VERSION 5.8 ;
BUSBITCHARS "[]" ;
DIVIDERCHAR "/" ;
UNITS
    DATABASE MICRONS 1000 ;
END UNITS

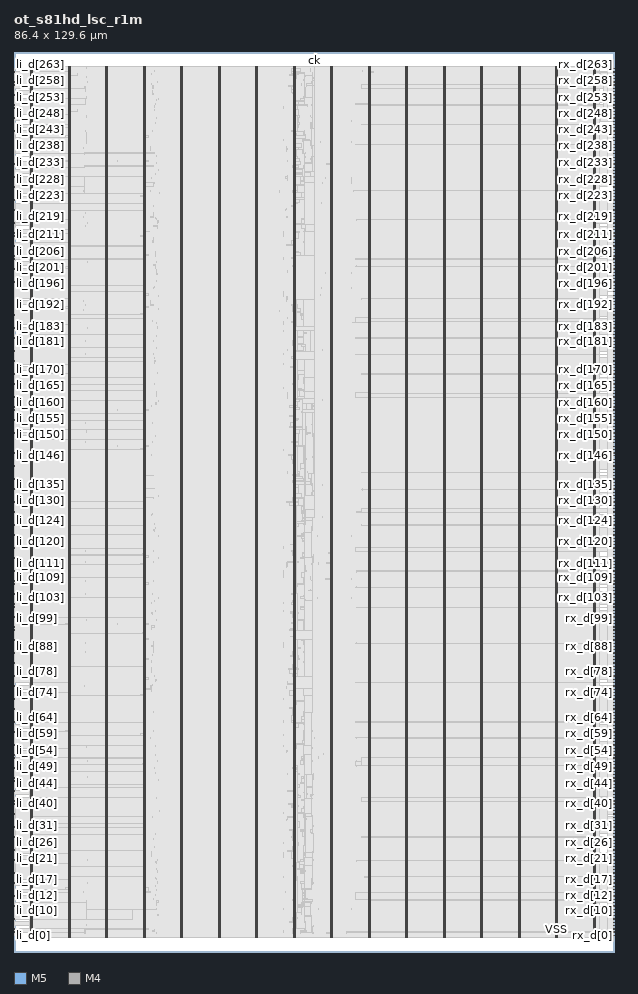
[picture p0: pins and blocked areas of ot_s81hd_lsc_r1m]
MACRO ot_s81hd_lsc_r1m
  FOREIGN ot_s81hd_lsc_r1m 0 0 ;
  CLASS BLOCK ;
  SIZE 86.4 BY 129.6 ;
  PIN ck
    DIRECTION INPUT ;
    USE SIGNAL ;
    PORT
      LAYER M5 ;
        RECT  43.2 129.516 43.224 129.6 ;
    END
  END ck
  PIN li_d[0]
    DIRECTION INPUT ;
    USE SIGNAL ;
    PORT
      LAYER M4 ;
        RECT  0 2.4 0.084 2.424 ;
    END
  END li_d[0]
  PIN li_d[100]
    DIRECTION INPUT ;
    USE SIGNAL ;
    PORT
      LAYER M4 ;
        RECT  0 49.68 0.084 49.704 ;
    END
  END li_d[100]
  PIN li_d[101]
    DIRECTION INPUT ;
    USE SIGNAL ;
    PORT
      LAYER M4 ;
        RECT  0 50.112 0.084 50.136 ;
    END
  END li_d[101]
  PIN li_d[102]
    DIRECTION INPUT ;
    USE SIGNAL ;
    PORT
      LAYER M4 ;
        RECT  0 50.592 0.084 50.616 ;
    END
  END li_d[102]
  PIN li_d[103]
    DIRECTION INPUT ;
    USE SIGNAL ;
    PORT
      LAYER M4 ;
        RECT  0 51.072 0.084 51.096 ;
    END
  END li_d[103]
  PIN li_d[104]
    DIRECTION INPUT ;
    USE SIGNAL ;
    PORT
      LAYER M4 ;
        RECT  0 51.552 0.084 51.576 ;
    END
  END li_d[104]
  PIN li_d[105]
    DIRECTION INPUT ;
    USE SIGNAL ;
    PORT
      LAYER M4 ;
        RECT  0 52.032 0.084 52.056 ;
    END
  END li_d[105]
  PIN li_d[106]
    DIRECTION INPUT ;
    USE SIGNAL ;
    PORT
      LAYER M4 ;
        RECT  0 52.512 0.084 52.536 ;
    END
  END li_d[106]
  PIN li_d[107]
    DIRECTION INPUT ;
    USE SIGNAL ;
    PORT
      LAYER M4 ;
        RECT  0 52.992 0.084 53.016 ;
    END
  END li_d[107]
  PIN li_d[108]
    DIRECTION INPUT ;
    USE SIGNAL ;
    PORT
      LAYER M4 ;
        RECT  0 53.424 0.084 53.448 ;
    END
  END li_d[108]
  PIN li_d[109]
    DIRECTION INPUT ;
    USE SIGNAL ;
    PORT
      LAYER M4 ;
        RECT  0 53.904 0.084 53.928 ;
    END
  END li_d[109]
  PIN li_d[10]
    DIRECTION INPUT ;
    USE SIGNAL ;
    PORT
      LAYER M4 ;
        RECT  0 7.104 0.084 7.128 ;
    END
  END li_d[10]
  PIN li_d[110]
    DIRECTION INPUT ;
    USE SIGNAL ;
    PORT
      LAYER M4 ;
        RECT  0 54.384 0.084 54.408 ;
    END
  END li_d[110]
  PIN li_d[111]
    DIRECTION INPUT ;
    USE SIGNAL ;
    PORT
      LAYER M4 ;
        RECT  0 54.864 0.084 54.888 ;
    END
  END li_d[111]
  PIN li_d[112]
    DIRECTION INPUT ;
    USE SIGNAL ;
    PORT
      LAYER M4 ;
        RECT  0 55.344 0.084 55.368 ;
    END
  END li_d[112]
  PIN li_d[113]
    DIRECTION INPUT ;
    USE SIGNAL ;
    PORT
      LAYER M4 ;
        RECT  0 55.824 0.084 55.848 ;
    END
  END li_d[113]
  PIN li_d[114]
    DIRECTION INPUT ;
    USE SIGNAL ;
    PORT
      LAYER M4 ;
        RECT  0 56.256 0.084 56.28 ;
    END
  END li_d[114]
  PIN li_d[115]
    DIRECTION INPUT ;
    USE SIGNAL ;
    PORT
      LAYER M4 ;
        RECT  0 56.736 0.084 56.76 ;
    END
  END li_d[115]
  PIN li_d[116]
    DIRECTION INPUT ;
    USE SIGNAL ;
    PORT
      LAYER M4 ;
        RECT  0 57.216 0.084 57.24 ;
    END
  END li_d[116]
  PIN li_d[117]
    DIRECTION INPUT ;
    USE SIGNAL ;
    PORT
      LAYER M4 ;
        RECT  0 57.696 0.084 57.72 ;
    END
  END li_d[117]
  PIN li_d[118]
    DIRECTION INPUT ;
    USE SIGNAL ;
    PORT
      LAYER M4 ;
        RECT  0 58.176 0.084 58.2 ;
    END
  END li_d[118]
  PIN li_d[119]
    DIRECTION INPUT ;
    USE SIGNAL ;
    PORT
      LAYER M4 ;
        RECT  0 58.656 0.084 58.68 ;
    END
  END li_d[119]
  PIN li_d[11]
    DIRECTION INPUT ;
    USE SIGNAL ;
    PORT
      LAYER M4 ;
        RECT  0 7.584 0.084 7.608 ;
    END
  END li_d[11]
  PIN li_d[120]
    DIRECTION INPUT ;
    USE SIGNAL ;
    PORT
      LAYER M4 ;
        RECT  0 59.136 0.084 59.16 ;
    END
  END li_d[120]
  PIN li_d[121]
    DIRECTION INPUT ;
    USE SIGNAL ;
    PORT
      LAYER M4 ;
        RECT  0 59.568 0.084 59.592 ;
    END
  END li_d[121]
  PIN li_d[122]
    DIRECTION INPUT ;
    USE SIGNAL ;
    PORT
      LAYER M4 ;
        RECT  0 60.048 0.084 60.072 ;
    END
  END li_d[122]
  PIN li_d[123]
    DIRECTION INPUT ;
    USE SIGNAL ;
    PORT
      LAYER M4 ;
        RECT  0 60.528 0.084 60.552 ;
    END
  END li_d[123]
  PIN li_d[124]
    DIRECTION INPUT ;
    USE SIGNAL ;
    PORT
      LAYER M4 ;
        RECT  0 61.008 0.084 61.032 ;
    END
  END li_d[124]
  PIN li_d[125]
    DIRECTION INPUT ;
    USE SIGNAL ;
    PORT
      LAYER M4 ;
        RECT  0 61.488 0.084 61.512 ;
    END
  END li_d[125]
  PIN li_d[126]
    DIRECTION INPUT ;
    USE SIGNAL ;
    PORT
      LAYER M4 ;
        RECT  0 61.968 0.084 61.992 ;
    END
  END li_d[126]
  PIN li_d[127]
    DIRECTION INPUT ;
    USE SIGNAL ;
    PORT
      LAYER M4 ;
        RECT  0 62.448 0.084 62.472 ;
    END
  END li_d[127]
  PIN li_d[128]
    DIRECTION INPUT ;
    USE SIGNAL ;
    PORT
      LAYER M4 ;
        RECT  0 62.88 0.084 62.904 ;
    END
  END li_d[128]
  PIN li_d[129]
    DIRECTION INPUT ;
    USE SIGNAL ;
    PORT
      LAYER M4 ;
        RECT  0 63.36 0.084 63.384 ;
    END
  END li_d[129]
  PIN li_d[12]
    DIRECTION INPUT ;
    USE SIGNAL ;
    PORT
      LAYER M4 ;
        RECT  0 8.064 0.084 8.088 ;
    END
  END li_d[12]
  PIN li_d[130]
    DIRECTION INPUT ;
    USE SIGNAL ;
    PORT
      LAYER M4 ;
        RECT  0 63.84 0.084 63.864 ;
    END
  END li_d[130]
  PIN li_d[131]
    DIRECTION INPUT ;
    USE SIGNAL ;
    PORT
      LAYER M4 ;
        RECT  0 64.32 0.084 64.344 ;
    END
  END li_d[131]
  PIN li_d[132]
    DIRECTION INPUT ;
    USE SIGNAL ;
    PORT
      LAYER M4 ;
        RECT  0 64.8 0.084 64.824 ;
    END
  END li_d[132]
  PIN li_d[133]
    DIRECTION INPUT ;
    USE SIGNAL ;
    PORT
      LAYER M4 ;
        RECT  0 65.28 0.084 65.304 ;
    END
  END li_d[133]
  PIN li_d[134]
    DIRECTION INPUT ;
    USE SIGNAL ;
    PORT
      LAYER M4 ;
        RECT  0 65.712 0.084 65.736 ;
    END
  END li_d[134]
  PIN li_d[135]
    DIRECTION INPUT ;
    USE SIGNAL ;
    PORT
      LAYER M4 ;
        RECT  0 66.192 0.084 66.216 ;
    END
  END li_d[135]
  PIN li_d[136]
    DIRECTION INPUT ;
    USE SIGNAL ;
    PORT
      LAYER M4 ;
        RECT  0 66.672 0.084 66.696 ;
    END
  END li_d[136]
  PIN li_d[137]
    DIRECTION INPUT ;
    USE SIGNAL ;
    PORT
      LAYER M4 ;
        RECT  0 67.152 0.084 67.176 ;
    END
  END li_d[137]
  PIN li_d[138]
    DIRECTION INPUT ;
    USE SIGNAL ;
    PORT
      LAYER M4 ;
        RECT  0 67.632 0.084 67.656 ;
    END
  END li_d[138]
  PIN li_d[139]
    DIRECTION INPUT ;
    USE SIGNAL ;
    PORT
      LAYER M4 ;
        RECT  0 68.112 0.084 68.136 ;
    END
  END li_d[139]
  PIN li_d[13]
    DIRECTION INPUT ;
    USE SIGNAL ;
    PORT
      LAYER M4 ;
        RECT  0 8.544 0.084 8.568 ;
    END
  END li_d[13]
  PIN li_d[140]
    DIRECTION INPUT ;
    USE SIGNAL ;
    PORT
      LAYER M4 ;
        RECT  0 68.592 0.084 68.616 ;
    END
  END li_d[140]
  PIN li_d[141]
    DIRECTION INPUT ;
    USE SIGNAL ;
    PORT
      LAYER M4 ;
        RECT  0 69.024 0.084 69.048 ;
    END
  END li_d[141]
  PIN li_d[142]
    DIRECTION INPUT ;
    USE SIGNAL ;
    PORT
      LAYER M4 ;
        RECT  0 69.504 0.084 69.528 ;
    END
  END li_d[142]
  PIN li_d[143]
    DIRECTION INPUT ;
    USE SIGNAL ;
    PORT
      LAYER M4 ;
        RECT  0 69.984 0.084 70.008 ;
    END
  END li_d[143]
  PIN li_d[144]
    DIRECTION INPUT ;
    USE SIGNAL ;
    PORT
      LAYER M4 ;
        RECT  0 70.464 0.084 70.488 ;
    END
  END li_d[144]
  PIN li_d[145]
    DIRECTION INPUT ;
    USE SIGNAL ;
    PORT
      LAYER M4 ;
        RECT  0 70.944 0.084 70.968 ;
    END
  END li_d[145]
  PIN li_d[146]
    DIRECTION INPUT ;
    USE SIGNAL ;
    PORT
      LAYER M4 ;
        RECT  0 71.424 0.084 71.448 ;
    END
  END li_d[146]
  PIN li_d[147]
    DIRECTION INPUT ;
    USE SIGNAL ;
    PORT
      LAYER M4 ;
        RECT  0 71.856 0.084 71.88 ;
    END
  END li_d[147]
  PIN li_d[148]
    DIRECTION INPUT ;
    USE SIGNAL ;
    PORT
      LAYER M4 ;
        RECT  0 72.336 0.084 72.36 ;
    END
  END li_d[148]
  PIN li_d[149]
    DIRECTION INPUT ;
    USE SIGNAL ;
    PORT
      LAYER M4 ;
        RECT  0 72.816 0.084 72.84 ;
    END
  END li_d[149]
  PIN li_d[14]
    DIRECTION INPUT ;
    USE SIGNAL ;
    PORT
      LAYER M4 ;
        RECT  0 9.024 0.084 9.048 ;
    END
  END li_d[14]
  PIN li_d[150]
    DIRECTION INPUT ;
    USE SIGNAL ;
    PORT
      LAYER M4 ;
        RECT  0 73.296 0.084 73.32 ;
    END
  END li_d[150]
  PIN li_d[151]
    DIRECTION INPUT ;
    USE SIGNAL ;
    PORT
      LAYER M4 ;
        RECT  0 73.776 0.084 73.8 ;
    END
  END li_d[151]
  PIN li_d[152]
    DIRECTION INPUT ;
    USE SIGNAL ;
    PORT
      LAYER M4 ;
        RECT  0 74.256 0.084 74.28 ;
    END
  END li_d[152]
  PIN li_d[153]
    DIRECTION INPUT ;
    USE SIGNAL ;
    PORT
      LAYER M4 ;
        RECT  0 74.736 0.084 74.76 ;
    END
  END li_d[153]
  PIN li_d[154]
    DIRECTION INPUT ;
    USE SIGNAL ;
    PORT
      LAYER M4 ;
        RECT  0 75.168 0.084 75.192 ;
    END
  END li_d[154]
  PIN li_d[155]
    DIRECTION INPUT ;
    USE SIGNAL ;
    PORT
      LAYER M4 ;
        RECT  0 75.648 0.084 75.672 ;
    END
  END li_d[155]
  PIN li_d[156]
    DIRECTION INPUT ;
    USE SIGNAL ;
    PORT
      LAYER M4 ;
        RECT  0 76.128 0.084 76.152 ;
    END
  END li_d[156]
  PIN li_d[157]
    DIRECTION INPUT ;
    USE SIGNAL ;
    PORT
      LAYER M4 ;
        RECT  0 76.608 0.084 76.632 ;
    END
  END li_d[157]
  PIN li_d[158]
    DIRECTION INPUT ;
    USE SIGNAL ;
    PORT
      LAYER M4 ;
        RECT  0 77.088 0.084 77.112 ;
    END
  END li_d[158]
  PIN li_d[159]
    DIRECTION INPUT ;
    USE SIGNAL ;
    PORT
      LAYER M4 ;
        RECT  0 77.568 0.084 77.592 ;
    END
  END li_d[159]
  PIN li_d[15]
    DIRECTION INPUT ;
    USE SIGNAL ;
    PORT
      LAYER M4 ;
        RECT  0 9.456 0.084 9.48 ;
    END
  END li_d[15]
  PIN li_d[160]
    DIRECTION INPUT ;
    USE SIGNAL ;
    PORT
      LAYER M4 ;
        RECT  0 78.048 0.084 78.072 ;
    END
  END li_d[160]
  PIN li_d[161]
    DIRECTION INPUT ;
    USE SIGNAL ;
    PORT
      LAYER M4 ;
        RECT  0 78.48 0.084 78.504 ;
    END
  END li_d[161]
  PIN li_d[162]
    DIRECTION INPUT ;
    USE SIGNAL ;
    PORT
      LAYER M4 ;
        RECT  0 78.96 0.084 78.984 ;
    END
  END li_d[162]
  PIN li_d[163]
    DIRECTION INPUT ;
    USE SIGNAL ;
    PORT
      LAYER M4 ;
        RECT  0 79.44 0.084 79.464 ;
    END
  END li_d[163]
  PIN li_d[164]
    DIRECTION INPUT ;
    USE SIGNAL ;
    PORT
      LAYER M4 ;
        RECT  0 79.92 0.084 79.944 ;
    END
  END li_d[164]
  PIN li_d[165]
    DIRECTION INPUT ;
    USE SIGNAL ;
    PORT
      LAYER M4 ;
        RECT  0 80.4 0.084 80.424 ;
    END
  END li_d[165]
  PIN li_d[166]
    DIRECTION INPUT ;
    USE SIGNAL ;
    PORT
      LAYER M4 ;
        RECT  0 80.88 0.084 80.904 ;
    END
  END li_d[166]
  PIN li_d[167]
    DIRECTION INPUT ;
    USE SIGNAL ;
    PORT
      LAYER M4 ;
        RECT  0 81.312 0.084 81.336 ;
    END
  END li_d[167]
  PIN li_d[168]
    DIRECTION INPUT ;
    USE SIGNAL ;
    PORT
      LAYER M4 ;
        RECT  0 81.792 0.084 81.816 ;
    END
  END li_d[168]
  PIN li_d[169]
    DIRECTION INPUT ;
    USE SIGNAL ;
    PORT
      LAYER M4 ;
        RECT  0 82.272 0.084 82.296 ;
    END
  END li_d[169]
  PIN li_d[16]
    DIRECTION INPUT ;
    USE SIGNAL ;
    PORT
      LAYER M4 ;
        RECT  0 9.936 0.084 9.96 ;
    END
  END li_d[16]
  PIN li_d[170]
    DIRECTION INPUT ;
    USE SIGNAL ;
    PORT
      LAYER M4 ;
        RECT  0 82.752 0.084 82.776 ;
    END
  END li_d[170]
  PIN li_d[171]
    DIRECTION INPUT ;
    USE SIGNAL ;
    PORT
      LAYER M4 ;
        RECT  0 83.232 0.084 83.256 ;
    END
  END li_d[171]
  PIN li_d[172]
    DIRECTION INPUT ;
    USE SIGNAL ;
    PORT
      LAYER M4 ;
        RECT  0 83.712 0.084 83.736 ;
    END
  END li_d[172]
  PIN li_d[173]
    DIRECTION INPUT ;
    USE SIGNAL ;
    PORT
      LAYER M4 ;
        RECT  0 84.192 0.084 84.216 ;
    END
  END li_d[173]
  PIN li_d[174]
    DIRECTION INPUT ;
    USE SIGNAL ;
    PORT
      LAYER M4 ;
        RECT  0 84.624 0.084 84.648 ;
    END
  END li_d[174]
  PIN li_d[175]
    DIRECTION INPUT ;
    USE SIGNAL ;
    PORT
      LAYER M4 ;
        RECT  0 85.104 0.084 85.128 ;
    END
  END li_d[175]
  PIN li_d[176]
    DIRECTION INPUT ;
    USE SIGNAL ;
    PORT
      LAYER M4 ;
        RECT  0 85.584 0.084 85.608 ;
    END
  END li_d[176]
  PIN li_d[177]
    DIRECTION INPUT ;
    USE SIGNAL ;
    PORT
      LAYER M4 ;
        RECT  0 86.064 0.084 86.088 ;
    END
  END li_d[177]
  PIN li_d[178]
    DIRECTION INPUT ;
    USE SIGNAL ;
    PORT
      LAYER M4 ;
        RECT  0 86.544 0.084 86.568 ;
    END
  END li_d[178]
  PIN li_d[179]
    DIRECTION INPUT ;
    USE SIGNAL ;
    PORT
      LAYER M4 ;
        RECT  0 87.024 0.084 87.048 ;
    END
  END li_d[179]
  PIN li_d[17]
    DIRECTION INPUT ;
    USE SIGNAL ;
    PORT
      LAYER M4 ;
        RECT  0 10.416 0.084 10.44 ;
    END
  END li_d[17]
  PIN li_d[180]
    DIRECTION INPUT ;
    USE SIGNAL ;
    PORT
      LAYER M4 ;
        RECT  0 87.504 0.084 87.528 ;
    END
  END li_d[180]
  PIN li_d[181]
    DIRECTION INPUT ;
    USE SIGNAL ;
    PORT
      LAYER M4 ;
        RECT  0 87.936 0.084 87.96 ;
    END
  END li_d[181]
  PIN li_d[182]
    DIRECTION INPUT ;
    USE SIGNAL ;
    PORT
      LAYER M4 ;
        RECT  0 88.416 0.084 88.44 ;
    END
  END li_d[182]
  PIN li_d[183]
    DIRECTION INPUT ;
    USE SIGNAL ;
    PORT
      LAYER M4 ;
        RECT  0 88.896 0.084 88.92 ;
    END
  END li_d[183]
  PIN li_d[184]
    DIRECTION INPUT ;
    USE SIGNAL ;
    PORT
      LAYER M4 ;
        RECT  0 89.376 0.084 89.4 ;
    END
  END li_d[184]
  PIN li_d[185]
    DIRECTION INPUT ;
    USE SIGNAL ;
    PORT
      LAYER M4 ;
        RECT  0 89.856 0.084 89.88 ;
    END
  END li_d[185]
  PIN li_d[186]
    DIRECTION INPUT ;
    USE SIGNAL ;
    PORT
      LAYER M4 ;
        RECT  0 90.336 0.084 90.36 ;
    END
  END li_d[186]
  PIN li_d[187]
    DIRECTION INPUT ;
    USE SIGNAL ;
    PORT
      LAYER M4 ;
        RECT  0 90.768 0.084 90.792 ;
    END
  END li_d[187]
  PIN li_d[188]
    DIRECTION INPUT ;
    USE SIGNAL ;
    PORT
      LAYER M4 ;
        RECT  0 91.248 0.084 91.272 ;
    END
  END li_d[188]
  PIN li_d[189]
    DIRECTION INPUT ;
    USE SIGNAL ;
    PORT
      LAYER M4 ;
        RECT  0 91.728 0.084 91.752 ;
    END
  END li_d[189]
  PIN li_d[18]
    DIRECTION INPUT ;
    USE SIGNAL ;
    PORT
      LAYER M4 ;
        RECT  0 10.896 0.084 10.92 ;
    END
  END li_d[18]
  PIN li_d[190]
    DIRECTION INPUT ;
    USE SIGNAL ;
    PORT
      LAYER M4 ;
        RECT  0 92.208 0.084 92.232 ;
    END
  END li_d[190]
  PIN li_d[191]
    DIRECTION INPUT ;
    USE SIGNAL ;
    PORT
      LAYER M4 ;
        RECT  0 92.688 0.084 92.712 ;
    END
  END li_d[191]
  PIN li_d[192]
    DIRECTION INPUT ;
    USE SIGNAL ;
    PORT
      LAYER M4 ;
        RECT  0 93.168 0.084 93.192 ;
    END
  END li_d[192]
  PIN li_d[193]
    DIRECTION INPUT ;
    USE SIGNAL ;
    PORT
      LAYER M4 ;
        RECT  0 93.648 0.084 93.672 ;
    END
  END li_d[193]
  PIN li_d[194]
    DIRECTION INPUT ;
    USE SIGNAL ;
    PORT
      LAYER M4 ;
        RECT  0 94.08 0.084 94.104 ;
    END
  END li_d[194]
  PIN li_d[195]
    DIRECTION INPUT ;
    USE SIGNAL ;
    PORT
      LAYER M4 ;
        RECT  0 94.56 0.084 94.584 ;
    END
  END li_d[195]
  PIN li_d[196]
    DIRECTION INPUT ;
    USE SIGNAL ;
    PORT
      LAYER M4 ;
        RECT  0 95.04 0.084 95.064 ;
    END
  END li_d[196]
  PIN li_d[197]
    DIRECTION INPUT ;
    USE SIGNAL ;
    PORT
      LAYER M4 ;
        RECT  0 95.52 0.084 95.544 ;
    END
  END li_d[197]
  PIN li_d[198]
    DIRECTION INPUT ;
    USE SIGNAL ;
    PORT
      LAYER M4 ;
        RECT  0 96 0.084 96.024 ;
    END
  END li_d[198]
  PIN li_d[199]
    DIRECTION INPUT ;
    USE SIGNAL ;
    PORT
      LAYER M4 ;
        RECT  0 96.48 0.084 96.504 ;
    END
  END li_d[199]
  PIN li_d[19]
    DIRECTION INPUT ;
    USE SIGNAL ;
    PORT
      LAYER M4 ;
        RECT  0 11.376 0.084 11.4 ;
    END
  END li_d[19]
  PIN li_d[1]
    DIRECTION INPUT ;
    USE SIGNAL ;
    PORT
      LAYER M4 ;
        RECT  0 2.88 0.084 2.904 ;
    END
  END li_d[1]
  PIN li_d[200]
    DIRECTION INPUT ;
    USE SIGNAL ;
    PORT
      LAYER M4 ;
        RECT  0 96.912 0.084 96.936 ;
    END
  END li_d[200]
  PIN li_d[201]
    DIRECTION INPUT ;
    USE SIGNAL ;
    PORT
      LAYER M4 ;
        RECT  0 97.392 0.084 97.416 ;
    END
  END li_d[201]
  PIN li_d[202]
    DIRECTION INPUT ;
    USE SIGNAL ;
    PORT
      LAYER M4 ;
        RECT  0 97.872 0.084 97.896 ;
    END
  END li_d[202]
  PIN li_d[203]
    DIRECTION INPUT ;
    USE SIGNAL ;
    PORT
      LAYER M4 ;
        RECT  0 98.352 0.084 98.376 ;
    END
  END li_d[203]
  PIN li_d[204]
    DIRECTION INPUT ;
    USE SIGNAL ;
    PORT
      LAYER M4 ;
        RECT  0 98.832 0.084 98.856 ;
    END
  END li_d[204]
  PIN li_d[205]
    DIRECTION INPUT ;
    USE SIGNAL ;
    PORT
      LAYER M4 ;
        RECT  0 99.312 0.084 99.336 ;
    END
  END li_d[205]
  PIN li_d[206]
    DIRECTION INPUT ;
    USE SIGNAL ;
    PORT
      LAYER M4 ;
        RECT  0 99.792 0.084 99.816 ;
    END
  END li_d[206]
  PIN li_d[207]
    DIRECTION INPUT ;
    USE SIGNAL ;
    PORT
      LAYER M4 ;
        RECT  0 100.224 0.084 100.248 ;
    END
  END li_d[207]
  PIN li_d[208]
    DIRECTION INPUT ;
    USE SIGNAL ;
    PORT
      LAYER M4 ;
        RECT  0 100.704 0.084 100.728 ;
    END
  END li_d[208]
  PIN li_d[209]
    DIRECTION INPUT ;
    USE SIGNAL ;
    PORT
      LAYER M4 ;
        RECT  0 101.184 0.084 101.208 ;
    END
  END li_d[209]
  PIN li_d[20]
    DIRECTION INPUT ;
    USE SIGNAL ;
    PORT
      LAYER M4 ;
        RECT  0 11.856 0.084 11.88 ;
    END
  END li_d[20]
  PIN li_d[210]
    DIRECTION INPUT ;
    USE SIGNAL ;
    PORT
      LAYER M4 ;
        RECT  0 101.664 0.084 101.688 ;
    END
  END li_d[210]
  PIN li_d[211]
    DIRECTION INPUT ;
    USE SIGNAL ;
    PORT
      LAYER M4 ;
        RECT  0 102.144 0.084 102.168 ;
    END
  END li_d[211]
  PIN li_d[212]
    DIRECTION INPUT ;
    USE SIGNAL ;
    PORT
      LAYER M4 ;
        RECT  0 102.624 0.084 102.648 ;
    END
  END li_d[212]
  PIN li_d[213]
    DIRECTION INPUT ;
    USE SIGNAL ;
    PORT
      LAYER M4 ;
        RECT  0 103.104 0.084 103.128 ;
    END
  END li_d[213]
  PIN li_d[214]
    DIRECTION INPUT ;
    USE SIGNAL ;
    PORT
      LAYER M4 ;
        RECT  0 103.536 0.084 103.56 ;
    END
  END li_d[214]
  PIN li_d[215]
    DIRECTION INPUT ;
    USE SIGNAL ;
    PORT
      LAYER M4 ;
        RECT  0 104.016 0.084 104.04 ;
    END
  END li_d[215]
  PIN li_d[216]
    DIRECTION INPUT ;
    USE SIGNAL ;
    PORT
      LAYER M4 ;
        RECT  0 104.496 0.084 104.52 ;
    END
  END li_d[216]
  PIN li_d[217]
    DIRECTION INPUT ;
    USE SIGNAL ;
    PORT
      LAYER M4 ;
        RECT  0 104.976 0.084 105 ;
    END
  END li_d[217]
  PIN li_d[218]
    DIRECTION INPUT ;
    USE SIGNAL ;
    PORT
      LAYER M4 ;
        RECT  0 105.456 0.084 105.48 ;
    END
  END li_d[218]
  PIN li_d[219]
    DIRECTION INPUT ;
    USE SIGNAL ;
    PORT
      LAYER M4 ;
        RECT  0 105.936 0.084 105.96 ;
    END
  END li_d[219]
  PIN li_d[21]
    DIRECTION INPUT ;
    USE SIGNAL ;
    PORT
      LAYER M4 ;
        RECT  0 12.336 0.084 12.36 ;
    END
  END li_d[21]
  PIN li_d[220]
    DIRECTION INPUT ;
    USE SIGNAL ;
    PORT
      LAYER M4 ;
        RECT  0 106.368 0.084 106.392 ;
    END
  END li_d[220]
  PIN li_d[221]
    DIRECTION INPUT ;
    USE SIGNAL ;
    PORT
      LAYER M4 ;
        RECT  0 106.848 0.084 106.872 ;
    END
  END li_d[221]
  PIN li_d[222]
    DIRECTION INPUT ;
    USE SIGNAL ;
    PORT
      LAYER M4 ;
        RECT  0 107.328 0.084 107.352 ;
    END
  END li_d[222]
  PIN li_d[223]
    DIRECTION INPUT ;
    USE SIGNAL ;
    PORT
      LAYER M4 ;
        RECT  0 107.808 0.084 107.832 ;
    END
  END li_d[223]
  PIN li_d[224]
    DIRECTION INPUT ;
    USE SIGNAL ;
    PORT
      LAYER M4 ;
        RECT  0 108.288 0.084 108.312 ;
    END
  END li_d[224]
  PIN li_d[225]
    DIRECTION INPUT ;
    USE SIGNAL ;
    PORT
      LAYER M4 ;
        RECT  0 108.768 0.084 108.792 ;
    END
  END li_d[225]
  PIN li_d[226]
    DIRECTION INPUT ;
    USE SIGNAL ;
    PORT
      LAYER M4 ;
        RECT  0 109.248 0.084 109.272 ;
    END
  END li_d[226]
  PIN li_d[227]
    DIRECTION INPUT ;
    USE SIGNAL ;
    PORT
      LAYER M4 ;
        RECT  0 109.68 0.084 109.704 ;
    END
  END li_d[227]
  PIN li_d[228]
    DIRECTION INPUT ;
    USE SIGNAL ;
    PORT
      LAYER M4 ;
        RECT  0 110.16 0.084 110.184 ;
    END
  END li_d[228]
  PIN li_d[229]
    DIRECTION INPUT ;
    USE SIGNAL ;
    PORT
      LAYER M4 ;
        RECT  0 110.64 0.084 110.664 ;
    END
  END li_d[229]
  PIN li_d[22]
    DIRECTION INPUT ;
    USE SIGNAL ;
    PORT
      LAYER M4 ;
        RECT  0 12.768 0.084 12.792 ;
    END
  END li_d[22]
  PIN li_d[230]
    DIRECTION INPUT ;
    USE SIGNAL ;
    PORT
      LAYER M4 ;
        RECT  0 111.12 0.084 111.144 ;
    END
  END li_d[230]
  PIN li_d[231]
    DIRECTION INPUT ;
    USE SIGNAL ;
    PORT
      LAYER M4 ;
        RECT  0 111.6 0.084 111.624 ;
    END
  END li_d[231]
  PIN li_d[232]
    DIRECTION INPUT ;
    USE SIGNAL ;
    PORT
      LAYER M4 ;
        RECT  0 112.08 0.084 112.104 ;
    END
  END li_d[232]
  PIN li_d[233]
    DIRECTION INPUT ;
    USE SIGNAL ;
    PORT
      LAYER M4 ;
        RECT  0 112.56 0.084 112.584 ;
    END
  END li_d[233]
  PIN li_d[234]
    DIRECTION INPUT ;
    USE SIGNAL ;
    PORT
      LAYER M4 ;
        RECT  0 112.992 0.084 113.016 ;
    END
  END li_d[234]
  PIN li_d[235]
    DIRECTION INPUT ;
    USE SIGNAL ;
    PORT
      LAYER M4 ;
        RECT  0 113.472 0.084 113.496 ;
    END
  END li_d[235]
  PIN li_d[236]
    DIRECTION INPUT ;
    USE SIGNAL ;
    PORT
      LAYER M4 ;
        RECT  0 113.952 0.084 113.976 ;
    END
  END li_d[236]
  PIN li_d[237]
    DIRECTION INPUT ;
    USE SIGNAL ;
    PORT
      LAYER M4 ;
        RECT  0 114.432 0.084 114.456 ;
    END
  END li_d[237]
  PIN li_d[238]
    DIRECTION INPUT ;
    USE SIGNAL ;
    PORT
      LAYER M4 ;
        RECT  0 114.912 0.084 114.936 ;
    END
  END li_d[238]
  PIN li_d[239]
    DIRECTION INPUT ;
    USE SIGNAL ;
    PORT
      LAYER M4 ;
        RECT  0 115.392 0.084 115.416 ;
    END
  END li_d[239]
  PIN li_d[23]
    DIRECTION INPUT ;
    USE SIGNAL ;
    PORT
      LAYER M4 ;
        RECT  0 13.248 0.084 13.272 ;
    END
  END li_d[23]
  PIN li_d[240]
    DIRECTION INPUT ;
    USE SIGNAL ;
    PORT
      LAYER M4 ;
        RECT  0 115.824 0.084 115.848 ;
    END
  END li_d[240]
  PIN li_d[241]
    DIRECTION INPUT ;
    USE SIGNAL ;
    PORT
      LAYER M4 ;
        RECT  0 116.304 0.084 116.328 ;
    END
  END li_d[241]
  PIN li_d[242]
    DIRECTION INPUT ;
    USE SIGNAL ;
    PORT
      LAYER M4 ;
        RECT  0 116.784 0.084 116.808 ;
    END
  END li_d[242]
  PIN li_d[243]
    DIRECTION INPUT ;
    USE SIGNAL ;
    PORT
      LAYER M4 ;
        RECT  0 117.264 0.084 117.288 ;
    END
  END li_d[243]
  PIN li_d[244]
    DIRECTION INPUT ;
    USE SIGNAL ;
    PORT
      LAYER M4 ;
        RECT  0 117.744 0.084 117.768 ;
    END
  END li_d[244]
  PIN li_d[245]
    DIRECTION INPUT ;
    USE SIGNAL ;
    PORT
      LAYER M4 ;
        RECT  0 118.224 0.084 118.248 ;
    END
  END li_d[245]
  PIN li_d[246]
    DIRECTION INPUT ;
    USE SIGNAL ;
    PORT
      LAYER M4 ;
        RECT  0 118.704 0.084 118.728 ;
    END
  END li_d[246]
  PIN li_d[247]
    DIRECTION INPUT ;
    USE SIGNAL ;
    PORT
      LAYER M4 ;
        RECT  0 119.136 0.084 119.16 ;
    END
  END li_d[247]
  PIN li_d[248]
    DIRECTION INPUT ;
    USE SIGNAL ;
    PORT
      LAYER M4 ;
        RECT  0 119.616 0.084 119.64 ;
    END
  END li_d[248]
  PIN li_d[249]
    DIRECTION INPUT ;
    USE SIGNAL ;
    PORT
      LAYER M4 ;
        RECT  0 120.096 0.084 120.12 ;
    END
  END li_d[249]
  PIN li_d[24]
    DIRECTION INPUT ;
    USE SIGNAL ;
    PORT
      LAYER M4 ;
        RECT  0 13.728 0.084 13.752 ;
    END
  END li_d[24]
  PIN li_d[250]
    DIRECTION INPUT ;
    USE SIGNAL ;
    PORT
      LAYER M4 ;
        RECT  0 120.576 0.084 120.6 ;
    END
  END li_d[250]
  PIN li_d[251]
    DIRECTION INPUT ;
    USE SIGNAL ;
    PORT
      LAYER M4 ;
        RECT  0 121.056 0.084 121.08 ;
    END
  END li_d[251]
  PIN li_d[252]
    DIRECTION INPUT ;
    USE SIGNAL ;
    PORT
      LAYER M4 ;
        RECT  0 121.536 0.084 121.56 ;
    END
  END li_d[252]
  PIN li_d[253]
    DIRECTION INPUT ;
    USE SIGNAL ;
    PORT
      LAYER M4 ;
        RECT  0 121.968 0.084 121.992 ;
    END
  END li_d[253]
  PIN li_d[254]
    DIRECTION INPUT ;
    USE SIGNAL ;
    PORT
      LAYER M4 ;
        RECT  0 122.448 0.084 122.472 ;
    END
  END li_d[254]
  PIN li_d[255]
    DIRECTION INPUT ;
    USE SIGNAL ;
    PORT
      LAYER M4 ;
        RECT  0 122.928 0.084 122.952 ;
    END
  END li_d[255]
  PIN li_d[256]
    DIRECTION INPUT ;
    USE SIGNAL ;
    PORT
      LAYER M4 ;
        RECT  0 123.408 0.084 123.432 ;
    END
  END li_d[256]
  PIN li_d[257]
    DIRECTION INPUT ;
    USE SIGNAL ;
    PORT
      LAYER M4 ;
        RECT  0 123.888 0.084 123.912 ;
    END
  END li_d[257]
  PIN li_d[258]
    DIRECTION INPUT ;
    USE SIGNAL ;
    PORT
      LAYER M4 ;
        RECT  0 124.368 0.084 124.392 ;
    END
  END li_d[258]
  PIN li_d[259]
    DIRECTION INPUT ;
    USE SIGNAL ;
    PORT
      LAYER M4 ;
        RECT  0 124.848 0.084 124.872 ;
    END
  END li_d[259]
  PIN li_d[25]
    DIRECTION INPUT ;
    USE SIGNAL ;
    PORT
      LAYER M4 ;
        RECT  0 14.208 0.084 14.232 ;
    END
  END li_d[25]
  PIN li_d[260]
    DIRECTION INPUT ;
    USE SIGNAL ;
    PORT
      LAYER M4 ;
        RECT  0 125.28 0.084 125.304 ;
    END
  END li_d[260]
  PIN li_d[261]
    DIRECTION INPUT ;
    USE SIGNAL ;
    PORT
      LAYER M4 ;
        RECT  0 125.76 0.084 125.784 ;
    END
  END li_d[261]
  PIN li_d[262]
    DIRECTION INPUT ;
    USE SIGNAL ;
    PORT
      LAYER M4 ;
        RECT  0 126.24 0.084 126.264 ;
    END
  END li_d[262]
  PIN li_d[263]
    DIRECTION INPUT ;
    USE SIGNAL ;
    PORT
      LAYER M4 ;
        RECT  0 126.72 0.084 126.744 ;
    END
  END li_d[263]
  PIN li_d[264]
    DIRECTION INPUT ;
    USE SIGNAL ;
    PORT
      LAYER M4 ;
        RECT  0 127.2 0.084 127.224 ;
    END
  END li_d[264]
  PIN li_d[26]
    DIRECTION INPUT ;
    USE SIGNAL ;
    PORT
      LAYER M4 ;
        RECT  0 14.688 0.084 14.712 ;
    END
  END li_d[26]
  PIN li_d[27]
    DIRECTION INPUT ;
    USE SIGNAL ;
    PORT
      LAYER M4 ;
        RECT  0 15.168 0.084 15.192 ;
    END
  END li_d[27]
  PIN li_d[28]
    DIRECTION INPUT ;
    USE SIGNAL ;
    PORT
      LAYER M4 ;
        RECT  0 15.6 0.084 15.624 ;
    END
  END li_d[28]
  PIN li_d[29]
    DIRECTION INPUT ;
    USE SIGNAL ;
    PORT
      LAYER M4 ;
        RECT  0 16.08 0.084 16.104 ;
    END
  END li_d[29]
  PIN li_d[2]
    DIRECTION INPUT ;
    USE SIGNAL ;
    PORT
      LAYER M4 ;
        RECT  0 3.312 0.084 3.336 ;
    END
  END li_d[2]
  PIN li_d[30]
    DIRECTION INPUT ;
    USE SIGNAL ;
    PORT
      LAYER M4 ;
        RECT  0 16.56 0.084 16.584 ;
    END
  END li_d[30]
  PIN li_d[31]
    DIRECTION INPUT ;
    USE SIGNAL ;
    PORT
      LAYER M4 ;
        RECT  0 17.04 0.084 17.064 ;
    END
  END li_d[31]
  PIN li_d[32]
    DIRECTION INPUT ;
    USE SIGNAL ;
    PORT
      LAYER M4 ;
        RECT  0 17.52 0.084 17.544 ;
    END
  END li_d[32]
  PIN li_d[33]
    DIRECTION INPUT ;
    USE SIGNAL ;
    PORT
      LAYER M4 ;
        RECT  0 18 0.084 18.024 ;
    END
  END li_d[33]
  PIN li_d[34]
    DIRECTION INPUT ;
    USE SIGNAL ;
    PORT
      LAYER M4 ;
        RECT  0 18.48 0.084 18.504 ;
    END
  END li_d[34]
  PIN li_d[35]
    DIRECTION INPUT ;
    USE SIGNAL ;
    PORT
      LAYER M4 ;
        RECT  0 18.912 0.084 18.936 ;
    END
  END li_d[35]
  PIN li_d[36]
    DIRECTION INPUT ;
    USE SIGNAL ;
    PORT
      LAYER M4 ;
        RECT  0 19.392 0.084 19.416 ;
    END
  END li_d[36]
  PIN li_d[37]
    DIRECTION INPUT ;
    USE SIGNAL ;
    PORT
      LAYER M4 ;
        RECT  0 19.872 0.084 19.896 ;
    END
  END li_d[37]
  PIN li_d[38]
    DIRECTION INPUT ;
    USE SIGNAL ;
    PORT
      LAYER M4 ;
        RECT  0 20.352 0.084 20.376 ;
    END
  END li_d[38]
  PIN li_d[39]
    DIRECTION INPUT ;
    USE SIGNAL ;
    PORT
      LAYER M4 ;
        RECT  0 20.832 0.084 20.856 ;
    END
  END li_d[39]
  PIN li_d[3]
    DIRECTION INPUT ;
    USE SIGNAL ;
    PORT
      LAYER M4 ;
        RECT  0 3.792 0.084 3.816 ;
    END
  END li_d[3]
  PIN li_d[40]
    DIRECTION INPUT ;
    USE SIGNAL ;
    PORT
      LAYER M4 ;
        RECT  0 21.312 0.084 21.336 ;
    END
  END li_d[40]
  PIN li_d[41]
    DIRECTION INPUT ;
    USE SIGNAL ;
    PORT
      LAYER M4 ;
        RECT  0 21.744 0.084 21.768 ;
    END
  END li_d[41]
  PIN li_d[42]
    DIRECTION INPUT ;
    USE SIGNAL ;
    PORT
      LAYER M4 ;
        RECT  0 22.224 0.084 22.248 ;
    END
  END li_d[42]
  PIN li_d[43]
    DIRECTION INPUT ;
    USE SIGNAL ;
    PORT
      LAYER M4 ;
        RECT  0 22.704 0.084 22.728 ;
    END
  END li_d[43]
  PIN li_d[44]
    DIRECTION INPUT ;
    USE SIGNAL ;
    PORT
      LAYER M4 ;
        RECT  0 23.184 0.084 23.208 ;
    END
  END li_d[44]
  PIN li_d[45]
    DIRECTION INPUT ;
    USE SIGNAL ;
    PORT
      LAYER M4 ;
        RECT  0 23.664 0.084 23.688 ;
    END
  END li_d[45]
  PIN li_d[46]
    DIRECTION INPUT ;
    USE SIGNAL ;
    PORT
      LAYER M4 ;
        RECT  0 24.144 0.084 24.168 ;
    END
  END li_d[46]
  PIN li_d[47]
    DIRECTION INPUT ;
    USE SIGNAL ;
    PORT
      LAYER M4 ;
        RECT  0 24.624 0.084 24.648 ;
    END
  END li_d[47]
  PIN li_d[48]
    DIRECTION INPUT ;
    USE SIGNAL ;
    PORT
      LAYER M4 ;
        RECT  0 25.056 0.084 25.08 ;
    END
  END li_d[48]
  PIN li_d[49]
    DIRECTION INPUT ;
    USE SIGNAL ;
    PORT
      LAYER M4 ;
        RECT  0 25.536 0.084 25.56 ;
    END
  END li_d[49]
  PIN li_d[4]
    DIRECTION INPUT ;
    USE SIGNAL ;
    PORT
      LAYER M4 ;
        RECT  0 4.272 0.084 4.296 ;
    END
  END li_d[4]
  PIN li_d[50]
    DIRECTION INPUT ;
    USE SIGNAL ;
    PORT
      LAYER M4 ;
        RECT  0 26.016 0.084 26.04 ;
    END
  END li_d[50]
  PIN li_d[51]
    DIRECTION INPUT ;
    USE SIGNAL ;
    PORT
      LAYER M4 ;
        RECT  0 26.496 0.084 26.52 ;
    END
  END li_d[51]
  PIN li_d[52]
    DIRECTION INPUT ;
    USE SIGNAL ;
    PORT
      LAYER M4 ;
        RECT  0 26.976 0.084 27 ;
    END
  END li_d[52]
  PIN li_d[53]
    DIRECTION INPUT ;
    USE SIGNAL ;
    PORT
      LAYER M4 ;
        RECT  0 27.456 0.084 27.48 ;
    END
  END li_d[53]
  PIN li_d[54]
    DIRECTION INPUT ;
    USE SIGNAL ;
    PORT
      LAYER M4 ;
        RECT  0 27.936 0.084 27.96 ;
    END
  END li_d[54]
  PIN li_d[55]
    DIRECTION INPUT ;
    USE SIGNAL ;
    PORT
      LAYER M4 ;
        RECT  0 28.368 0.084 28.392 ;
    END
  END li_d[55]
  PIN li_d[56]
    DIRECTION INPUT ;
    USE SIGNAL ;
    PORT
      LAYER M4 ;
        RECT  0 28.848 0.084 28.872 ;
    END
  END li_d[56]
  PIN li_d[57]
    DIRECTION INPUT ;
    USE SIGNAL ;
    PORT
      LAYER M4 ;
        RECT  0 29.328 0.084 29.352 ;
    END
  END li_d[57]
  PIN li_d[58]
    DIRECTION INPUT ;
    USE SIGNAL ;
    PORT
      LAYER M4 ;
        RECT  0 29.808 0.084 29.832 ;
    END
  END li_d[58]
  PIN li_d[59]
    DIRECTION INPUT ;
    USE SIGNAL ;
    PORT
      LAYER M4 ;
        RECT  0 30.288 0.084 30.312 ;
    END
  END li_d[59]
  PIN li_d[5]
    DIRECTION INPUT ;
    USE SIGNAL ;
    PORT
      LAYER M4 ;
        RECT  0 4.752 0.084 4.776 ;
    END
  END li_d[5]
  PIN li_d[60]
    DIRECTION INPUT ;
    USE SIGNAL ;
    PORT
      LAYER M4 ;
        RECT  0 30.768 0.084 30.792 ;
    END
  END li_d[60]
  PIN li_d[61]
    DIRECTION INPUT ;
    USE SIGNAL ;
    PORT
      LAYER M4 ;
        RECT  0 31.2 0.084 31.224 ;
    END
  END li_d[61]
  PIN li_d[62]
    DIRECTION INPUT ;
    USE SIGNAL ;
    PORT
      LAYER M4 ;
        RECT  0 31.68 0.084 31.704 ;
    END
  END li_d[62]
  PIN li_d[63]
    DIRECTION INPUT ;
    USE SIGNAL ;
    PORT
      LAYER M4 ;
        RECT  0 32.16 0.084 32.184 ;
    END
  END li_d[63]
  PIN li_d[64]
    DIRECTION INPUT ;
    USE SIGNAL ;
    PORT
      LAYER M4 ;
        RECT  0 32.64 0.084 32.664 ;
    END
  END li_d[64]
  PIN li_d[65]
    DIRECTION INPUT ;
    USE SIGNAL ;
    PORT
      LAYER M4 ;
        RECT  0 33.12 0.084 33.144 ;
    END
  END li_d[65]
  PIN li_d[66]
    DIRECTION INPUT ;
    USE SIGNAL ;
    PORT
      LAYER M4 ;
        RECT  0 33.6 0.084 33.624 ;
    END
  END li_d[66]
  PIN li_d[67]
    DIRECTION INPUT ;
    USE SIGNAL ;
    PORT
      LAYER M4 ;
        RECT  0 34.08 0.084 34.104 ;
    END
  END li_d[67]
  PIN li_d[68]
    DIRECTION INPUT ;
    USE SIGNAL ;
    PORT
      LAYER M4 ;
        RECT  0 34.512 0.084 34.536 ;
    END
  END li_d[68]
  PIN li_d[69]
    DIRECTION INPUT ;
    USE SIGNAL ;
    PORT
      LAYER M4 ;
        RECT  0 34.992 0.084 35.016 ;
    END
  END li_d[69]
  PIN li_d[6]
    DIRECTION INPUT ;
    USE SIGNAL ;
    PORT
      LAYER M4 ;
        RECT  0 5.232 0.084 5.256 ;
    END
  END li_d[6]
  PIN li_d[70]
    DIRECTION INPUT ;
    USE SIGNAL ;
    PORT
      LAYER M4 ;
        RECT  0 35.472 0.084 35.496 ;
    END
  END li_d[70]
  PIN li_d[71]
    DIRECTION INPUT ;
    USE SIGNAL ;
    PORT
      LAYER M4 ;
        RECT  0 35.952 0.084 35.976 ;
    END
  END li_d[71]
  PIN li_d[72]
    DIRECTION INPUT ;
    USE SIGNAL ;
    PORT
      LAYER M4 ;
        RECT  0 36.432 0.084 36.456 ;
    END
  END li_d[72]
  PIN li_d[73]
    DIRECTION INPUT ;
    USE SIGNAL ;
    PORT
      LAYER M4 ;
        RECT  0 36.912 0.084 36.936 ;
    END
  END li_d[73]
  PIN li_d[74]
    DIRECTION INPUT ;
    USE SIGNAL ;
    PORT
      LAYER M4 ;
        RECT  0 37.392 0.084 37.416 ;
    END
  END li_d[74]
  PIN li_d[75]
    DIRECTION INPUT ;
    USE SIGNAL ;
    PORT
      LAYER M4 ;
        RECT  0 37.824 0.084 37.848 ;
    END
  END li_d[75]
  PIN li_d[76]
    DIRECTION INPUT ;
    USE SIGNAL ;
    PORT
      LAYER M4 ;
        RECT  0 38.304 0.084 38.328 ;
    END
  END li_d[76]
  PIN li_d[77]
    DIRECTION INPUT ;
    USE SIGNAL ;
    PORT
      LAYER M4 ;
        RECT  0 38.784 0.084 38.808 ;
    END
  END li_d[77]
  PIN li_d[78]
    DIRECTION INPUT ;
    USE SIGNAL ;
    PORT
      LAYER M4 ;
        RECT  0 39.264 0.084 39.288 ;
    END
  END li_d[78]
  PIN li_d[79]
    DIRECTION INPUT ;
    USE SIGNAL ;
    PORT
      LAYER M4 ;
        RECT  0 39.744 0.084 39.768 ;
    END
  END li_d[79]
  PIN li_d[7]
    DIRECTION INPUT ;
    USE SIGNAL ;
    PORT
      LAYER M4 ;
        RECT  0 5.712 0.084 5.736 ;
    END
  END li_d[7]
  PIN li_d[80]
    DIRECTION INPUT ;
    USE SIGNAL ;
    PORT
      LAYER M4 ;
        RECT  0 40.224 0.084 40.248 ;
    END
  END li_d[80]
  PIN li_d[81]
    DIRECTION INPUT ;
    USE SIGNAL ;
    PORT
      LAYER M4 ;
        RECT  0 40.656 0.084 40.68 ;
    END
  END li_d[81]
  PIN li_d[82]
    DIRECTION INPUT ;
    USE SIGNAL ;
    PORT
      LAYER M4 ;
        RECT  0 41.136 0.084 41.16 ;
    END
  END li_d[82]
  PIN li_d[83]
    DIRECTION INPUT ;
    USE SIGNAL ;
    PORT
      LAYER M4 ;
        RECT  0 41.616 0.084 41.64 ;
    END
  END li_d[83]
  PIN li_d[84]
    DIRECTION INPUT ;
    USE SIGNAL ;
    PORT
      LAYER M4 ;
        RECT  0 42.096 0.084 42.12 ;
    END
  END li_d[84]
  PIN li_d[85]
    DIRECTION INPUT ;
    USE SIGNAL ;
    PORT
      LAYER M4 ;
        RECT  0 42.576 0.084 42.6 ;
    END
  END li_d[85]
  PIN li_d[86]
    DIRECTION INPUT ;
    USE SIGNAL ;
    PORT
      LAYER M4 ;
        RECT  0 43.056 0.084 43.08 ;
    END
  END li_d[86]
  PIN li_d[87]
    DIRECTION INPUT ;
    USE SIGNAL ;
    PORT
      LAYER M4 ;
        RECT  0 43.536 0.084 43.56 ;
    END
  END li_d[87]
  PIN li_d[88]
    DIRECTION INPUT ;
    USE SIGNAL ;
    PORT
      LAYER M4 ;
        RECT  0 43.968 0.084 43.992 ;
    END
  END li_d[88]
  PIN li_d[89]
    DIRECTION INPUT ;
    USE SIGNAL ;
    PORT
      LAYER M4 ;
        RECT  0 44.448 0.084 44.472 ;
    END
  END li_d[89]
  PIN li_d[8]
    DIRECTION INPUT ;
    USE SIGNAL ;
    PORT
      LAYER M4 ;
        RECT  0 6.144 0.084 6.168 ;
    END
  END li_d[8]
  PIN li_d[90]
    DIRECTION INPUT ;
    USE SIGNAL ;
    PORT
      LAYER M4 ;
        RECT  0 44.928 0.084 44.952 ;
    END
  END li_d[90]
  PIN li_d[91]
    DIRECTION INPUT ;
    USE SIGNAL ;
    PORT
      LAYER M4 ;
        RECT  0 45.408 0.084 45.432 ;
    END
  END li_d[91]
  PIN li_d[92]
    DIRECTION INPUT ;
    USE SIGNAL ;
    PORT
      LAYER M4 ;
        RECT  0 45.888 0.084 45.912 ;
    END
  END li_d[92]
  PIN li_d[93]
    DIRECTION INPUT ;
    USE SIGNAL ;
    PORT
      LAYER M4 ;
        RECT  0 46.368 0.084 46.392 ;
    END
  END li_d[93]
  PIN li_d[94]
    DIRECTION INPUT ;
    USE SIGNAL ;
    PORT
      LAYER M4 ;
        RECT  0 46.8 0.084 46.824 ;
    END
  END li_d[94]
  PIN li_d[95]
    DIRECTION INPUT ;
    USE SIGNAL ;
    PORT
      LAYER M4 ;
        RECT  0 47.28 0.084 47.304 ;
    END
  END li_d[95]
  PIN li_d[96]
    DIRECTION INPUT ;
    USE SIGNAL ;
    PORT
      LAYER M4 ;
        RECT  0 47.76 0.084 47.784 ;
    END
  END li_d[96]
  PIN li_d[97]
    DIRECTION INPUT ;
    USE SIGNAL ;
    PORT
      LAYER M4 ;
        RECT  0 48.24 0.084 48.264 ;
    END
  END li_d[97]
  PIN li_d[98]
    DIRECTION INPUT ;
    USE SIGNAL ;
    PORT
      LAYER M4 ;
        RECT  0 48.72 0.084 48.744 ;
    END
  END li_d[98]
  PIN li_d[99]
    DIRECTION INPUT ;
    USE SIGNAL ;
    PORT
      LAYER M4 ;
        RECT  0 49.2 0.084 49.224 ;
    END
  END li_d[99]
  PIN li_d[9]
    DIRECTION INPUT ;
    USE SIGNAL ;
    PORT
      LAYER M4 ;
        RECT  0 6.624 0.084 6.648 ;
    END
  END li_d[9]
  PIN rx_d[0]
    DIRECTION OUTPUT ;
    USE SIGNAL ;
    PORT
      LAYER M4 ;
        RECT  86.316 2.4 86.4 2.424 ;
    END
  END rx_d[0]
  PIN rx_d[100]
    DIRECTION OUTPUT ;
    USE SIGNAL ;
    PORT
      LAYER M4 ;
        RECT  86.316 49.68 86.4 49.704 ;
    END
  END rx_d[100]
  PIN rx_d[101]
    DIRECTION OUTPUT ;
    USE SIGNAL ;
    PORT
      LAYER M4 ;
        RECT  86.316 50.112 86.4 50.136 ;
    END
  END rx_d[101]
  PIN rx_d[102]
    DIRECTION OUTPUT ;
    USE SIGNAL ;
    PORT
      LAYER M4 ;
        RECT  86.316 50.592 86.4 50.616 ;
    END
  END rx_d[102]
  PIN rx_d[103]
    DIRECTION OUTPUT ;
    USE SIGNAL ;
    PORT
      LAYER M4 ;
        RECT  86.316 51.072 86.4 51.096 ;
    END
  END rx_d[103]
  PIN rx_d[104]
    DIRECTION OUTPUT ;
    USE SIGNAL ;
    PORT
      LAYER M4 ;
        RECT  86.316 51.552 86.4 51.576 ;
    END
  END rx_d[104]
  PIN rx_d[105]
    DIRECTION OUTPUT ;
    USE SIGNAL ;
    PORT
      LAYER M4 ;
        RECT  86.316 52.032 86.4 52.056 ;
    END
  END rx_d[105]
  PIN rx_d[106]
    DIRECTION OUTPUT ;
    USE SIGNAL ;
    PORT
      LAYER M4 ;
        RECT  86.316 52.512 86.4 52.536 ;
    END
  END rx_d[106]
  PIN rx_d[107]
    DIRECTION OUTPUT ;
    USE SIGNAL ;
    PORT
      LAYER M4 ;
        RECT  86.316 52.992 86.4 53.016 ;
    END
  END rx_d[107]
  PIN rx_d[108]
    DIRECTION OUTPUT ;
    USE SIGNAL ;
    PORT
      LAYER M4 ;
        RECT  86.316 53.424 86.4 53.448 ;
    END
  END rx_d[108]
  PIN rx_d[109]
    DIRECTION OUTPUT ;
    USE SIGNAL ;
    PORT
      LAYER M4 ;
        RECT  86.316 53.904 86.4 53.928 ;
    END
  END rx_d[109]
  PIN rx_d[10]
    DIRECTION OUTPUT ;
    USE SIGNAL ;
    PORT
      LAYER M4 ;
        RECT  86.316 7.104 86.4 7.128 ;
    END
  END rx_d[10]
  PIN rx_d[110]
    DIRECTION OUTPUT ;
    USE SIGNAL ;
    PORT
      LAYER M4 ;
        RECT  86.316 54.384 86.4 54.408 ;
    END
  END rx_d[110]
  PIN rx_d[111]
    DIRECTION OUTPUT ;
    USE SIGNAL ;
    PORT
      LAYER M4 ;
        RECT  86.316 54.864 86.4 54.888 ;
    END
  END rx_d[111]
  PIN rx_d[112]
    DIRECTION OUTPUT ;
    USE SIGNAL ;
    PORT
      LAYER M4 ;
        RECT  86.316 55.344 86.4 55.368 ;
    END
  END rx_d[112]
  PIN rx_d[113]
    DIRECTION OUTPUT ;
    USE SIGNAL ;
    PORT
      LAYER M4 ;
        RECT  86.316 55.824 86.4 55.848 ;
    END
  END rx_d[113]
  PIN rx_d[114]
    DIRECTION OUTPUT ;
    USE SIGNAL ;
    PORT
      LAYER M4 ;
        RECT  86.316 56.256 86.4 56.28 ;
    END
  END rx_d[114]
  PIN rx_d[115]
    DIRECTION OUTPUT ;
    USE SIGNAL ;
    PORT
      LAYER M4 ;
        RECT  86.316 56.736 86.4 56.76 ;
    END
  END rx_d[115]
  PIN rx_d[116]
    DIRECTION OUTPUT ;
    USE SIGNAL ;
    PORT
      LAYER M4 ;
        RECT  86.316 57.216 86.4 57.24 ;
    END
  END rx_d[116]
  PIN rx_d[117]
    DIRECTION OUTPUT ;
    USE SIGNAL ;
    PORT
      LAYER M4 ;
        RECT  86.316 57.696 86.4 57.72 ;
    END
  END rx_d[117]
  PIN rx_d[118]
    DIRECTION OUTPUT ;
    USE SIGNAL ;
    PORT
      LAYER M4 ;
        RECT  86.316 58.176 86.4 58.2 ;
    END
  END rx_d[118]
  PIN rx_d[119]
    DIRECTION OUTPUT ;
    USE SIGNAL ;
    PORT
      LAYER M4 ;
        RECT  86.316 58.656 86.4 58.68 ;
    END
  END rx_d[119]
  PIN rx_d[11]
    DIRECTION OUTPUT ;
    USE SIGNAL ;
    PORT
      LAYER M4 ;
        RECT  86.316 7.584 86.4 7.608 ;
    END
  END rx_d[11]
  PIN rx_d[120]
    DIRECTION OUTPUT ;
    USE SIGNAL ;
    PORT
      LAYER M4 ;
        RECT  86.316 59.136 86.4 59.16 ;
    END
  END rx_d[120]
  PIN rx_d[121]
    DIRECTION OUTPUT ;
    USE SIGNAL ;
    PORT
      LAYER M4 ;
        RECT  86.316 59.568 86.4 59.592 ;
    END
  END rx_d[121]
  PIN rx_d[122]
    DIRECTION OUTPUT ;
    USE SIGNAL ;
    PORT
      LAYER M4 ;
        RECT  86.316 60.048 86.4 60.072 ;
    END
  END rx_d[122]
  PIN rx_d[123]
    DIRECTION OUTPUT ;
    USE SIGNAL ;
    PORT
      LAYER M4 ;
        RECT  86.316 60.528 86.4 60.552 ;
    END
  END rx_d[123]
  PIN rx_d[124]
    DIRECTION OUTPUT ;
    USE SIGNAL ;
    PORT
      LAYER M4 ;
        RECT  86.316 61.008 86.4 61.032 ;
    END
  END rx_d[124]
  PIN rx_d[125]
    DIRECTION OUTPUT ;
    USE SIGNAL ;
    PORT
      LAYER M4 ;
        RECT  86.316 61.488 86.4 61.512 ;
    END
  END rx_d[125]
  PIN rx_d[126]
    DIRECTION OUTPUT ;
    USE SIGNAL ;
    PORT
      LAYER M4 ;
        RECT  86.316 61.968 86.4 61.992 ;
    END
  END rx_d[126]
  PIN rx_d[127]
    DIRECTION OUTPUT ;
    USE SIGNAL ;
    PORT
      LAYER M4 ;
        RECT  86.316 62.448 86.4 62.472 ;
    END
  END rx_d[127]
  PIN rx_d[128]
    DIRECTION OUTPUT ;
    USE SIGNAL ;
    PORT
      LAYER M4 ;
        RECT  86.316 62.88 86.4 62.904 ;
    END
  END rx_d[128]
  PIN rx_d[129]
    DIRECTION OUTPUT ;
    USE SIGNAL ;
    PORT
      LAYER M4 ;
        RECT  86.316 63.36 86.4 63.384 ;
    END
  END rx_d[129]
  PIN rx_d[12]
    DIRECTION OUTPUT ;
    USE SIGNAL ;
    PORT
      LAYER M4 ;
        RECT  86.316 8.064 86.4 8.088 ;
    END
  END rx_d[12]
  PIN rx_d[130]
    DIRECTION OUTPUT ;
    USE SIGNAL ;
    PORT
      LAYER M4 ;
        RECT  86.316 63.84 86.4 63.864 ;
    END
  END rx_d[130]
  PIN rx_d[131]
    DIRECTION OUTPUT ;
    USE SIGNAL ;
    PORT
      LAYER M4 ;
        RECT  86.316 64.32 86.4 64.344 ;
    END
  END rx_d[131]
  PIN rx_d[132]
    DIRECTION OUTPUT ;
    USE SIGNAL ;
    PORT
      LAYER M4 ;
        RECT  86.316 64.8 86.4 64.824 ;
    END
  END rx_d[132]
  PIN rx_d[133]
    DIRECTION OUTPUT ;
    USE SIGNAL ;
    PORT
      LAYER M4 ;
        RECT  86.316 65.28 86.4 65.304 ;
    END
  END rx_d[133]
  PIN rx_d[134]
    DIRECTION OUTPUT ;
    USE SIGNAL ;
    PORT
      LAYER M4 ;
        RECT  86.316 65.712 86.4 65.736 ;
    END
  END rx_d[134]
  PIN rx_d[135]
    DIRECTION OUTPUT ;
    USE SIGNAL ;
    PORT
      LAYER M4 ;
        RECT  86.316 66.192 86.4 66.216 ;
    END
  END rx_d[135]
  PIN rx_d[136]
    DIRECTION OUTPUT ;
    USE SIGNAL ;
    PORT
      LAYER M4 ;
        RECT  86.316 66.672 86.4 66.696 ;
    END
  END rx_d[136]
  PIN rx_d[137]
    DIRECTION OUTPUT ;
    USE SIGNAL ;
    PORT
      LAYER M4 ;
        RECT  86.316 67.152 86.4 67.176 ;
    END
  END rx_d[137]
  PIN rx_d[138]
    DIRECTION OUTPUT ;
    USE SIGNAL ;
    PORT
      LAYER M4 ;
        RECT  86.316 67.632 86.4 67.656 ;
    END
  END rx_d[138]
  PIN rx_d[139]
    DIRECTION OUTPUT ;
    USE SIGNAL ;
    PORT
      LAYER M4 ;
        RECT  86.316 68.112 86.4 68.136 ;
    END
  END rx_d[139]
  PIN rx_d[13]
    DIRECTION OUTPUT ;
    USE SIGNAL ;
    PORT
      LAYER M4 ;
        RECT  86.316 8.544 86.4 8.568 ;
    END
  END rx_d[13]
  PIN rx_d[140]
    DIRECTION OUTPUT ;
    USE SIGNAL ;
    PORT
      LAYER M4 ;
        RECT  86.316 68.592 86.4 68.616 ;
    END
  END rx_d[140]
  PIN rx_d[141]
    DIRECTION OUTPUT ;
    USE SIGNAL ;
    PORT
      LAYER M4 ;
        RECT  86.316 69.024 86.4 69.048 ;
    END
  END rx_d[141]
  PIN rx_d[142]
    DIRECTION OUTPUT ;
    USE SIGNAL ;
    PORT
      LAYER M4 ;
        RECT  86.316 69.504 86.4 69.528 ;
    END
  END rx_d[142]
  PIN rx_d[143]
    DIRECTION OUTPUT ;
    USE SIGNAL ;
    PORT
      LAYER M4 ;
        RECT  86.316 69.984 86.4 70.008 ;
    END
  END rx_d[143]
  PIN rx_d[144]
    DIRECTION OUTPUT ;
    USE SIGNAL ;
    PORT
      LAYER M4 ;
        RECT  86.316 70.464 86.4 70.488 ;
    END
  END rx_d[144]
  PIN rx_d[145]
    DIRECTION OUTPUT ;
    USE SIGNAL ;
    PORT
      LAYER M4 ;
        RECT  86.316 70.944 86.4 70.968 ;
    END
  END rx_d[145]
  PIN rx_d[146]
    DIRECTION OUTPUT ;
    USE SIGNAL ;
    PORT
      LAYER M4 ;
        RECT  86.316 71.424 86.4 71.448 ;
    END
  END rx_d[146]
  PIN rx_d[147]
    DIRECTION OUTPUT ;
    USE SIGNAL ;
    PORT
      LAYER M4 ;
        RECT  86.316 71.856 86.4 71.88 ;
    END
  END rx_d[147]
  PIN rx_d[148]
    DIRECTION OUTPUT ;
    USE SIGNAL ;
    PORT
      LAYER M4 ;
        RECT  86.316 72.336 86.4 72.36 ;
    END
  END rx_d[148]
  PIN rx_d[149]
    DIRECTION OUTPUT ;
    USE SIGNAL ;
    PORT
      LAYER M4 ;
        RECT  86.316 72.816 86.4 72.84 ;
    END
  END rx_d[149]
  PIN rx_d[14]
    DIRECTION OUTPUT ;
    USE SIGNAL ;
    PORT
      LAYER M4 ;
        RECT  86.316 9.024 86.4 9.048 ;
    END
  END rx_d[14]
  PIN rx_d[150]
    DIRECTION OUTPUT ;
    USE SIGNAL ;
    PORT
      LAYER M4 ;
        RECT  86.316 73.296 86.4 73.32 ;
    END
  END rx_d[150]
  PIN rx_d[151]
    DIRECTION OUTPUT ;
    USE SIGNAL ;
    PORT
      LAYER M4 ;
        RECT  86.316 73.776 86.4 73.8 ;
    END
  END rx_d[151]
  PIN rx_d[152]
    DIRECTION OUTPUT ;
    USE SIGNAL ;
    PORT
      LAYER M4 ;
        RECT  86.316 74.256 86.4 74.28 ;
    END
  END rx_d[152]
  PIN rx_d[153]
    DIRECTION OUTPUT ;
    USE SIGNAL ;
    PORT
      LAYER M4 ;
        RECT  86.316 74.736 86.4 74.76 ;
    END
  END rx_d[153]
  PIN rx_d[154]
    DIRECTION OUTPUT ;
    USE SIGNAL ;
    PORT
      LAYER M4 ;
        RECT  86.316 75.168 86.4 75.192 ;
    END
  END rx_d[154]
  PIN rx_d[155]
    DIRECTION OUTPUT ;
    USE SIGNAL ;
    PORT
      LAYER M4 ;
        RECT  86.316 75.648 86.4 75.672 ;
    END
  END rx_d[155]
  PIN rx_d[156]
    DIRECTION OUTPUT ;
    USE SIGNAL ;
    PORT
      LAYER M4 ;
        RECT  86.316 76.128 86.4 76.152 ;
    END
  END rx_d[156]
  PIN rx_d[157]
    DIRECTION OUTPUT ;
    USE SIGNAL ;
    PORT
      LAYER M4 ;
        RECT  86.316 76.608 86.4 76.632 ;
    END
  END rx_d[157]
  PIN rx_d[158]
    DIRECTION OUTPUT ;
    USE SIGNAL ;
    PORT
      LAYER M4 ;
        RECT  86.316 77.088 86.4 77.112 ;
    END
  END rx_d[158]
  PIN rx_d[159]
    DIRECTION OUTPUT ;
    USE SIGNAL ;
    PORT
      LAYER M4 ;
        RECT  86.316 77.568 86.4 77.592 ;
    END
  END rx_d[159]
  PIN rx_d[15]
    DIRECTION OUTPUT ;
    USE SIGNAL ;
    PORT
      LAYER M4 ;
        RECT  86.316 9.456 86.4 9.48 ;
    END
  END rx_d[15]
  PIN rx_d[160]
    DIRECTION OUTPUT ;
    USE SIGNAL ;
    PORT
      LAYER M4 ;
        RECT  86.316 78.048 86.4 78.072 ;
    END
  END rx_d[160]
  PIN rx_d[161]
    DIRECTION OUTPUT ;
    USE SIGNAL ;
    PORT
      LAYER M4 ;
        RECT  86.316 78.48 86.4 78.504 ;
    END
  END rx_d[161]
  PIN rx_d[162]
    DIRECTION OUTPUT ;
    USE SIGNAL ;
    PORT
      LAYER M4 ;
        RECT  86.316 78.96 86.4 78.984 ;
    END
  END rx_d[162]
  PIN rx_d[163]
    DIRECTION OUTPUT ;
    USE SIGNAL ;
    PORT
      LAYER M4 ;
        RECT  86.316 79.44 86.4 79.464 ;
    END
  END rx_d[163]
  PIN rx_d[164]
    DIRECTION OUTPUT ;
    USE SIGNAL ;
    PORT
      LAYER M4 ;
        RECT  86.316 79.92 86.4 79.944 ;
    END
  END rx_d[164]
  PIN rx_d[165]
    DIRECTION OUTPUT ;
    USE SIGNAL ;
    PORT
      LAYER M4 ;
        RECT  86.316 80.4 86.4 80.424 ;
    END
  END rx_d[165]
  PIN rx_d[166]
    DIRECTION OUTPUT ;
    USE SIGNAL ;
    PORT
      LAYER M4 ;
        RECT  86.316 80.88 86.4 80.904 ;
    END
  END rx_d[166]
  PIN rx_d[167]
    DIRECTION OUTPUT ;
    USE SIGNAL ;
    PORT
      LAYER M4 ;
        RECT  86.316 81.312 86.4 81.336 ;
    END
  END rx_d[167]
  PIN rx_d[168]
    DIRECTION OUTPUT ;
    USE SIGNAL ;
    PORT
      LAYER M4 ;
        RECT  86.316 81.792 86.4 81.816 ;
    END
  END rx_d[168]
  PIN rx_d[169]
    DIRECTION OUTPUT ;
    USE SIGNAL ;
    PORT
      LAYER M4 ;
        RECT  86.316 82.272 86.4 82.296 ;
    END
  END rx_d[169]
  PIN rx_d[16]
    DIRECTION OUTPUT ;
    USE SIGNAL ;
    PORT
      LAYER M4 ;
        RECT  86.316 9.936 86.4 9.96 ;
    END
  END rx_d[16]
  PIN rx_d[170]
    DIRECTION OUTPUT ;
    USE SIGNAL ;
    PORT
      LAYER M4 ;
        RECT  86.316 82.752 86.4 82.776 ;
    END
  END rx_d[170]
  PIN rx_d[171]
    DIRECTION OUTPUT ;
    USE SIGNAL ;
    PORT
      LAYER M4 ;
        RECT  86.316 83.232 86.4 83.256 ;
    END
  END rx_d[171]
  PIN rx_d[172]
    DIRECTION OUTPUT ;
    USE SIGNAL ;
    PORT
      LAYER M4 ;
        RECT  86.316 83.712 86.4 83.736 ;
    END
  END rx_d[172]
  PIN rx_d[173]
    DIRECTION OUTPUT ;
    USE SIGNAL ;
    PORT
      LAYER M4 ;
        RECT  86.316 84.192 86.4 84.216 ;
    END
  END rx_d[173]
  PIN rx_d[174]
    DIRECTION OUTPUT ;
    USE SIGNAL ;
    PORT
      LAYER M4 ;
        RECT  86.316 84.624 86.4 84.648 ;
    END
  END rx_d[174]
  PIN rx_d[175]
    DIRECTION OUTPUT ;
    USE SIGNAL ;
    PORT
      LAYER M4 ;
        RECT  86.316 85.104 86.4 85.128 ;
    END
  END rx_d[175]
  PIN rx_d[176]
    DIRECTION OUTPUT ;
    USE SIGNAL ;
    PORT
      LAYER M4 ;
        RECT  86.316 85.584 86.4 85.608 ;
    END
  END rx_d[176]
  PIN rx_d[177]
    DIRECTION OUTPUT ;
    USE SIGNAL ;
    PORT
      LAYER M4 ;
        RECT  86.316 86.064 86.4 86.088 ;
    END
  END rx_d[177]
  PIN rx_d[178]
    DIRECTION OUTPUT ;
    USE SIGNAL ;
    PORT
      LAYER M4 ;
        RECT  86.316 86.544 86.4 86.568 ;
    END
  END rx_d[178]
  PIN rx_d[179]
    DIRECTION OUTPUT ;
    USE SIGNAL ;
    PORT
      LAYER M4 ;
        RECT  86.316 87.024 86.4 87.048 ;
    END
  END rx_d[179]
  PIN rx_d[17]
    DIRECTION OUTPUT ;
    USE SIGNAL ;
    PORT
      LAYER M4 ;
        RECT  86.316 10.416 86.4 10.44 ;
    END
  END rx_d[17]
  PIN rx_d[180]
    DIRECTION OUTPUT ;
    USE SIGNAL ;
    PORT
      LAYER M4 ;
        RECT  86.316 87.504 86.4 87.528 ;
    END
  END rx_d[180]
  PIN rx_d[181]
    DIRECTION OUTPUT ;
    USE SIGNAL ;
    PORT
      LAYER M4 ;
        RECT  86.316 87.936 86.4 87.96 ;
    END
  END rx_d[181]
  PIN rx_d[182]
    DIRECTION OUTPUT ;
    USE SIGNAL ;
    PORT
      LAYER M4 ;
        RECT  86.316 88.416 86.4 88.44 ;
    END
  END rx_d[182]
  PIN rx_d[183]
    DIRECTION OUTPUT ;
    USE SIGNAL ;
    PORT
      LAYER M4 ;
        RECT  86.316 88.896 86.4 88.92 ;
    END
  END rx_d[183]
  PIN rx_d[184]
    DIRECTION OUTPUT ;
    USE SIGNAL ;
    PORT
      LAYER M4 ;
        RECT  86.316 89.376 86.4 89.4 ;
    END
  END rx_d[184]
  PIN rx_d[185]
    DIRECTION OUTPUT ;
    USE SIGNAL ;
    PORT
      LAYER M4 ;
        RECT  86.316 89.856 86.4 89.88 ;
    END
  END rx_d[185]
  PIN rx_d[186]
    DIRECTION OUTPUT ;
    USE SIGNAL ;
    PORT
      LAYER M4 ;
        RECT  86.316 90.336 86.4 90.36 ;
    END
  END rx_d[186]
  PIN rx_d[187]
    DIRECTION OUTPUT ;
    USE SIGNAL ;
    PORT
      LAYER M4 ;
        RECT  86.316 90.768 86.4 90.792 ;
    END
  END rx_d[187]
  PIN rx_d[188]
    DIRECTION OUTPUT ;
    USE SIGNAL ;
    PORT
      LAYER M4 ;
        RECT  86.316 91.248 86.4 91.272 ;
    END
  END rx_d[188]
  PIN rx_d[189]
    DIRECTION OUTPUT ;
    USE SIGNAL ;
    PORT
      LAYER M4 ;
        RECT  86.316 91.728 86.4 91.752 ;
    END
  END rx_d[189]
  PIN rx_d[18]
    DIRECTION OUTPUT ;
    USE SIGNAL ;
    PORT
      LAYER M4 ;
        RECT  86.316 10.896 86.4 10.92 ;
    END
  END rx_d[18]
  PIN rx_d[190]
    DIRECTION OUTPUT ;
    USE SIGNAL ;
    PORT
      LAYER M4 ;
        RECT  86.316 92.208 86.4 92.232 ;
    END
  END rx_d[190]
  PIN rx_d[191]
    DIRECTION OUTPUT ;
    USE SIGNAL ;
    PORT
      LAYER M4 ;
        RECT  86.316 92.688 86.4 92.712 ;
    END
  END rx_d[191]
  PIN rx_d[192]
    DIRECTION OUTPUT ;
    USE SIGNAL ;
    PORT
      LAYER M4 ;
        RECT  86.316 93.168 86.4 93.192 ;
    END
  END rx_d[192]
  PIN rx_d[193]
    DIRECTION OUTPUT ;
    USE SIGNAL ;
    PORT
      LAYER M4 ;
        RECT  86.316 93.648 86.4 93.672 ;
    END
  END rx_d[193]
  PIN rx_d[194]
    DIRECTION OUTPUT ;
    USE SIGNAL ;
    PORT
      LAYER M4 ;
        RECT  86.316 94.08 86.4 94.104 ;
    END
  END rx_d[194]
  PIN rx_d[195]
    DIRECTION OUTPUT ;
    USE SIGNAL ;
    PORT
      LAYER M4 ;
        RECT  86.316 94.56 86.4 94.584 ;
    END
  END rx_d[195]
  PIN rx_d[196]
    DIRECTION OUTPUT ;
    USE SIGNAL ;
    PORT
      LAYER M4 ;
        RECT  86.316 95.04 86.4 95.064 ;
    END
  END rx_d[196]
  PIN rx_d[197]
    DIRECTION OUTPUT ;
    USE SIGNAL ;
    PORT
      LAYER M4 ;
        RECT  86.316 95.52 86.4 95.544 ;
    END
  END rx_d[197]
  PIN rx_d[198]
    DIRECTION OUTPUT ;
    USE SIGNAL ;
    PORT
      LAYER M4 ;
        RECT  86.316 96 86.4 96.024 ;
    END
  END rx_d[198]
  PIN rx_d[199]
    DIRECTION OUTPUT ;
    USE SIGNAL ;
    PORT
      LAYER M4 ;
        RECT  86.316 96.48 86.4 96.504 ;
    END
  END rx_d[199]
  PIN rx_d[19]
    DIRECTION OUTPUT ;
    USE SIGNAL ;
    PORT
      LAYER M4 ;
        RECT  86.316 11.376 86.4 11.4 ;
    END
  END rx_d[19]
  PIN rx_d[1]
    DIRECTION OUTPUT ;
    USE SIGNAL ;
    PORT
      LAYER M4 ;
        RECT  86.316 2.88 86.4 2.904 ;
    END
  END rx_d[1]
  PIN rx_d[200]
    DIRECTION OUTPUT ;
    USE SIGNAL ;
    PORT
      LAYER M4 ;
        RECT  86.316 96.912 86.4 96.936 ;
    END
  END rx_d[200]
  PIN rx_d[201]
    DIRECTION OUTPUT ;
    USE SIGNAL ;
    PORT
      LAYER M4 ;
        RECT  86.316 97.392 86.4 97.416 ;
    END
  END rx_d[201]
  PIN rx_d[202]
    DIRECTION OUTPUT ;
    USE SIGNAL ;
    PORT
      LAYER M4 ;
        RECT  86.316 97.872 86.4 97.896 ;
    END
  END rx_d[202]
  PIN rx_d[203]
    DIRECTION OUTPUT ;
    USE SIGNAL ;
    PORT
      LAYER M4 ;
        RECT  86.316 98.352 86.4 98.376 ;
    END
  END rx_d[203]
  PIN rx_d[204]
    DIRECTION OUTPUT ;
    USE SIGNAL ;
    PORT
      LAYER M4 ;
        RECT  86.316 98.832 86.4 98.856 ;
    END
  END rx_d[204]
  PIN rx_d[205]
    DIRECTION OUTPUT ;
    USE SIGNAL ;
    PORT
      LAYER M4 ;
        RECT  86.316 99.312 86.4 99.336 ;
    END
  END rx_d[205]
  PIN rx_d[206]
    DIRECTION OUTPUT ;
    USE SIGNAL ;
    PORT
      LAYER M4 ;
        RECT  86.316 99.792 86.4 99.816 ;
    END
  END rx_d[206]
  PIN rx_d[207]
    DIRECTION OUTPUT ;
    USE SIGNAL ;
    PORT
      LAYER M4 ;
        RECT  86.316 100.224 86.4 100.248 ;
    END
  END rx_d[207]
  PIN rx_d[208]
    DIRECTION OUTPUT ;
    USE SIGNAL ;
    PORT
      LAYER M4 ;
        RECT  86.316 100.704 86.4 100.728 ;
    END
  END rx_d[208]
  PIN rx_d[209]
    DIRECTION OUTPUT ;
    USE SIGNAL ;
    PORT
      LAYER M4 ;
        RECT  86.316 101.184 86.4 101.208 ;
    END
  END rx_d[209]
  PIN rx_d[20]
    DIRECTION OUTPUT ;
    USE SIGNAL ;
    PORT
      LAYER M4 ;
        RECT  86.316 11.856 86.4 11.88 ;
    END
  END rx_d[20]
  PIN rx_d[210]
    DIRECTION OUTPUT ;
    USE SIGNAL ;
    PORT
      LAYER M4 ;
        RECT  86.316 101.664 86.4 101.688 ;
    END
  END rx_d[210]
  PIN rx_d[211]
    DIRECTION OUTPUT ;
    USE SIGNAL ;
    PORT
      LAYER M4 ;
        RECT  86.316 102.144 86.4 102.168 ;
    END
  END rx_d[211]
  PIN rx_d[212]
    DIRECTION OUTPUT ;
    USE SIGNAL ;
    PORT
      LAYER M4 ;
        RECT  86.316 102.624 86.4 102.648 ;
    END
  END rx_d[212]
  PIN rx_d[213]
    DIRECTION OUTPUT ;
    USE SIGNAL ;
    PORT
      LAYER M4 ;
        RECT  86.316 103.104 86.4 103.128 ;
    END
  END rx_d[213]
  PIN rx_d[214]
    DIRECTION OUTPUT ;
    USE SIGNAL ;
    PORT
      LAYER M4 ;
        RECT  86.316 103.536 86.4 103.56 ;
    END
  END rx_d[214]
  PIN rx_d[215]
    DIRECTION OUTPUT ;
    USE SIGNAL ;
    PORT
      LAYER M4 ;
        RECT  86.316 104.016 86.4 104.04 ;
    END
  END rx_d[215]
  PIN rx_d[216]
    DIRECTION OUTPUT ;
    USE SIGNAL ;
    PORT
      LAYER M4 ;
        RECT  86.316 104.496 86.4 104.52 ;
    END
  END rx_d[216]
  PIN rx_d[217]
    DIRECTION OUTPUT ;
    USE SIGNAL ;
    PORT
      LAYER M4 ;
        RECT  86.316 104.976 86.4 105 ;
    END
  END rx_d[217]
  PIN rx_d[218]
    DIRECTION OUTPUT ;
    USE SIGNAL ;
    PORT
      LAYER M4 ;
        RECT  86.316 105.456 86.4 105.48 ;
    END
  END rx_d[218]
  PIN rx_d[219]
    DIRECTION OUTPUT ;
    USE SIGNAL ;
    PORT
      LAYER M4 ;
        RECT  86.316 105.936 86.4 105.96 ;
    END
  END rx_d[219]
  PIN rx_d[21]
    DIRECTION OUTPUT ;
    USE SIGNAL ;
    PORT
      LAYER M4 ;
        RECT  86.316 12.336 86.4 12.36 ;
    END
  END rx_d[21]
  PIN rx_d[220]
    DIRECTION OUTPUT ;
    USE SIGNAL ;
    PORT
      LAYER M4 ;
        RECT  86.316 106.368 86.4 106.392 ;
    END
  END rx_d[220]
  PIN rx_d[221]
    DIRECTION OUTPUT ;
    USE SIGNAL ;
    PORT
      LAYER M4 ;
        RECT  86.316 106.848 86.4 106.872 ;
    END
  END rx_d[221]
  PIN rx_d[222]
    DIRECTION OUTPUT ;
    USE SIGNAL ;
    PORT
      LAYER M4 ;
        RECT  86.316 107.328 86.4 107.352 ;
    END
  END rx_d[222]
  PIN rx_d[223]
    DIRECTION OUTPUT ;
    USE SIGNAL ;
    PORT
      LAYER M4 ;
        RECT  86.316 107.808 86.4 107.832 ;
    END
  END rx_d[223]
  PIN rx_d[224]
    DIRECTION OUTPUT ;
    USE SIGNAL ;
    PORT
      LAYER M4 ;
        RECT  86.316 108.288 86.4 108.312 ;
    END
  END rx_d[224]
  PIN rx_d[225]
    DIRECTION OUTPUT ;
    USE SIGNAL ;
    PORT
      LAYER M4 ;
        RECT  86.316 108.768 86.4 108.792 ;
    END
  END rx_d[225]
  PIN rx_d[226]
    DIRECTION OUTPUT ;
    USE SIGNAL ;
    PORT
      LAYER M4 ;
        RECT  86.316 109.248 86.4 109.272 ;
    END
  END rx_d[226]
  PIN rx_d[227]
    DIRECTION OUTPUT ;
    USE SIGNAL ;
    PORT
      LAYER M4 ;
        RECT  86.316 109.68 86.4 109.704 ;
    END
  END rx_d[227]
  PIN rx_d[228]
    DIRECTION OUTPUT ;
    USE SIGNAL ;
    PORT
      LAYER M4 ;
        RECT  86.316 110.16 86.4 110.184 ;
    END
  END rx_d[228]
  PIN rx_d[229]
    DIRECTION OUTPUT ;
    USE SIGNAL ;
    PORT
      LAYER M4 ;
        RECT  86.316 110.64 86.4 110.664 ;
    END
  END rx_d[229]
  PIN rx_d[22]
    DIRECTION OUTPUT ;
    USE SIGNAL ;
    PORT
      LAYER M4 ;
        RECT  86.316 12.768 86.4 12.792 ;
    END
  END rx_d[22]
  PIN rx_d[230]
    DIRECTION OUTPUT ;
    USE SIGNAL ;
    PORT
      LAYER M4 ;
        RECT  86.316 111.12 86.4 111.144 ;
    END
  END rx_d[230]
  PIN rx_d[231]
    DIRECTION OUTPUT ;
    USE SIGNAL ;
    PORT
      LAYER M4 ;
        RECT  86.316 111.6 86.4 111.624 ;
    END
  END rx_d[231]
  PIN rx_d[232]
    DIRECTION OUTPUT ;
    USE SIGNAL ;
    PORT
      LAYER M4 ;
        RECT  86.316 112.08 86.4 112.104 ;
    END
  END rx_d[232]
  PIN rx_d[233]
    DIRECTION OUTPUT ;
    USE SIGNAL ;
    PORT
      LAYER M4 ;
        RECT  86.316 112.56 86.4 112.584 ;
    END
  END rx_d[233]
  PIN rx_d[234]
    DIRECTION OUTPUT ;
    USE SIGNAL ;
    PORT
      LAYER M4 ;
        RECT  86.316 112.992 86.4 113.016 ;
    END
  END rx_d[234]
  PIN rx_d[235]
    DIRECTION OUTPUT ;
    USE SIGNAL ;
    PORT
      LAYER M4 ;
        RECT  86.316 113.472 86.4 113.496 ;
    END
  END rx_d[235]
  PIN rx_d[236]
    DIRECTION OUTPUT ;
    USE SIGNAL ;
    PORT
      LAYER M4 ;
        RECT  86.316 113.952 86.4 113.976 ;
    END
  END rx_d[236]
  PIN rx_d[237]
    DIRECTION OUTPUT ;
    USE SIGNAL ;
    PORT
      LAYER M4 ;
        RECT  86.316 114.432 86.4 114.456 ;
    END
  END rx_d[237]
  PIN rx_d[238]
    DIRECTION OUTPUT ;
    USE SIGNAL ;
    PORT
      LAYER M4 ;
        RECT  86.316 114.912 86.4 114.936 ;
    END
  END rx_d[238]
  PIN rx_d[239]
    DIRECTION OUTPUT ;
    USE SIGNAL ;
    PORT
      LAYER M4 ;
        RECT  86.316 115.392 86.4 115.416 ;
    END
  END rx_d[239]
  PIN rx_d[23]
    DIRECTION OUTPUT ;
    USE SIGNAL ;
    PORT
      LAYER M4 ;
        RECT  86.316 13.248 86.4 13.272 ;
    END
  END rx_d[23]
  PIN rx_d[240]
    DIRECTION OUTPUT ;
    USE SIGNAL ;
    PORT
      LAYER M4 ;
        RECT  86.316 115.824 86.4 115.848 ;
    END
  END rx_d[240]
  PIN rx_d[241]
    DIRECTION OUTPUT ;
    USE SIGNAL ;
    PORT
      LAYER M4 ;
        RECT  86.316 116.304 86.4 116.328 ;
    END
  END rx_d[241]
  PIN rx_d[242]
    DIRECTION OUTPUT ;
    USE SIGNAL ;
    PORT
      LAYER M4 ;
        RECT  86.316 116.784 86.4 116.808 ;
    END
  END rx_d[242]
  PIN rx_d[243]
    DIRECTION OUTPUT ;
    USE SIGNAL ;
    PORT
      LAYER M4 ;
        RECT  86.316 117.264 86.4 117.288 ;
    END
  END rx_d[243]
  PIN rx_d[244]
    DIRECTION OUTPUT ;
    USE SIGNAL ;
    PORT
      LAYER M4 ;
        RECT  86.316 117.744 86.4 117.768 ;
    END
  END rx_d[244]
  PIN rx_d[245]
    DIRECTION OUTPUT ;
    USE SIGNAL ;
    PORT
      LAYER M4 ;
        RECT  86.316 118.224 86.4 118.248 ;
    END
  END rx_d[245]
  PIN rx_d[246]
    DIRECTION OUTPUT ;
    USE SIGNAL ;
    PORT
      LAYER M4 ;
        RECT  86.316 118.704 86.4 118.728 ;
    END
  END rx_d[246]
  PIN rx_d[247]
    DIRECTION OUTPUT ;
    USE SIGNAL ;
    PORT
      LAYER M4 ;
        RECT  86.316 119.136 86.4 119.16 ;
    END
  END rx_d[247]
  PIN rx_d[248]
    DIRECTION OUTPUT ;
    USE SIGNAL ;
    PORT
      LAYER M4 ;
        RECT  86.316 119.616 86.4 119.64 ;
    END
  END rx_d[248]
  PIN rx_d[249]
    DIRECTION OUTPUT ;
    USE SIGNAL ;
    PORT
      LAYER M4 ;
        RECT  86.316 120.096 86.4 120.12 ;
    END
  END rx_d[249]
  PIN rx_d[24]
    DIRECTION OUTPUT ;
    USE SIGNAL ;
    PORT
      LAYER M4 ;
        RECT  86.316 13.728 86.4 13.752 ;
    END
  END rx_d[24]
  PIN rx_d[250]
    DIRECTION OUTPUT ;
    USE SIGNAL ;
    PORT
      LAYER M4 ;
        RECT  86.316 120.576 86.4 120.6 ;
    END
  END rx_d[250]
  PIN rx_d[251]
    DIRECTION OUTPUT ;
    USE SIGNAL ;
    PORT
      LAYER M4 ;
        RECT  86.316 121.056 86.4 121.08 ;
    END
  END rx_d[251]
  PIN rx_d[252]
    DIRECTION OUTPUT ;
    USE SIGNAL ;
    PORT
      LAYER M4 ;
        RECT  86.316 121.536 86.4 121.56 ;
    END
  END rx_d[252]
  PIN rx_d[253]
    DIRECTION OUTPUT ;
    USE SIGNAL ;
    PORT
      LAYER M4 ;
        RECT  86.316 121.968 86.4 121.992 ;
    END
  END rx_d[253]
  PIN rx_d[254]
    DIRECTION OUTPUT ;
    USE SIGNAL ;
    PORT
      LAYER M4 ;
        RECT  86.316 122.448 86.4 122.472 ;
    END
  END rx_d[254]
  PIN rx_d[255]
    DIRECTION OUTPUT ;
    USE SIGNAL ;
    PORT
      LAYER M4 ;
        RECT  86.316 122.928 86.4 122.952 ;
    END
  END rx_d[255]
  PIN rx_d[256]
    DIRECTION OUTPUT ;
    USE SIGNAL ;
    PORT
      LAYER M4 ;
        RECT  86.316 123.408 86.4 123.432 ;
    END
  END rx_d[256]
  PIN rx_d[257]
    DIRECTION OUTPUT ;
    USE SIGNAL ;
    PORT
      LAYER M4 ;
        RECT  86.316 123.888 86.4 123.912 ;
    END
  END rx_d[257]
  PIN rx_d[258]
    DIRECTION OUTPUT ;
    USE SIGNAL ;
    PORT
      LAYER M4 ;
        RECT  86.316 124.368 86.4 124.392 ;
    END
  END rx_d[258]
  PIN rx_d[259]
    DIRECTION OUTPUT ;
    USE SIGNAL ;
    PORT
      LAYER M4 ;
        RECT  86.316 124.848 86.4 124.872 ;
    END
  END rx_d[259]
  PIN rx_d[25]
    DIRECTION OUTPUT ;
    USE SIGNAL ;
    PORT
      LAYER M4 ;
        RECT  86.316 14.208 86.4 14.232 ;
    END
  END rx_d[25]
  PIN rx_d[260]
    DIRECTION OUTPUT ;
    USE SIGNAL ;
    PORT
      LAYER M4 ;
        RECT  86.316 125.28 86.4 125.304 ;
    END
  END rx_d[260]
  PIN rx_d[261]
    DIRECTION OUTPUT ;
    USE SIGNAL ;
    PORT
      LAYER M4 ;
        RECT  86.316 125.76 86.4 125.784 ;
    END
  END rx_d[261]
  PIN rx_d[262]
    DIRECTION OUTPUT ;
    USE SIGNAL ;
    PORT
      LAYER M4 ;
        RECT  86.316 126.24 86.4 126.264 ;
    END
  END rx_d[262]
  PIN rx_d[263]
    DIRECTION OUTPUT ;
    USE SIGNAL ;
    PORT
      LAYER M4 ;
        RECT  86.316 126.72 86.4 126.744 ;
    END
  END rx_d[263]
  PIN rx_d[264]
    DIRECTION OUTPUT ;
    USE SIGNAL ;
    PORT
      LAYER M4 ;
        RECT  86.316 127.2 86.4 127.224 ;
    END
  END rx_d[264]
  PIN rx_d[26]
    DIRECTION OUTPUT ;
    USE SIGNAL ;
    PORT
      LAYER M4 ;
        RECT  86.316 14.688 86.4 14.712 ;
    END
  END rx_d[26]
  PIN rx_d[27]
    DIRECTION OUTPUT ;
    USE SIGNAL ;
    PORT
      LAYER M4 ;
        RECT  86.316 15.168 86.4 15.192 ;
    END
  END rx_d[27]
  PIN rx_d[28]
    DIRECTION OUTPUT ;
    USE SIGNAL ;
    PORT
      LAYER M4 ;
        RECT  86.316 15.6 86.4 15.624 ;
    END
  END rx_d[28]
  PIN rx_d[29]
    DIRECTION OUTPUT ;
    USE SIGNAL ;
    PORT
      LAYER M4 ;
        RECT  86.316 16.08 86.4 16.104 ;
    END
  END rx_d[29]
  PIN rx_d[2]
    DIRECTION OUTPUT ;
    USE SIGNAL ;
    PORT
      LAYER M4 ;
        RECT  86.316 3.312 86.4 3.336 ;
    END
  END rx_d[2]
  PIN rx_d[30]
    DIRECTION OUTPUT ;
    USE SIGNAL ;
    PORT
      LAYER M4 ;
        RECT  86.316 16.56 86.4 16.584 ;
    END
  END rx_d[30]
  PIN rx_d[31]
    DIRECTION OUTPUT ;
    USE SIGNAL ;
    PORT
      LAYER M4 ;
        RECT  86.316 17.04 86.4 17.064 ;
    END
  END rx_d[31]
  PIN rx_d[32]
    DIRECTION OUTPUT ;
    USE SIGNAL ;
    PORT
      LAYER M4 ;
        RECT  86.316 17.52 86.4 17.544 ;
    END
  END rx_d[32]
  PIN rx_d[33]
    DIRECTION OUTPUT ;
    USE SIGNAL ;
    PORT
      LAYER M4 ;
        RECT  86.316 18 86.4 18.024 ;
    END
  END rx_d[33]
  PIN rx_d[34]
    DIRECTION OUTPUT ;
    USE SIGNAL ;
    PORT
      LAYER M4 ;
        RECT  86.316 18.48 86.4 18.504 ;
    END
  END rx_d[34]
  PIN rx_d[35]
    DIRECTION OUTPUT ;
    USE SIGNAL ;
    PORT
      LAYER M4 ;
        RECT  86.316 18.912 86.4 18.936 ;
    END
  END rx_d[35]
  PIN rx_d[36]
    DIRECTION OUTPUT ;
    USE SIGNAL ;
    PORT
      LAYER M4 ;
        RECT  86.316 19.392 86.4 19.416 ;
    END
  END rx_d[36]
  PIN rx_d[37]
    DIRECTION OUTPUT ;
    USE SIGNAL ;
    PORT
      LAYER M4 ;
        RECT  86.316 19.872 86.4 19.896 ;
    END
  END rx_d[37]
  PIN rx_d[38]
    DIRECTION OUTPUT ;
    USE SIGNAL ;
    PORT
      LAYER M4 ;
        RECT  86.316 20.352 86.4 20.376 ;
    END
  END rx_d[38]
  PIN rx_d[39]
    DIRECTION OUTPUT ;
    USE SIGNAL ;
    PORT
      LAYER M4 ;
        RECT  86.316 20.832 86.4 20.856 ;
    END
  END rx_d[39]
  PIN rx_d[3]
    DIRECTION OUTPUT ;
    USE SIGNAL ;
    PORT
      LAYER M4 ;
        RECT  86.316 3.792 86.4 3.816 ;
    END
  END rx_d[3]
  PIN rx_d[40]
    DIRECTION OUTPUT ;
    USE SIGNAL ;
    PORT
      LAYER M4 ;
        RECT  86.316 21.312 86.4 21.336 ;
    END
  END rx_d[40]
  PIN rx_d[41]
    DIRECTION OUTPUT ;
    USE SIGNAL ;
    PORT
      LAYER M4 ;
        RECT  86.316 21.744 86.4 21.768 ;
    END
  END rx_d[41]
  PIN rx_d[42]
    DIRECTION OUTPUT ;
    USE SIGNAL ;
    PORT
      LAYER M4 ;
        RECT  86.316 22.224 86.4 22.248 ;
    END
  END rx_d[42]
  PIN rx_d[43]
    DIRECTION OUTPUT ;
    USE SIGNAL ;
    PORT
      LAYER M4 ;
        RECT  86.316 22.704 86.4 22.728 ;
    END
  END rx_d[43]
  PIN rx_d[44]
    DIRECTION OUTPUT ;
    USE SIGNAL ;
    PORT
      LAYER M4 ;
        RECT  86.316 23.184 86.4 23.208 ;
    END
  END rx_d[44]
  PIN rx_d[45]
    DIRECTION OUTPUT ;
    USE SIGNAL ;
    PORT
      LAYER M4 ;
        RECT  86.316 23.664 86.4 23.688 ;
    END
  END rx_d[45]
  PIN rx_d[46]
    DIRECTION OUTPUT ;
    USE SIGNAL ;
    PORT
      LAYER M4 ;
        RECT  86.316 24.144 86.4 24.168 ;
    END
  END rx_d[46]
  PIN rx_d[47]
    DIRECTION OUTPUT ;
    USE SIGNAL ;
    PORT
      LAYER M4 ;
        RECT  86.316 24.624 86.4 24.648 ;
    END
  END rx_d[47]
  PIN rx_d[48]
    DIRECTION OUTPUT ;
    USE SIGNAL ;
    PORT
      LAYER M4 ;
        RECT  86.316 25.056 86.4 25.08 ;
    END
  END rx_d[48]
  PIN rx_d[49]
    DIRECTION OUTPUT ;
    USE SIGNAL ;
    PORT
      LAYER M4 ;
        RECT  86.316 25.536 86.4 25.56 ;
    END
  END rx_d[49]
  PIN rx_d[4]
    DIRECTION OUTPUT ;
    USE SIGNAL ;
    PORT
      LAYER M4 ;
        RECT  86.316 4.272 86.4 4.296 ;
    END
  END rx_d[4]
  PIN rx_d[50]
    DIRECTION OUTPUT ;
    USE SIGNAL ;
    PORT
      LAYER M4 ;
        RECT  86.316 26.016 86.4 26.04 ;
    END
  END rx_d[50]
  PIN rx_d[51]
    DIRECTION OUTPUT ;
    USE SIGNAL ;
    PORT
      LAYER M4 ;
        RECT  86.316 26.496 86.4 26.52 ;
    END
  END rx_d[51]
  PIN rx_d[52]
    DIRECTION OUTPUT ;
    USE SIGNAL ;
    PORT
      LAYER M4 ;
        RECT  86.316 26.976 86.4 27 ;
    END
  END rx_d[52]
  PIN rx_d[53]
    DIRECTION OUTPUT ;
    USE SIGNAL ;
    PORT
      LAYER M4 ;
        RECT  86.316 27.456 86.4 27.48 ;
    END
  END rx_d[53]
  PIN rx_d[54]
    DIRECTION OUTPUT ;
    USE SIGNAL ;
    PORT
      LAYER M4 ;
        RECT  86.316 27.936 86.4 27.96 ;
    END
  END rx_d[54]
  PIN rx_d[55]
    DIRECTION OUTPUT ;
    USE SIGNAL ;
    PORT
      LAYER M4 ;
        RECT  86.316 28.368 86.4 28.392 ;
    END
  END rx_d[55]
  PIN rx_d[56]
    DIRECTION OUTPUT ;
    USE SIGNAL ;
    PORT
      LAYER M4 ;
        RECT  86.316 28.848 86.4 28.872 ;
    END
  END rx_d[56]
  PIN rx_d[57]
    DIRECTION OUTPUT ;
    USE SIGNAL ;
    PORT
      LAYER M4 ;
        RECT  86.316 29.328 86.4 29.352 ;
    END
  END rx_d[57]
  PIN rx_d[58]
    DIRECTION OUTPUT ;
    USE SIGNAL ;
    PORT
      LAYER M4 ;
        RECT  86.316 29.808 86.4 29.832 ;
    END
  END rx_d[58]
  PIN rx_d[59]
    DIRECTION OUTPUT ;
    USE SIGNAL ;
    PORT
      LAYER M4 ;
        RECT  86.316 30.288 86.4 30.312 ;
    END
  END rx_d[59]
  PIN rx_d[5]
    DIRECTION OUTPUT ;
    USE SIGNAL ;
    PORT
      LAYER M4 ;
        RECT  86.316 4.752 86.4 4.776 ;
    END
  END rx_d[5]
  PIN rx_d[60]
    DIRECTION OUTPUT ;
    USE SIGNAL ;
    PORT
      LAYER M4 ;
        RECT  86.316 30.768 86.4 30.792 ;
    END
  END rx_d[60]
  PIN rx_d[61]
    DIRECTION OUTPUT ;
    USE SIGNAL ;
    PORT
      LAYER M4 ;
        RECT  86.316 31.2 86.4 31.224 ;
    END
  END rx_d[61]
  PIN rx_d[62]
    DIRECTION OUTPUT ;
    USE SIGNAL ;
    PORT
      LAYER M4 ;
        RECT  86.316 31.68 86.4 31.704 ;
    END
  END rx_d[62]
  PIN rx_d[63]
    DIRECTION OUTPUT ;
    USE SIGNAL ;
    PORT
      LAYER M4 ;
        RECT  86.316 32.16 86.4 32.184 ;
    END
  END rx_d[63]
  PIN rx_d[64]
    DIRECTION OUTPUT ;
    USE SIGNAL ;
    PORT
      LAYER M4 ;
        RECT  86.316 32.64 86.4 32.664 ;
    END
  END rx_d[64]
  PIN rx_d[65]
    DIRECTION OUTPUT ;
    USE SIGNAL ;
    PORT
      LAYER M4 ;
        RECT  86.316 33.12 86.4 33.144 ;
    END
  END rx_d[65]
  PIN rx_d[66]
    DIRECTION OUTPUT ;
    USE SIGNAL ;
    PORT
      LAYER M4 ;
        RECT  86.316 33.6 86.4 33.624 ;
    END
  END rx_d[66]
  PIN rx_d[67]
    DIRECTION OUTPUT ;
    USE SIGNAL ;
    PORT
      LAYER M4 ;
        RECT  86.316 34.08 86.4 34.104 ;
    END
  END rx_d[67]
  PIN rx_d[68]
    DIRECTION OUTPUT ;
    USE SIGNAL ;
    PORT
      LAYER M4 ;
        RECT  86.316 34.512 86.4 34.536 ;
    END
  END rx_d[68]
  PIN rx_d[69]
    DIRECTION OUTPUT ;
    USE SIGNAL ;
    PORT
      LAYER M4 ;
        RECT  86.316 34.992 86.4 35.016 ;
    END
  END rx_d[69]
  PIN rx_d[6]
    DIRECTION OUTPUT ;
    USE SIGNAL ;
    PORT
      LAYER M4 ;
        RECT  86.316 5.232 86.4 5.256 ;
    END
  END rx_d[6]
  PIN rx_d[70]
    DIRECTION OUTPUT ;
    USE SIGNAL ;
    PORT
      LAYER M4 ;
        RECT  86.316 35.472 86.4 35.496 ;
    END
  END rx_d[70]
  PIN rx_d[71]
    DIRECTION OUTPUT ;
    USE SIGNAL ;
    PORT
      LAYER M4 ;
        RECT  86.316 35.952 86.4 35.976 ;
    END
  END rx_d[71]
  PIN rx_d[72]
    DIRECTION OUTPUT ;
    USE SIGNAL ;
    PORT
      LAYER M4 ;
        RECT  86.316 36.432 86.4 36.456 ;
    END
  END rx_d[72]
  PIN rx_d[73]
    DIRECTION OUTPUT ;
    USE SIGNAL ;
    PORT
      LAYER M4 ;
        RECT  86.316 36.912 86.4 36.936 ;
    END
  END rx_d[73]
  PIN rx_d[74]
    DIRECTION OUTPUT ;
    USE SIGNAL ;
    PORT
      LAYER M4 ;
        RECT  86.316 37.392 86.4 37.416 ;
    END
  END rx_d[74]
  PIN rx_d[75]
    DIRECTION OUTPUT ;
    USE SIGNAL ;
    PORT
      LAYER M4 ;
        RECT  86.316 37.824 86.4 37.848 ;
    END
  END rx_d[75]
  PIN rx_d[76]
    DIRECTION OUTPUT ;
    USE SIGNAL ;
    PORT
      LAYER M4 ;
        RECT  86.316 38.304 86.4 38.328 ;
    END
  END rx_d[76]
  PIN rx_d[77]
    DIRECTION OUTPUT ;
    USE SIGNAL ;
    PORT
      LAYER M4 ;
        RECT  86.316 38.784 86.4 38.808 ;
    END
  END rx_d[77]
  PIN rx_d[78]
    DIRECTION OUTPUT ;
    USE SIGNAL ;
    PORT
      LAYER M4 ;
        RECT  86.316 39.264 86.4 39.288 ;
    END
  END rx_d[78]
  PIN rx_d[79]
    DIRECTION OUTPUT ;
    USE SIGNAL ;
    PORT
      LAYER M4 ;
        RECT  86.316 39.744 86.4 39.768 ;
    END
  END rx_d[79]
  PIN rx_d[7]
    DIRECTION OUTPUT ;
    USE SIGNAL ;
    PORT
      LAYER M4 ;
        RECT  86.316 5.712 86.4 5.736 ;
    END
  END rx_d[7]
  PIN rx_d[80]
    DIRECTION OUTPUT ;
    USE SIGNAL ;
    PORT
      LAYER M4 ;
        RECT  86.316 40.224 86.4 40.248 ;
    END
  END rx_d[80]
  PIN rx_d[81]
    DIRECTION OUTPUT ;
    USE SIGNAL ;
    PORT
      LAYER M4 ;
        RECT  86.316 40.656 86.4 40.68 ;
    END
  END rx_d[81]
  PIN rx_d[82]
    DIRECTION OUTPUT ;
    USE SIGNAL ;
    PORT
      LAYER M4 ;
        RECT  86.316 41.136 86.4 41.16 ;
    END
  END rx_d[82]
  PIN rx_d[83]
    DIRECTION OUTPUT ;
    USE SIGNAL ;
    PORT
      LAYER M4 ;
        RECT  86.316 41.616 86.4 41.64 ;
    END
  END rx_d[83]
  PIN rx_d[84]
    DIRECTION OUTPUT ;
    USE SIGNAL ;
    PORT
      LAYER M4 ;
        RECT  86.316 42.096 86.4 42.12 ;
    END
  END rx_d[84]
  PIN rx_d[85]
    DIRECTION OUTPUT ;
    USE SIGNAL ;
    PORT
      LAYER M4 ;
        RECT  86.316 42.576 86.4 42.6 ;
    END
  END rx_d[85]
  PIN rx_d[86]
    DIRECTION OUTPUT ;
    USE SIGNAL ;
    PORT
      LAYER M4 ;
        RECT  86.316 43.056 86.4 43.08 ;
    END
  END rx_d[86]
  PIN rx_d[87]
    DIRECTION OUTPUT ;
    USE SIGNAL ;
    PORT
      LAYER M4 ;
        RECT  86.316 43.536 86.4 43.56 ;
    END
  END rx_d[87]
  PIN rx_d[88]
    DIRECTION OUTPUT ;
    USE SIGNAL ;
    PORT
      LAYER M4 ;
        RECT  86.316 43.968 86.4 43.992 ;
    END
  END rx_d[88]
  PIN rx_d[89]
    DIRECTION OUTPUT ;
    USE SIGNAL ;
    PORT
      LAYER M4 ;
        RECT  86.316 44.448 86.4 44.472 ;
    END
  END rx_d[89]
  PIN rx_d[8]
    DIRECTION OUTPUT ;
    USE SIGNAL ;
    PORT
      LAYER M4 ;
        RECT  86.316 6.144 86.4 6.168 ;
    END
  END rx_d[8]
  PIN rx_d[90]
    DIRECTION OUTPUT ;
    USE SIGNAL ;
    PORT
      LAYER M4 ;
        RECT  86.316 44.928 86.4 44.952 ;
    END
  END rx_d[90]
  PIN rx_d[91]
    DIRECTION OUTPUT ;
    USE SIGNAL ;
    PORT
      LAYER M4 ;
        RECT  86.316 45.408 86.4 45.432 ;
    END
  END rx_d[91]
  PIN rx_d[92]
    DIRECTION OUTPUT ;
    USE SIGNAL ;
    PORT
      LAYER M4 ;
        RECT  86.316 45.888 86.4 45.912 ;
    END
  END rx_d[92]
  PIN rx_d[93]
    DIRECTION OUTPUT ;
    USE SIGNAL ;
    PORT
      LAYER M4 ;
        RECT  86.316 46.368 86.4 46.392 ;
    END
  END rx_d[93]
  PIN rx_d[94]
    DIRECTION OUTPUT ;
    USE SIGNAL ;
    PORT
      LAYER M4 ;
        RECT  86.316 46.8 86.4 46.824 ;
    END
  END rx_d[94]
  PIN rx_d[95]
    DIRECTION OUTPUT ;
    USE SIGNAL ;
    PORT
      LAYER M4 ;
        RECT  86.316 47.28 86.4 47.304 ;
    END
  END rx_d[95]
  PIN rx_d[96]
    DIRECTION OUTPUT ;
    USE SIGNAL ;
    PORT
      LAYER M4 ;
        RECT  86.316 47.76 86.4 47.784 ;
    END
  END rx_d[96]
  PIN rx_d[97]
    DIRECTION OUTPUT ;
    USE SIGNAL ;
    PORT
      LAYER M4 ;
        RECT  86.316 48.24 86.4 48.264 ;
    END
  END rx_d[97]
  PIN rx_d[98]
    DIRECTION OUTPUT ;
    USE SIGNAL ;
    PORT
      LAYER M4 ;
        RECT  86.316 48.72 86.4 48.744 ;
    END
  END rx_d[98]
  PIN rx_d[99]
    DIRECTION OUTPUT ;
    USE SIGNAL ;
    PORT
      LAYER M4 ;
        RECT  86.316 49.2 86.4 49.224 ;
    END
  END rx_d[99]
  PIN rx_d[9]
    DIRECTION OUTPUT ;
    USE SIGNAL ;
    PORT
      LAYER M4 ;
        RECT  86.316 6.624 86.4 6.648 ;
    END
  END rx_d[9]
  PIN VDD
    DIRECTION INOUT ;
    USE POWER ;
    PORT
      LAYER M5 ;
        RECT  83.592 2.151 83.712 127.449 ;
        RECT  78.192 2.151 78.312 127.449 ;
        RECT  72.792 2.151 72.912 127.449 ;
        RECT  67.392 2.151 67.512 127.449 ;
        RECT  61.992 2.151 62.112 127.449 ;
        RECT  56.592 2.151 56.712 127.449 ;
        RECT  51.192 2.151 51.312 127.449 ;
        RECT  45.792 2.151 45.912 127.449 ;
        RECT  40.392 2.151 40.512 127.449 ;
        RECT  34.992 2.151 35.112 127.449 ;
        RECT  29.592 2.151 29.712 127.449 ;
        RECT  24.192 2.151 24.312 127.449 ;
        RECT  18.792 2.151 18.912 127.449 ;
        RECT  13.392 2.151 13.512 127.449 ;
        RECT  7.992 2.151 8.112 127.449 ;
        RECT  2.592 2.151 2.712 127.449 ;
    END
  END VDD
  PIN VSS
    DIRECTION INOUT ;
    USE GROUND ;
    PORT
      LAYER M5 ;
        RECT  83.4 2.137 83.52 127.463 ;
        RECT  78 2.137 78.12 127.463 ;
        RECT  72.6 2.137 72.72 127.463 ;
        RECT  67.2 2.137 67.32 127.463 ;
        RECT  61.8 2.137 61.92 127.463 ;
        RECT  56.4 2.137 56.52 127.463 ;
        RECT  51 2.137 51.12 127.463 ;
        RECT  45.6 2.137 45.72 127.463 ;
        RECT  40.2 2.137 40.32 127.463 ;
        RECT  34.8 2.137 34.92 127.463 ;
        RECT  29.4 2.137 29.52 127.463 ;
        RECT  24 2.137 24.12 127.463 ;
        RECT  18.6 2.137 18.72 127.463 ;
        RECT  13.2 2.137 13.32 127.463 ;
        RECT  7.8 2.137 7.92 127.463 ;
        RECT  2.4 2.137 2.52 127.463 ;
    END
  END VSS
  OBS
    LAYER RVTN ;
     RECT  2.16 2.16 84.24 2.295 ;
     RECT  2.16 2.565 84.24 2.835 ;
     RECT  2.16 3.105 84.24 3.375 ;
     RECT  2.16 3.645 84.24 3.915 ;
     RECT  2.16 4.185 84.24 4.455 ;
     RECT  2.16 4.725 84.24 4.995 ;
     RECT  2.16 5.265 84.24 5.535 ;
     RECT  2.16 5.805 84.24 6.075 ;
     RECT  2.16 6.345 84.24 6.615 ;
     RECT  2.16 6.885 84.24 7.155 ;
     RECT  2.16 7.425 84.24 7.695 ;
     RECT  2.16 7.965 84.24 8.235 ;
     RECT  2.16 8.505 84.24 8.775 ;
     RECT  2.16 9.045 84.24 9.315 ;
     RECT  2.16 9.585 84.24 9.855 ;
     RECT  2.16 10.125 84.24 10.395 ;
     RECT  2.16 10.665 84.24 10.935 ;
     RECT  2.16 11.205 84.24 11.475 ;
     RECT  2.16 11.745 84.24 12.015 ;
     RECT  2.16 12.285 84.24 12.555 ;
     RECT  2.16 12.825 84.24 13.095 ;
     RECT  2.16 13.365 84.24 13.635 ;
     RECT  2.16 13.905 84.24 14.175 ;
     RECT  2.16 14.445 84.24 14.715 ;
     RECT  2.16 14.985 84.24 15.255 ;
     RECT  2.16 15.525 84.24 15.795 ;
     RECT  2.16 16.065 84.24 16.335 ;
     RECT  2.16 16.605 84.24 16.875 ;
     RECT  2.16 17.145 84.24 17.415 ;
     RECT  2.16 17.685 84.24 17.955 ;
     RECT  2.16 18.225 84.24 18.495 ;
     RECT  2.16 18.765 84.24 19.035 ;
     RECT  2.16 19.305 84.24 19.575 ;
     RECT  2.16 19.845 84.24 20.115 ;
     RECT  2.16 20.385 84.24 20.655 ;
     RECT  2.16 20.925 84.24 21.195 ;
     RECT  2.16 21.465 84.24 21.735 ;
     RECT  2.16 22.005 84.24 22.275 ;
     RECT  2.16 22.545 84.24 22.815 ;
     RECT  2.16 23.085 84.24 23.355 ;
     RECT  2.16 23.625 84.24 23.895 ;
     RECT  2.16 24.165 84.24 24.435 ;
     RECT  2.16 24.705 84.24 24.975 ;
     RECT  2.16 25.245 84.24 25.515 ;
     RECT  2.16 25.785 84.24 26.055 ;
     RECT  2.16 26.325 84.24 26.595 ;
     RECT  2.16 26.865 84.24 27.135 ;
     RECT  2.16 27.405 84.24 27.675 ;
     RECT  2.16 27.945 84.24 28.215 ;
     RECT  2.16 28.485 84.24 28.755 ;
     RECT  2.16 29.025 84.24 29.295 ;
     RECT  2.16 29.565 84.24 29.835 ;
     RECT  2.16 30.105 84.24 30.375 ;
     RECT  2.16 30.645 84.24 30.915 ;
     RECT  2.16 31.185 84.24 31.455 ;
     RECT  2.16 31.725 84.24 31.995 ;
     RECT  2.16 32.265 84.24 32.535 ;
     RECT  2.16 32.805 84.24 33.075 ;
     RECT  2.16 33.345 84.24 33.615 ;
     RECT  2.16 33.885 84.24 34.155 ;
     RECT  2.16 34.425 84.24 34.695 ;
     RECT  2.16 34.965 84.24 35.235 ;
     RECT  2.16 35.505 84.24 35.775 ;
     RECT  2.16 36.045 84.24 36.315 ;
     RECT  2.16 36.585 84.24 36.855 ;
     RECT  2.16 37.125 84.24 37.395 ;
     RECT  2.16 37.665 84.24 37.935 ;
     RECT  2.16 38.205 84.24 38.475 ;
     RECT  2.16 38.745 84.24 39.015 ;
     RECT  2.16 39.285 84.24 39.555 ;
     RECT  2.16 39.825 84.24 40.095 ;
     RECT  2.16 40.365 84.24 40.635 ;
     RECT  2.16 40.905 84.24 41.175 ;
     RECT  2.16 41.445 84.24 41.715 ;
     RECT  2.16 41.985 84.24 42.255 ;
     RECT  2.16 42.525 84.24 42.795 ;
     RECT  2.16 43.065 84.24 43.335 ;
     RECT  2.16 43.605 84.24 43.875 ;
     RECT  2.16 44.145 84.24 44.415 ;
     RECT  2.16 44.685 84.24 44.955 ;
     RECT  2.16 45.225 84.24 45.495 ;
     RECT  2.16 45.765 84.24 46.035 ;
     RECT  2.16 46.305 84.24 46.575 ;
     RECT  2.16 46.845 84.24 47.115 ;
     RECT  2.16 47.385 84.24 47.655 ;
     RECT  2.16 47.925 84.24 48.195 ;
     RECT  2.16 48.465 84.24 48.735 ;
     RECT  2.16 49.005 84.24 49.275 ;
     RECT  2.16 49.545 84.24 49.815 ;
     RECT  2.16 50.085 84.24 50.355 ;
     RECT  2.16 50.625 84.24 50.895 ;
     RECT  2.16 51.165 84.24 51.435 ;
     RECT  2.16 51.705 84.24 51.975 ;
     RECT  2.16 52.245 84.24 52.515 ;
     RECT  2.16 52.785 84.24 53.055 ;
     RECT  2.16 53.325 84.24 53.595 ;
     RECT  2.16 53.865 84.24 54.135 ;
     RECT  2.16 54.405 84.24 54.675 ;
     RECT  2.16 54.945 84.24 55.215 ;
     RECT  2.16 55.485 84.24 55.755 ;
     RECT  2.16 56.025 84.24 56.295 ;
     RECT  2.16 56.565 84.24 56.835 ;
     RECT  2.16 57.105 84.24 57.375 ;
     RECT  2.16 57.645 84.24 57.915 ;
     RECT  2.16 58.185 84.24 58.455 ;
     RECT  2.16 58.725 84.24 58.995 ;
     RECT  2.16 59.265 84.24 59.535 ;
     RECT  2.16 59.805 84.24 60.075 ;
     RECT  2.16 60.345 84.24 60.615 ;
     RECT  2.16 60.885 84.24 61.155 ;
     RECT  2.16 61.425 84.24 61.695 ;
     RECT  2.16 61.965 84.24 62.235 ;
     RECT  2.16 62.505 84.24 62.775 ;
     RECT  2.16 63.045 84.24 63.315 ;
     RECT  2.16 63.585 84.24 63.855 ;
     RECT  2.16 64.125 84.24 64.395 ;
     RECT  2.16 64.665 84.24 64.935 ;
     RECT  2.16 65.205 84.24 65.475 ;
     RECT  2.16 65.745 84.24 66.015 ;
     RECT  2.16 66.285 84.24 66.555 ;
     RECT  2.16 66.825 84.24 67.095 ;
     RECT  2.16 67.365 84.24 67.635 ;
     RECT  2.16 67.905 84.24 68.175 ;
     RECT  2.16 68.445 84.24 68.715 ;
     RECT  2.16 68.985 84.24 69.255 ;
     RECT  2.16 69.525 84.24 69.795 ;
     RECT  2.16 70.065 84.24 70.335 ;
     RECT  2.16 70.605 84.24 70.875 ;
     RECT  2.16 71.145 84.24 71.415 ;
     RECT  2.16 71.685 84.24 71.955 ;
     RECT  2.16 72.225 84.24 72.495 ;
     RECT  2.16 72.765 84.24 73.035 ;
     RECT  2.16 73.305 84.24 73.575 ;
     RECT  2.16 73.845 84.24 74.115 ;
     RECT  2.16 74.385 84.24 74.655 ;
     RECT  2.16 74.925 84.24 75.195 ;
     RECT  2.16 75.465 84.24 75.735 ;
     RECT  2.16 76.005 84.24 76.275 ;
     RECT  2.16 76.545 84.24 76.815 ;
     RECT  2.16 77.085 84.24 77.355 ;
     RECT  2.16 77.625 84.24 77.895 ;
     RECT  2.16 78.165 84.24 78.435 ;
     RECT  2.16 78.705 84.24 78.975 ;
     RECT  2.16 79.245 84.24 79.515 ;
     RECT  2.16 79.785 84.24 80.055 ;
     RECT  2.16 80.325 84.24 80.595 ;
     RECT  2.16 80.865 84.24 81.135 ;
     RECT  2.16 81.405 84.24 81.675 ;
     RECT  2.16 81.945 84.24 82.215 ;
     RECT  2.16 82.485 84.24 82.755 ;
     RECT  2.16 83.025 84.24 83.295 ;
     RECT  2.16 83.565 84.24 83.835 ;
     RECT  2.16 84.105 84.24 84.375 ;
     RECT  2.16 84.645 84.24 84.915 ;
     RECT  2.16 85.185 84.24 85.455 ;
     RECT  2.16 85.725 84.24 85.995 ;
     RECT  2.16 86.265 84.24 86.535 ;
     RECT  2.16 86.805 84.24 87.075 ;
     RECT  2.16 87.345 84.24 87.615 ;
     RECT  2.16 87.885 84.24 88.155 ;
     RECT  2.16 88.425 84.24 88.695 ;
     RECT  2.16 88.965 84.24 89.235 ;
     RECT  2.16 89.505 84.24 89.775 ;
     RECT  2.16 90.045 84.24 90.315 ;
     RECT  2.16 90.585 84.24 90.855 ;
     RECT  2.16 91.125 84.24 91.395 ;
     RECT  2.16 91.665 84.24 91.935 ;
     RECT  2.16 92.205 84.24 92.475 ;
     RECT  2.16 92.745 84.24 93.015 ;
     RECT  2.16 93.285 84.24 93.555 ;
     RECT  2.16 93.825 84.24 94.095 ;
     RECT  2.16 94.365 84.24 94.635 ;
     RECT  2.16 94.905 84.24 95.175 ;
     RECT  2.16 95.445 84.24 95.715 ;
     RECT  2.16 95.985 84.24 96.255 ;
     RECT  2.16 96.525 84.24 96.795 ;
     RECT  2.16 97.065 84.24 97.335 ;
     RECT  2.16 97.605 84.24 97.875 ;
     RECT  2.16 98.145 84.24 98.415 ;
     RECT  2.16 98.685 84.24 98.955 ;
     RECT  2.16 99.225 84.24 99.495 ;
     RECT  2.16 99.765 84.24 100.035 ;
     RECT  2.16 100.305 84.24 100.575 ;
     RECT  2.16 100.845 84.24 101.115 ;
     RECT  2.16 101.385 84.24 101.655 ;
     RECT  2.16 101.925 84.24 102.195 ;
     RECT  2.16 102.465 84.24 102.735 ;
     RECT  2.16 103.005 84.24 103.275 ;
     RECT  2.16 103.545 84.24 103.815 ;
     RECT  2.16 104.085 84.24 104.355 ;
     RECT  2.16 104.625 84.24 104.895 ;
     RECT  2.16 105.165 84.24 105.435 ;
     RECT  2.16 105.705 84.24 105.975 ;
     RECT  2.16 106.245 84.24 106.515 ;
     RECT  2.16 106.785 84.24 107.055 ;
     RECT  2.16 107.325 84.24 107.595 ;
     RECT  2.16 107.865 84.24 108.135 ;
     RECT  2.16 108.405 84.24 108.675 ;
     RECT  2.16 108.945 84.24 109.215 ;
     RECT  2.16 109.485 84.24 109.755 ;
     RECT  2.16 110.025 84.24 110.295 ;
     RECT  2.16 110.565 84.24 110.835 ;
     RECT  2.16 111.105 84.24 111.375 ;
     RECT  2.16 111.645 84.24 111.915 ;
     RECT  2.16 112.185 84.24 112.455 ;
     RECT  2.16 112.725 84.24 112.995 ;
     RECT  2.16 113.265 84.24 113.535 ;
     RECT  2.16 113.805 84.24 114.075 ;
     RECT  2.16 114.345 84.24 114.615 ;
     RECT  2.16 114.885 84.24 115.155 ;
     RECT  2.16 115.425 84.24 115.695 ;
     RECT  2.16 115.965 84.24 116.235 ;
     RECT  2.16 116.505 84.24 116.775 ;
     RECT  2.16 117.045 84.24 117.315 ;
     RECT  2.16 117.585 84.24 117.855 ;
     RECT  2.16 118.125 84.24 118.395 ;
     RECT  2.16 118.665 84.24 118.935 ;
     RECT  2.16 119.205 84.24 119.475 ;
     RECT  2.16 119.745 84.24 120.015 ;
     RECT  2.16 120.285 84.24 120.555 ;
     RECT  2.16 120.825 84.24 121.095 ;
     RECT  2.16 121.365 84.24 121.635 ;
     RECT  2.16 121.905 84.24 122.175 ;
     RECT  2.16 122.445 84.24 122.715 ;
     RECT  2.16 122.985 84.24 123.255 ;
     RECT  2.16 123.525 84.24 123.795 ;
     RECT  2.16 124.065 84.24 124.335 ;
     RECT  2.16 124.605 84.24 124.875 ;
     RECT  2.16 125.145 84.24 125.415 ;
     RECT  2.16 125.685 84.24 125.955 ;
     RECT  2.16 126.225 84.24 126.495 ;
     RECT  2.16 126.765 84.24 127.035 ;
     RECT  2.16 127.305 84.24 127.44 ;
    LAYER RVTP ;
     RECT  2.16 2.295 84.24 2.565 ;
     RECT  2.16 2.835 84.24 3.105 ;
     RECT  2.16 3.375 84.24 3.645 ;
     RECT  2.16 3.915 84.24 4.185 ;
     RECT  2.16 4.455 84.24 4.725 ;
     RECT  2.16 4.995 84.24 5.265 ;
     RECT  2.16 5.535 84.24 5.805 ;
     RECT  2.16 6.075 84.24 6.345 ;
     RECT  2.16 6.615 84.24 6.885 ;
     RECT  2.16 7.155 84.24 7.425 ;
     RECT  2.16 7.695 84.24 7.965 ;
     RECT  2.16 8.235 84.24 8.505 ;
     RECT  2.16 8.775 84.24 9.045 ;
     RECT  2.16 9.315 84.24 9.585 ;
     RECT  2.16 9.855 84.24 10.125 ;
     RECT  2.16 10.395 84.24 10.665 ;
     RECT  2.16 10.935 84.24 11.205 ;
     RECT  2.16 11.475 84.24 11.745 ;
     RECT  2.16 12.015 84.24 12.285 ;
     RECT  2.16 12.555 84.24 12.825 ;
     RECT  2.16 13.095 84.24 13.365 ;
     RECT  2.16 13.635 84.24 13.905 ;
     RECT  2.16 14.175 84.24 14.445 ;
     RECT  2.16 14.715 84.24 14.985 ;
     RECT  2.16 15.255 84.24 15.525 ;
     RECT  2.16 15.795 84.24 16.065 ;
     RECT  2.16 16.335 84.24 16.605 ;
     RECT  2.16 16.875 84.24 17.145 ;
     RECT  2.16 17.415 84.24 17.685 ;
     RECT  2.16 17.955 84.24 18.225 ;
     RECT  2.16 18.495 84.24 18.765 ;
     RECT  2.16 19.035 84.24 19.305 ;
     RECT  2.16 19.575 84.24 19.845 ;
     RECT  2.16 20.115 84.24 20.385 ;
     RECT  2.16 20.655 84.24 20.925 ;
     RECT  2.16 21.195 84.24 21.465 ;
     RECT  2.16 21.735 84.24 22.005 ;
     RECT  2.16 22.275 84.24 22.545 ;
     RECT  2.16 22.815 84.24 23.085 ;
     RECT  2.16 23.355 84.24 23.625 ;
     RECT  2.16 23.895 84.24 24.165 ;
     RECT  2.16 24.435 84.24 24.705 ;
     RECT  2.16 24.975 84.24 25.245 ;
     RECT  2.16 25.515 84.24 25.785 ;
     RECT  2.16 26.055 84.24 26.325 ;
     RECT  2.16 26.595 84.24 26.865 ;
     RECT  2.16 27.135 84.24 27.405 ;
     RECT  2.16 27.675 84.24 27.945 ;
     RECT  2.16 28.215 84.24 28.485 ;
     RECT  2.16 28.755 84.24 29.025 ;
     RECT  2.16 29.295 84.24 29.565 ;
     RECT  2.16 29.835 84.24 30.105 ;
     RECT  2.16 30.375 84.24 30.645 ;
     RECT  2.16 30.915 84.24 31.185 ;
     RECT  2.16 31.455 84.24 31.725 ;
     RECT  2.16 31.995 84.24 32.265 ;
     RECT  2.16 32.535 84.24 32.805 ;
     RECT  2.16 33.075 84.24 33.345 ;
     RECT  2.16 33.615 84.24 33.885 ;
     RECT  2.16 34.155 84.24 34.425 ;
     RECT  2.16 34.695 84.24 34.965 ;
     RECT  2.16 35.235 84.24 35.505 ;
     RECT  2.16 35.775 84.24 36.045 ;
     RECT  2.16 36.315 84.24 36.585 ;
     RECT  2.16 36.855 84.24 37.125 ;
     RECT  2.16 37.395 84.24 37.665 ;
     RECT  2.16 37.935 84.24 38.205 ;
     RECT  2.16 38.475 84.24 38.745 ;
     RECT  2.16 39.015 84.24 39.285 ;
     RECT  2.16 39.555 84.24 39.825 ;
     RECT  2.16 40.095 84.24 40.365 ;
     RECT  2.16 40.635 84.24 40.905 ;
     RECT  2.16 41.175 84.24 41.445 ;
     RECT  2.16 41.715 84.24 41.985 ;
     RECT  2.16 42.255 84.24 42.525 ;
     RECT  2.16 42.795 84.24 43.065 ;
     RECT  2.16 43.335 84.24 43.605 ;
     RECT  2.16 43.875 84.24 44.145 ;
     RECT  2.16 44.415 84.24 44.685 ;
     RECT  2.16 44.955 84.24 45.225 ;
     RECT  2.16 45.495 84.24 45.765 ;
     RECT  2.16 46.035 84.24 46.305 ;
     RECT  2.16 46.575 84.24 46.845 ;
     RECT  2.16 47.115 84.24 47.385 ;
     RECT  2.16 47.655 84.24 47.925 ;
     RECT  2.16 48.195 84.24 48.465 ;
     RECT  2.16 48.735 84.24 49.005 ;
     RECT  2.16 49.275 84.24 49.545 ;
     RECT  2.16 49.815 84.24 50.085 ;
     RECT  2.16 50.355 84.24 50.625 ;
     RECT  2.16 50.895 84.24 51.165 ;
     RECT  2.16 51.435 84.24 51.705 ;
     RECT  2.16 51.975 84.24 52.245 ;
     RECT  2.16 52.515 84.24 52.785 ;
     RECT  2.16 53.055 84.24 53.325 ;
     RECT  2.16 53.595 84.24 53.865 ;
     RECT  2.16 54.135 84.24 54.405 ;
     RECT  2.16 54.675 84.24 54.945 ;
     RECT  2.16 55.215 84.24 55.485 ;
     RECT  2.16 55.755 84.24 56.025 ;
     RECT  2.16 56.295 84.24 56.565 ;
     RECT  2.16 56.835 84.24 57.105 ;
     RECT  2.16 57.375 84.24 57.645 ;
     RECT  2.16 57.915 84.24 58.185 ;
     RECT  2.16 58.455 84.24 58.725 ;
     RECT  2.16 58.995 84.24 59.265 ;
     RECT  2.16 59.535 84.24 59.805 ;
     RECT  2.16 60.075 84.24 60.345 ;
     RECT  2.16 60.615 84.24 60.885 ;
     RECT  2.16 61.155 84.24 61.425 ;
     RECT  2.16 61.695 84.24 61.965 ;
     RECT  2.16 62.235 84.24 62.505 ;
     RECT  2.16 62.775 84.24 63.045 ;
     RECT  2.16 63.315 84.24 63.585 ;
     RECT  2.16 63.855 84.24 64.125 ;
     RECT  2.16 64.395 84.24 64.665 ;
     RECT  2.16 64.935 84.24 65.205 ;
     RECT  2.16 65.475 84.24 65.745 ;
     RECT  2.16 66.015 84.24 66.285 ;
     RECT  2.16 66.555 84.24 66.825 ;
     RECT  2.16 67.095 84.24 67.365 ;
     RECT  2.16 67.635 84.24 67.905 ;
     RECT  2.16 68.175 84.24 68.445 ;
     RECT  2.16 68.715 84.24 68.985 ;
     RECT  2.16 69.255 84.24 69.525 ;
     RECT  2.16 69.795 84.24 70.065 ;
     RECT  2.16 70.335 84.24 70.605 ;
     RECT  2.16 70.875 84.24 71.145 ;
     RECT  2.16 71.415 84.24 71.685 ;
     RECT  2.16 71.955 84.24 72.225 ;
     RECT  2.16 72.495 84.24 72.765 ;
     RECT  2.16 73.035 84.24 73.305 ;
     RECT  2.16 73.575 84.24 73.845 ;
     RECT  2.16 74.115 84.24 74.385 ;
     RECT  2.16 74.655 84.24 74.925 ;
     RECT  2.16 75.195 84.24 75.465 ;
     RECT  2.16 75.735 84.24 76.005 ;
     RECT  2.16 76.275 84.24 76.545 ;
     RECT  2.16 76.815 84.24 77.085 ;
     RECT  2.16 77.355 84.24 77.625 ;
     RECT  2.16 77.895 84.24 78.165 ;
     RECT  2.16 78.435 84.24 78.705 ;
     RECT  2.16 78.975 84.24 79.245 ;
     RECT  2.16 79.515 84.24 79.785 ;
     RECT  2.16 80.055 84.24 80.325 ;
     RECT  2.16 80.595 84.24 80.865 ;
     RECT  2.16 81.135 84.24 81.405 ;
     RECT  2.16 81.675 84.24 81.945 ;
     RECT  2.16 82.215 84.24 82.485 ;
     RECT  2.16 82.755 84.24 83.025 ;
     RECT  2.16 83.295 84.24 83.565 ;
     RECT  2.16 83.835 84.24 84.105 ;
     RECT  2.16 84.375 84.24 84.645 ;
     RECT  2.16 84.915 84.24 85.185 ;
     RECT  2.16 85.455 84.24 85.725 ;
     RECT  2.16 85.995 84.24 86.265 ;
     RECT  2.16 86.535 84.24 86.805 ;
     RECT  2.16 87.075 84.24 87.345 ;
     RECT  2.16 87.615 84.24 87.885 ;
     RECT  2.16 88.155 84.24 88.425 ;
     RECT  2.16 88.695 84.24 88.965 ;
     RECT  2.16 89.235 84.24 89.505 ;
     RECT  2.16 89.775 84.24 90.045 ;
     RECT  2.16 90.315 84.24 90.585 ;
     RECT  2.16 90.855 84.24 91.125 ;
     RECT  2.16 91.395 84.24 91.665 ;
     RECT  2.16 91.935 84.24 92.205 ;
     RECT  2.16 92.475 84.24 92.745 ;
     RECT  2.16 93.015 84.24 93.285 ;
     RECT  2.16 93.555 84.24 93.825 ;
     RECT  2.16 94.095 84.24 94.365 ;
     RECT  2.16 94.635 84.24 94.905 ;
     RECT  2.16 95.175 84.24 95.445 ;
     RECT  2.16 95.715 84.24 95.985 ;
     RECT  2.16 96.255 84.24 96.525 ;
     RECT  2.16 96.795 84.24 97.065 ;
     RECT  2.16 97.335 84.24 97.605 ;
     RECT  2.16 97.875 84.24 98.145 ;
     RECT  2.16 98.415 84.24 98.685 ;
     RECT  2.16 98.955 84.24 99.225 ;
     RECT  2.16 99.495 84.24 99.765 ;
     RECT  2.16 100.035 84.24 100.305 ;
     RECT  2.16 100.575 84.24 100.845 ;
     RECT  2.16 101.115 84.24 101.385 ;
     RECT  2.16 101.655 84.24 101.925 ;
     RECT  2.16 102.195 84.24 102.465 ;
     RECT  2.16 102.735 84.24 103.005 ;
     RECT  2.16 103.275 84.24 103.545 ;
     RECT  2.16 103.815 84.24 104.085 ;
     RECT  2.16 104.355 84.24 104.625 ;
     RECT  2.16 104.895 84.24 105.165 ;
     RECT  2.16 105.435 84.24 105.705 ;
     RECT  2.16 105.975 84.24 106.245 ;
     RECT  2.16 106.515 84.24 106.785 ;
     RECT  2.16 107.055 84.24 107.325 ;
     RECT  2.16 107.595 84.24 107.865 ;
     RECT  2.16 108.135 84.24 108.405 ;
     RECT  2.16 108.675 84.24 108.945 ;
     RECT  2.16 109.215 84.24 109.485 ;
     RECT  2.16 109.755 84.24 110.025 ;
     RECT  2.16 110.295 84.24 110.565 ;
     RECT  2.16 110.835 84.24 111.105 ;
     RECT  2.16 111.375 84.24 111.645 ;
     RECT  2.16 111.915 84.24 112.185 ;
     RECT  2.16 112.455 84.24 112.725 ;
     RECT  2.16 112.995 84.24 113.265 ;
     RECT  2.16 113.535 84.24 113.805 ;
     RECT  2.16 114.075 84.24 114.345 ;
     RECT  2.16 114.615 84.24 114.885 ;
     RECT  2.16 115.155 84.24 115.425 ;
     RECT  2.16 115.695 84.24 115.965 ;
     RECT  2.16 116.235 84.24 116.505 ;
     RECT  2.16 116.775 84.24 117.045 ;
     RECT  2.16 117.315 84.24 117.585 ;
     RECT  2.16 117.855 84.24 118.125 ;
     RECT  2.16 118.395 84.24 118.665 ;
     RECT  2.16 118.935 84.24 119.205 ;
     RECT  2.16 119.475 84.24 119.745 ;
     RECT  2.16 120.015 84.24 120.285 ;
     RECT  2.16 120.555 84.24 120.825 ;
     RECT  2.16 121.095 84.24 121.365 ;
     RECT  2.16 121.635 84.24 121.905 ;
     RECT  2.16 122.175 84.24 122.445 ;
     RECT  2.16 122.715 84.24 122.985 ;
     RECT  2.16 123.255 84.24 123.525 ;
     RECT  2.16 123.795 84.24 124.065 ;
     RECT  2.16 124.335 84.24 124.605 ;
     RECT  2.16 124.875 84.24 125.145 ;
     RECT  2.16 125.415 84.24 125.685 ;
     RECT  2.16 125.955 84.24 126.225 ;
     RECT  2.16 126.495 84.24 126.765 ;
     RECT  2.16 127.035 84.24 127.305 ;
    LAYER M1 ;
     RECT  2.16 2.151 84.24 127.449 ;
    LAYER M2 ;
     RECT  0.103 13.302 0.139 13.32 ;
     RECT  0.103 104.562 0.139 104.58 ;
     RECT  0.103 118.332 0.139 118.35 ;
     RECT  0.103 2.772 2.16 2.79 ;
     RECT  0.103 3.852 2.16 4.41 ;
     RECT  0.103 7.632 2.16 8.19 ;
     RECT  0.103 9.522 2.16 10.08 ;
     RECT  0.139 13.302 2.16 13.86 ;
     RECT  0.103 17.622 2.16 17.64 ;
     RECT  0.103 18.972 2.16 18.99 ;
     RECT  0.103 22.752 2.16 23.31 ;
     RECT  0.103 25.056 2.16 25.074 ;
     RECT  0.103 28.422 2.16 28.98 ;
     RECT  0.103 32.202 2.16 32.76 ;
     RECT  0.103 34.632 2.16 34.65 ;
     RECT  0.103 37.872 2.16 38.43 ;
     RECT  0.103 44.082 2.16 44.1 ;
     RECT  0.103 47.862 2.16 47.88 ;
     RECT  0.103 53.532 2.16 53.55 ;
     RECT  0.103 59.202 2.16 59.22 ;
     RECT  0.103 62.982 2.16 63 ;
     RECT  0.103 68.652 2.16 68.67 ;
     RECT  0.103 74.322 2.16 74.88 ;
     RECT  0.103 83.772 2.16 84.33 ;
     RECT  0.103 87.552 2.16 87.57 ;
     RECT  0.103 89.442 2.16 90 ;
     RECT  0.103 93.222 2.16 93.78 ;
     RECT  0.103 98.892 2.16 99.45 ;
     RECT  0.103 102.672 2.16 103.104 ;
     RECT  0.139 104.562 2.16 105.12 ;
     RECT  0.103 108.342 2.16 108.864 ;
     RECT  0.103 112.122 2.16 112.68 ;
     RECT  0.103 114.552 2.16 114.57 ;
     RECT  0.139 117.792 2.16 118.35 ;
     RECT  0.103 119.682 2.16 120.24 ;
     RECT  0.103 123.462 2.16 124.02 ;
     RECT  0.103 127.242 2.16 127.26 ;
     RECT  2.16 2.151 84.24 127.449 ;
     RECT  84.24 119.646 84.407 121.554 ;
     RECT  84.24 125.316 84.407 126.72 ;
     RECT  84.24 122.346 84.911 123.714 ;
     RECT  84.911 122.346 84.947 122.904 ;
     RECT  84.24 2.466 85.487 2.484 ;
     RECT  84.24 3.276 85.523 6.534 ;
     RECT  84.24 8.946 85.523 10.314 ;
     RECT  84.24 11.376 85.523 12.744 ;
     RECT  84.24 14.076 85.523 14.364 ;
     RECT  84.24 15.156 85.523 15.984 ;
     RECT  84.24 17.046 85.523 21.114 ;
     RECT  84.24 22.446 85.523 26.514 ;
     RECT  84.24 28.386 85.523 30.294 ;
     RECT  84.24 31.086 85.523 32.724 ;
     RECT  84.24 33.516 85.523 38.394 ;
     RECT  84.24 39.186 85.523 43.524 ;
     RECT  84.24 44.856 85.523 49.194 ;
     RECT  84.24 49.986 85.523 51.894 ;
     RECT  84.24 52.956 85.523 54.324 ;
     RECT  84.24 55.386 85.523 55.944 ;
     RECT  84.24 56.736 85.523 57.024 ;
     RECT  84.24 58.626 85.523 61.074 ;
     RECT  84.24 61.866 85.523 62.964 ;
     RECT  84.24 64.296 85.523 66.204 ;
     RECT  84.24 66.996 85.523 68.634 ;
     RECT  84.24 69.426 85.523 74.304 ;
     RECT  84.24 75.096 85.523 79.434 ;
     RECT  84.24 80.766 85.523 81.054 ;
     RECT  84.24 81.846 85.523 82.674 ;
     RECT  84.24 83.466 85.523 85.644 ;
     RECT  84.24 86.436 85.523 87.804 ;
     RECT  84.24 88.866 85.523 90.234 ;
     RECT  84.24 91.566 85.523 92.934 ;
     RECT  84.24 94.536 85.523 98.334 ;
     RECT  84.24 100.206 85.523 104.544 ;
     RECT  84.24 105.606 85.523 105.624 ;
     RECT  84.24 106.416 85.523 109.134 ;
     RECT  84.24 110.196 85.523 115.884 ;
     RECT  84.24 116.676 85.523 118.584 ;
     RECT  84.407 119.646 85.523 120.474 ;
     RECT  84.407 121.536 85.523 121.554 ;
     RECT  84.947 122.346 85.523 122.364 ;
     RECT  84.911 123.696 85.523 123.714 ;
     RECT  84.407 125.316 85.523 126.684 ;
     RECT  85.523 6.246 86.315 6.264 ;
     RECT  85.523 9.486 86.315 9.504 ;
     RECT  85.523 11.916 86.315 11.934 ;
     RECT  85.523 17.046 86.315 17.064 ;
     RECT  85.523 18.936 86.315 19.494 ;
     RECT  85.523 28.386 86.315 28.404 ;
     RECT  85.523 32.166 86.315 32.724 ;
     RECT  85.523 37.836 86.315 38.394 ;
     RECT  85.523 47.286 86.315 47.304 ;
     RECT  85.523 53.496 86.315 53.514 ;
     RECT  85.523 55.386 86.315 55.404 ;
     RECT  85.523 61.056 86.315 61.074 ;
     RECT  85.523 62.946 86.315 62.964 ;
     RECT  85.523 68.616 86.315 68.634 ;
     RECT  85.523 74.286 86.315 74.304 ;
     RECT  85.523 78.066 86.315 78.084 ;
     RECT  85.523 81.846 86.315 81.864 ;
     RECT  85.523 85.626 86.315 85.644 ;
     RECT  85.523 89.406 86.315 89.424 ;
     RECT  84.24 93.726 86.315 93.744 ;
     RECT  85.523 95.076 86.315 95.634 ;
     RECT  85.523 96.966 86.315 96.984 ;
     RECT  85.523 102.636 86.315 102.654 ;
     RECT  85.523 104.526 86.315 104.544 ;
     RECT  85.523 106.416 86.315 106.434 ;
     RECT  85.523 108.306 86.315 108.324 ;
     RECT  85.523 110.196 86.315 110.754 ;
     RECT  85.523 112.086 86.315 112.644 ;
     RECT  85.523 113.976 86.315 113.994 ;
     RECT  85.523 115.866 86.315 115.884 ;
     RECT  85.523 119.646 86.315 120.204 ;
     RECT  85.523 125.316 86.315 125.334 ;
    LAYER M3 ;
     RECT  2.415 2.143 2.505 2.413 ;
     RECT  7.815 2.143 7.905 2.413 ;
     RECT  13.215 2.143 13.305 2.413 ;
     RECT  18.615 2.143 18.705 2.413 ;
     RECT  24.015 2.143 24.105 2.413 ;
     RECT  29.415 2.143 29.505 2.413 ;
     RECT  34.815 2.143 34.905 2.413 ;
     RECT  40.215 2.143 40.305 2.413 ;
     RECT  45.615 2.143 45.705 2.413 ;
     RECT  51.015 2.143 51.105 2.413 ;
     RECT  56.415 2.143 56.505 2.413 ;
     RECT  61.815 2.143 61.905 2.413 ;
     RECT  67.215 2.143 67.305 2.413 ;
     RECT  72.615 2.143 72.705 2.413 ;
     RECT  78.015 2.143 78.105 2.413 ;
     RECT  83.415 2.143 83.505 2.413 ;
     RECT  85.464 2.395 85.482 2.489 ;
     RECT  40.215 2.413 40.497 2.641 ;
     RECT  45.615 2.413 45.897 2.641 ;
     RECT  10.188 2.725 10.206 2.731 ;
     RECT  45.432 2.641 45.897 2.731 ;
     RECT  20.484 2.641 20.502 2.759 ;
     RECT  42.912 2.641 43.146 2.759 ;
     RECT  0.108 2.395 0.126 2.795 ;
     RECT  10.188 2.731 10.278 2.795 ;
     RECT  40.032 2.641 40.497 2.803 ;
     RECT  41.292 2.731 41.31 2.803 ;
     RECT  44.928 2.731 45.897 2.831 ;
     RECT  42.912 2.759 42.966 2.861 ;
     RECT  10.188 2.795 10.242 2.875 ;
     RECT  47.844 2.731 47.862 2.909 ;
     RECT  41.292 2.803 41.886 2.911 ;
     RECT  10.008 2.875 10.242 3.029 ;
     RECT  38.772 2.803 38.79 3.029 ;
     RECT  10.008 3.029 10.026 3.065 ;
     RECT  19.944 2.911 20.286 3.065 ;
     RECT  41.292 2.911 42.066 3.065 ;
     RECT  41.76 3.065 42.066 3.137 ;
     RECT  20.268 3.065 20.286 3.299 ;
     RECT  18.615 2.413 18.897 3.307 ;
     RECT  40.032 2.803 40.554 3.335 ;
     RECT  18.615 3.307 19.422 3.344 ;
     RECT  40.215 3.335 40.554 3.379 ;
     RECT  41.76 3.137 41.958 3.437 ;
     RECT  42.912 2.861 42.93 3.721 ;
     RECT  42.912 3.721 43.074 3.725 ;
     RECT  43.056 3.725 43.074 3.839 ;
     RECT  40.215 3.379 40.626 3.875 ;
     RECT  10.368 3.847 10.386 4.019 ;
     RECT  40.215 3.875 40.497 4.225 ;
     RECT  41.94 3.437 41.958 4.261 ;
     RECT  39.6 4.225 40.497 4.379 ;
     RECT  41.796 4.261 41.958 4.379 ;
     RECT  0.108 3.787 0.126 4.415 ;
     RECT  39.816 4.379 40.497 4.415 ;
     RECT  19.836 4.351 19.854 4.451 ;
     RECT  41.796 4.379 41.814 4.541 ;
     RECT  40.14 4.415 40.497 4.651 ;
     RECT  40.14 4.651 40.662 4.801 ;
     RECT  40.14 4.801 40.806 4.919 ;
     RECT  17.1 4.747 17.118 4.955 ;
     RECT  42.696 5.179 42.714 5.225 ;
     RECT  20.844 5.197 20.862 5.305 ;
     RECT  20.664 5.305 20.862 5.369 ;
     RECT  20.664 5.369 20.682 5.459 ;
     RECT  42.84 5.341 42.858 5.459 ;
     RECT  9.144 5.227 9.162 5.495 ;
     RECT  41.436 5.341 41.454 5.495 ;
     RECT  40.215 4.919 40.497 5.707 ;
     RECT  85.5 3.271 85.518 5.741 ;
     RECT  17.1 5.707 17.118 5.765 ;
     RECT  34.815 2.413 35.097 6.151 ;
     RECT  34.776 6.151 35.097 6.269 ;
     RECT  43.848 6.115 43.866 6.269 ;
     RECT  48.564 6.115 48.582 6.269 ;
     RECT  86.292 6.139 86.31 6.269 ;
     RECT  20.484 6.139 20.502 6.305 ;
     RECT  38.772 6.151 38.79 6.305 ;
     RECT  40.215 5.707 41.382 6.421 ;
     RECT  40.215 6.421 41.526 6.523 ;
     RECT  85.5 6.511 85.518 6.653 ;
     RECT  40.215 6.523 41.85 6.691 ;
     RECT  10.476 6.691 10.494 6.809 ;
     RECT  40.215 6.691 41.994 6.809 ;
     RECT  9.144 6.619 9.162 6.845 ;
     RECT  41.436 6.809 41.994 7.051 ;
     RECT  83.415 2.413 83.697 7.051 ;
     RECT  83.415 7.051 83.826 7.133 ;
     RECT  41.436 7.051 42.858 7.151 ;
     RECT  20.556 6.691 20.574 7.195 ;
     RECT  41.508 7.151 42.858 7.231 ;
     RECT  20.556 7.195 20.79 7.349 ;
     RECT  10.404 7.099 10.422 7.385 ;
     RECT  40.215 6.809 40.497 7.465 ;
     RECT  56.415 2.413 56.697 7.483 ;
     RECT  67.215 2.413 67.497 7.483 ;
     RECT  78.015 2.413 78.297 7.483 ;
     RECT  83.415 7.133 83.697 7.483 ;
     RECT  41.508 7.231 43.038 7.493 ;
     RECT  56.304 7.483 56.697 7.529 ;
     RECT  67.104 7.483 67.497 7.529 ;
     RECT  77.904 7.483 78.297 7.529 ;
     RECT  83.304 7.483 83.697 7.529 ;
     RECT  10.26 7.501 10.278 7.619 ;
     RECT  40.032 7.465 40.497 7.619 ;
     RECT  43.02 7.493 43.038 7.619 ;
     RECT  20.052 7.501 20.07 7.655 ;
     RECT  41.508 7.493 42.21 7.655 ;
     RECT  49.248 7.501 49.266 7.661 ;
     RECT  49.32 7.933 49.338 7.997 ;
     RECT  40.215 7.619 40.497 8.005 ;
     RECT  40.215 8.005 40.77 8.159 ;
     RECT  0.108 7.579 0.126 8.195 ;
     RECT  41.508 7.655 41.922 8.195 ;
     RECT  20.376 8.131 20.394 8.231 ;
     RECT  18.615 3.344 18.897 8.581 ;
     RECT  49.248 8.539 49.266 8.609 ;
     RECT  10.008 8.581 10.026 8.699 ;
     RECT  39.06 8.545 39.078 8.699 ;
     RECT  18.615 8.581 19.602 8.735 ;
     RECT  41.58 8.195 41.922 8.941 ;
     RECT  20.52 8.851 20.538 8.969 ;
     RECT  40.215 8.159 40.662 9.005 ;
     RECT  7.815 2.413 8.097 9.019 ;
     RECT  41.436 8.941 41.922 9.101 ;
     RECT  18.615 8.735 19.422 9.239 ;
     RECT  7.416 9.019 8.097 9.275 ;
     RECT  20.376 9.391 20.394 9.509 ;
     RECT  86.292 9.451 86.31 9.509 ;
     RECT  42.876 9.067 42.894 9.661 ;
     RECT  41.436 9.101 41.778 9.895 ;
     RECT  42.876 9.661 42.966 9.931 ;
     RECT  10.548 9.931 10.566 10.049 ;
     RECT  42.876 9.931 43.146 10.049 ;
     RECT  0.108 9.451 0.126 10.085 ;
     RECT  20.664 9.931 20.682 10.085 ;
     RECT  41.22 9.895 41.778 10.085 ;
     RECT  40.215 9.005 40.497 10.399 ;
     RECT  7.815 9.275 8.097 10.411 ;
     RECT  85.5 8.941 85.518 10.445 ;
     RECT  42.876 10.049 43.038 10.541 ;
     RECT  20.52 10.471 20.538 10.561 ;
     RECT  20.34 10.561 20.538 10.589 ;
     RECT  43.02 10.541 43.038 10.589 ;
     RECT  7.815 10.411 8.154 10.625 ;
     RECT  41.868 10.471 41.886 10.625 ;
     RECT  20.34 10.589 20.358 10.733 ;
     RECT  51.015 2.413 51.297 10.741 ;
     RECT  38.772 10.705 38.79 10.859 ;
     RECT  40.215 10.399 40.806 10.895 ;
     RECT  50.436 10.741 51.297 10.925 ;
     RECT  2.415 2.413 2.697 11.371 ;
     RECT  7.815 10.625 8.097 11.371 ;
     RECT  85.5 11.365 85.518 11.405 ;
     RECT  41.22 11.371 41.634 11.407 ;
     RECT  41.22 11.407 41.85 11.551 ;
     RECT  20.664 11.515 20.682 11.669 ;
     RECT  41.22 11.551 41.994 11.669 ;
     RECT  7.416 11.371 8.097 11.705 ;
     RECT  2.304 11.371 2.697 11.885 ;
     RECT  40.215 10.895 40.497 11.911 ;
     RECT  41.22 11.669 41.742 11.911 ;
     RECT  86.292 11.851 86.31 11.939 ;
     RECT  7.704 11.705 8.097 11.975 ;
     RECT  40.215 11.911 41.742 11.998 ;
     RECT  20.484 11.911 20.502 12.011 ;
     RECT  40.215 11.998 41.418 12.083 ;
     RECT  40.215 12.083 41.058 12.325 ;
     RECT  40.14 12.325 41.058 12.479 ;
     RECT  85.5 12.181 85.518 12.797 ;
     RECT  20.52 12.757 20.538 12.865 ;
     RECT  42.876 12.715 42.894 12.901 ;
     RECT  40.215 12.479 41.058 12.991 ;
     RECT  20.34 12.865 20.538 13.019 ;
     RECT  42.768 12.901 42.894 13.019 ;
     RECT  40.215 12.991 41.634 13.091 ;
     RECT  49.32 13.063 49.338 13.181 ;
     RECT  86.292 13.147 86.31 13.277 ;
     RECT  10.584 13.171 10.602 13.289 ;
     RECT  41.292 13.091 41.634 13.289 ;
     RECT  43.128 13.171 43.146 13.289 ;
     RECT  0.108 13.243 0.126 13.325 ;
     RECT  20.664 13.171 20.682 13.325 ;
     RECT  41.616 13.289 41.634 13.325 ;
     RECT  40.215 13.091 40.497 13.531 ;
     RECT  41.724 13.531 41.85 13.603 ;
     RECT  83.415 7.529 83.697 13.711 ;
     RECT  83.415 13.711 83.79 13.757 ;
     RECT  41.724 13.603 41.922 13.829 ;
     RECT  0.144 13.723 0.162 13.865 ;
     RECT  7.815 11.975 8.097 14.203 ;
     RECT  38.772 13.567 38.79 14.369 ;
     RECT  41.724 13.829 41.814 14.369 ;
     RECT  7.416 14.203 8.097 14.405 ;
     RECT  43.02 14.347 43.038 14.405 ;
     RECT  19.728 13.801 19.746 14.441 ;
     RECT  39.924 13.531 40.497 14.485 ;
     RECT  39.348 14.485 40.497 14.639 ;
     RECT  43.164 14.521 43.182 14.639 ;
     RECT  39.528 14.639 40.497 14.675 ;
     RECT  2.415 11.885 2.697 15.151 ;
     RECT  7.815 14.405 8.097 15.163 ;
     RECT  20.268 15.061 20.286 15.179 ;
     RECT  40.032 14.675 40.497 15.215 ;
     RECT  18.615 9.239 18.897 15.295 ;
     RECT  41.724 14.369 41.742 15.295 ;
     RECT  40.215 15.215 40.497 15.331 ;
     RECT  41.724 15.295 41.85 15.331 ;
     RECT  41.724 15.331 41.994 15.341 ;
     RECT  18.615 15.295 18.954 15.449 ;
     RECT  7.416 15.163 8.097 15.485 ;
     RECT  13.215 2.413 13.497 15.592 ;
     RECT  18.615 15.449 18.897 15.595 ;
     RECT  2.304 15.151 2.697 15.629 ;
     RECT  13.104 15.592 13.497 15.629 ;
     RECT  38.772 15.565 38.79 15.719 ;
     RECT  18.504 15.595 18.897 15.755 ;
     RECT  40.215 15.331 40.95 15.755 ;
     RECT  40.215 15.755 40.497 16.105 ;
     RECT  41.976 15.341 41.994 16.105 ;
     RECT  85.5 14.071 85.518 16.109 ;
     RECT  10.26 16.141 10.278 16.259 ;
     RECT  41.832 16.105 41.994 16.259 ;
     RECT  20.124 16.141 20.142 16.295 ;
     RECT  40.14 16.105 40.497 16.501 ;
     RECT  41.832 16.259 41.922 16.541 ;
     RECT  50.076 16.501 50.094 16.589 ;
     RECT  39.924 16.501 40.497 16.673 ;
     RECT  2.415 15.629 2.697 16.939 ;
     RECT  2.415 16.939 2.79 16.979 ;
     RECT  20.304 16.951 20.322 17.069 ;
     RECT  86.292 17.032 86.31 17.069 ;
     RECT  42.912 17.035 42.93 17.221 ;
     RECT  41.544 16.681 41.778 17.347 ;
     RECT  40.14 16.673 40.497 17.455 ;
     RECT  41.22 17.347 41.778 17.455 ;
     RECT  41.22 17.455 41.958 17.501 ;
     RECT  39.708 17.455 40.497 17.609 ;
     RECT  42.732 17.221 42.93 17.609 ;
     RECT  0.108 17.515 0.126 17.645 ;
     RECT  39.924 17.609 40.497 17.645 ;
     RECT  41.22 17.501 41.742 17.645 ;
     RECT  18.615 15.755 18.897 17.995 ;
     RECT  40.215 17.645 40.497 17.995 ;
     RECT  42.912 17.609 42.93 18.031 ;
     RECT  42.912 18.031 43.074 18.149 ;
     RECT  18.615 17.995 18.954 18.185 ;
     RECT  85.5 17.311 85.518 18.509 ;
     RECT  42.912 18.149 43.038 18.689 ;
     RECT  40.215 17.995 41.166 18.725 ;
     RECT  0.108 18.907 0.126 18.995 ;
     RECT  39.24 18.931 39.258 19.103 ;
     RECT  41.904 19.111 42.066 19.229 ;
     RECT  39.42 19.111 39.438 19.381 ;
     RECT  40.215 18.725 40.497 19.381 ;
     RECT  2.415 16.979 2.697 19.387 ;
     RECT  41.904 19.229 41.958 19.387 ;
     RECT  13.215 15.629 13.497 19.471 ;
     RECT  42.912 18.689 42.93 19.471 ;
     RECT  18.615 18.185 18.897 19.483 ;
     RECT  2.304 19.387 2.697 19.499 ;
     RECT  19.98 19.381 19.998 19.499 ;
     RECT  86.292 18.907 86.31 19.499 ;
     RECT  13.104 19.471 13.497 19.517 ;
     RECT  39.42 19.381 40.497 19.535 ;
     RECT  40.215 19.535 40.497 19.651 ;
     RECT  42.804 19.471 42.93 19.679 ;
     RECT  41.724 19.387 41.958 19.769 ;
     RECT  18.504 19.483 18.897 19.867 ;
     RECT  40.215 19.651 40.806 19.921 ;
     RECT  41.724 19.769 41.886 19.921 ;
     RECT  42.804 19.679 42.894 19.921 ;
     RECT  42.732 19.921 42.894 19.949 ;
     RECT  38.772 19.885 38.79 20.039 ;
     RECT  42.732 19.949 42.75 20.039 ;
     RECT  18.252 19.867 18.897 20.075 ;
     RECT  40.215 19.921 41.886 20.075 ;
     RECT  20.916 20.191 20.934 20.309 ;
     RECT  41.328 20.075 41.886 20.615 ;
     RECT  40.215 20.075 40.497 20.821 ;
     RECT  39.888 20.821 40.497 21.001 ;
     RECT  41.724 20.615 41.886 21.005 ;
     RECT  41.76 21.005 41.886 21.115 ;
     RECT  39.888 21.001 40.986 21.155 ;
     RECT  39.888 21.155 40.497 21.235 ;
     RECT  2.415 19.499 2.697 21.259 ;
     RECT  41.76 21.115 41.922 21.271 ;
     RECT  2.415 21.259 2.79 21.299 ;
     RECT  85.5 19.741 85.518 21.341 ;
     RECT  39.456 21.235 40.497 21.389 ;
     RECT  41.76 21.271 42.174 21.389 ;
     RECT  39.636 21.389 40.497 21.425 ;
     RECT  18.615 20.075 18.897 21.739 ;
     RECT  41.76 21.389 41.994 21.775 ;
     RECT  18.615 21.739 18.954 21.965 ;
     RECT  41.328 21.775 41.994 21.965 ;
     RECT  40.215 21.425 40.497 22.081 ;
     RECT  20.52 22.081 20.538 22.199 ;
     RECT  40.215 22.081 40.59 22.207 ;
     RECT  50.076 21.631 50.094 22.253 ;
     RECT  42.876 22.123 42.894 22.351 ;
     RECT  40.215 22.207 41.31 22.505 ;
     RECT  42.732 22.351 42.894 22.585 ;
     RECT  42.732 22.585 43.038 22.613 ;
     RECT  43.02 22.613 43.038 22.621 ;
     RECT  40.215 22.505 41.022 22.739 ;
     RECT  43.02 22.621 43.182 22.739 ;
     RECT  42.192 22.621 42.21 22.775 ;
     RECT  41.796 22.981 41.958 23.021 ;
     RECT  39.384 23.125 39.402 23.161 ;
     RECT  40.215 22.739 40.497 23.161 ;
     RECT  39.384 23.161 40.497 23.279 ;
     RECT  41.94 23.021 41.958 23.279 ;
     RECT  0.108 22.699 0.126 23.315 ;
     RECT  39.6 23.279 40.497 23.315 ;
     RECT  43.02 22.739 43.038 23.629 ;
     RECT  40.215 23.315 40.497 23.665 ;
     RECT  40.215 23.665 40.914 23.701 ;
     RECT  42.804 23.629 43.038 23.701 ;
     RECT  42.228 23.701 43.038 23.729 ;
     RECT  42.228 23.729 42.966 23.819 ;
     RECT  40.215 23.701 41.13 24.161 ;
     RECT  41.94 24.091 42.102 24.241 ;
     RECT  41.22 24.241 42.102 24.359 ;
     RECT  41.22 24.359 41.814 24.395 ;
     RECT  42.948 23.819 42.966 24.781 ;
     RECT  20.808 24.745 20.826 24.899 ;
     RECT  41.4 24.395 41.814 24.935 ;
     RECT  7.815 15.485 8.097 25.051 ;
     RECT  0.108 25.045 0.126 25.085 ;
     RECT  41.4 24.935 41.634 25.205 ;
     RECT  10.584 25.141 10.602 25.241 ;
     RECT  40.215 24.161 40.497 25.591 ;
     RECT  42.948 24.781 43.074 25.591 ;
     RECT  42.948 25.591 43.146 25.613 ;
     RECT  39.348 25.555 39.366 25.709 ;
     RECT  43.128 25.613 43.146 25.709 ;
     RECT  7.416 25.051 8.097 25.745 ;
     RECT  40.215 25.591 41.058 25.745 ;
     RECT  20.376 25.681 20.394 25.781 ;
     RECT  40.215 25.745 40.878 26.249 ;
     RECT  40.215 26.249 40.806 26.401 ;
     RECT  2.415 21.299 2.697 26.491 ;
     RECT  13.215 19.517 13.497 26.491 ;
     RECT  18.615 21.965 18.897 26.491 ;
     RECT  20.268 26.401 20.286 26.519 ;
     RECT  85.5 22.441 85.518 26.525 ;
     RECT  40.104 26.401 40.806 26.555 ;
     RECT  40.215 26.555 40.806 26.789 ;
     RECT  40.215 26.789 40.554 26.825 ;
     RECT  56.415 7.529 56.697 26.923 ;
     RECT  67.215 7.529 67.497 26.923 ;
     RECT  78.015 7.529 78.297 26.923 ;
     RECT  83.415 13.757 83.697 26.923 ;
     RECT  41.904 26.731 41.922 26.941 ;
     RECT  13.104 26.491 13.497 26.969 ;
     RECT  56.304 26.923 56.697 26.969 ;
     RECT  67.104 26.923 67.497 26.969 ;
     RECT  77.904 26.923 78.297 26.969 ;
     RECT  83.304 26.923 83.697 26.969 ;
     RECT  2.304 26.491 2.697 27.005 ;
     RECT  41.904 26.941 42.066 27.031 ;
     RECT  41.292 27.031 42.066 27.059 ;
     RECT  18.504 26.491 18.897 27.095 ;
     RECT  42.804 27.307 42.822 27.365 ;
     RECT  49.248 26.761 49.266 27.509 ;
     RECT  10.584 27.481 10.602 27.599 ;
     RECT  41.292 27.059 41.634 27.599 ;
     RECT  42.948 27.481 42.966 27.599 ;
     RECT  20.664 27.481 20.682 27.635 ;
     RECT  41.328 27.599 41.634 27.787 ;
     RECT  41.328 27.787 42.102 27.869 ;
     RECT  50.112 27.931 50.13 28.049 ;
     RECT  43.848 27.913 43.866 28.139 ;
     RECT  41.328 27.869 41.922 28.175 ;
     RECT  40.215 26.825 40.497 28.291 ;
     RECT  40.212 28.291 40.497 28.381 ;
     RECT  20.304 28.291 20.322 28.409 ;
     RECT  86.292 28.363 86.31 28.409 ;
     RECT  40.212 28.381 40.554 28.445 ;
     RECT  41.724 28.175 41.922 28.493 ;
     RECT  44.604 28.417 44.622 28.589 ;
     RECT  41.868 28.493 41.922 28.679 ;
     RECT  39.24 28.795 39.258 28.831 ;
     RECT  41.904 28.679 41.922 28.831 ;
     RECT  41.904 28.831 42.066 28.877 ;
     RECT  42.048 28.877 42.066 28.949 ;
     RECT  0.108 28.363 0.126 28.985 ;
     RECT  39.24 28.831 39.438 28.985 ;
     RECT  7.815 25.745 8.097 29.323 ;
     RECT  40.215 28.445 40.554 29.371 ;
     RECT  42.804 29.335 42.822 29.371 ;
     RECT  42.804 29.371 42.966 29.405 ;
     RECT  42.948 29.405 42.966 29.489 ;
     RECT  7.815 29.323 8.154 29.525 ;
     RECT  10.368 29.497 10.386 29.669 ;
     RECT  20.304 29.641 20.322 29.759 ;
     RECT  38.772 29.641 38.79 29.795 ;
     RECT  40.215 29.371 40.734 29.911 ;
     RECT  41.724 29.755 41.742 29.911 ;
     RECT  40.215 29.911 41.886 30.065 ;
     RECT  2.415 27.005 2.697 30.271 ;
     RECT  13.215 26.969 13.497 30.271 ;
     RECT  18.615 27.095 18.897 30.283 ;
     RECT  2.304 30.271 2.697 30.317 ;
     RECT  85.5 28.651 85.518 30.317 ;
     RECT  41.508 30.065 41.886 30.443 ;
     RECT  41.616 30.443 41.886 30.451 ;
     RECT  56.415 26.969 56.697 30.811 ;
     RECT  67.215 26.969 67.497 30.811 ;
     RECT  78.015 26.969 78.297 30.811 ;
     RECT  83.415 26.969 83.697 30.811 ;
     RECT  43.308 30.721 43.326 30.839 ;
     RECT  13.104 30.271 13.497 30.848 ;
     RECT  56.304 30.811 56.697 30.848 ;
     RECT  67.104 30.811 67.497 30.848 ;
     RECT  77.904 30.811 78.297 30.848 ;
     RECT  19.656 30.811 19.674 30.911 ;
     RECT  0.108 30.763 0.126 30.941 ;
     RECT  49.248 30.721 49.266 30.941 ;
     RECT  83.304 30.811 83.697 30.941 ;
     RECT  86.292 30.763 86.31 30.941 ;
     RECT  18.504 30.283 18.897 31.195 ;
     RECT  38.772 31.225 38.79 31.379 ;
     RECT  41.616 30.451 41.994 31.379 ;
     RECT  18.252 31.195 18.897 31.415 ;
     RECT  7.815 29.525 8.097 31.675 ;
     RECT  85.5 31.081 85.518 31.709 ;
     RECT  42.876 31.801 43.038 31.853 ;
     RECT  20.052 31.765 20.07 31.919 ;
     RECT  43.02 31.853 43.038 31.919 ;
     RECT  7.416 31.675 8.097 31.955 ;
     RECT  41.616 31.379 41.814 31.955 ;
     RECT  40.215 30.065 40.497 32.341 ;
     RECT  41.796 31.955 41.814 32.341 ;
     RECT  41.796 32.341 41.958 32.459 ;
     RECT  86.292 32.152 86.31 32.729 ;
     RECT  0.108 32.155 0.126 32.765 ;
     RECT  41.796 32.459 41.814 32.809 ;
     RECT  40.215 32.341 40.914 32.881 ;
     RECT  41.724 32.809 41.814 32.881 ;
     RECT  40.215 32.881 41.814 33.035 ;
     RECT  40.215 33.035 40.497 33.043 ;
     RECT  18.615 31.415 18.897 33.115 ;
     RECT  49.248 33.115 49.266 33.179 ;
     RECT  38.772 33.043 38.79 33.269 ;
     RECT  39.924 33.043 40.497 33.305 ;
     RECT  41.4 33.035 41.814 33.511 ;
     RECT  7.815 31.955 8.097 33.595 ;
     RECT  42.84 33.583 42.858 33.629 ;
     RECT  18.615 33.115 18.954 33.809 ;
     RECT  7.416 33.595 8.097 33.845 ;
     RECT  41.4 33.511 41.85 33.845 ;
     RECT  41.616 33.845 41.85 33.961 ;
     RECT  39.996 33.305 40.497 34.079 ;
     RECT  41.616 33.961 41.994 34.079 ;
     RECT  42.876 34.501 43.038 34.541 ;
     RECT  10.224 34.501 10.242 34.619 ;
     RECT  43.02 34.541 43.038 34.619 ;
     RECT  0.108 34.507 0.126 34.655 ;
     RECT  20.052 34.501 20.07 34.655 ;
     RECT  41.616 34.079 41.634 34.655 ;
     RECT  40.032 34.079 40.497 35.005 ;
     RECT  39.672 35.005 40.497 35.159 ;
     RECT  41.832 35.041 42.066 35.159 ;
     RECT  39.852 35.159 40.497 35.195 ;
     RECT  40.215 35.195 40.497 35.581 ;
     RECT  40.215 35.581 40.734 36.121 ;
     RECT  41.832 35.159 41.886 36.121 ;
     RECT  40.215 36.121 41.994 36.275 ;
     RECT  2.415 30.317 2.697 36.379 ;
     RECT  18.615 33.809 18.897 36.379 ;
     RECT  41.832 36.275 41.994 36.391 ;
     RECT  2.415 36.379 2.79 36.419 ;
     RECT  38.772 36.355 38.79 36.509 ;
     RECT  41.832 36.391 42.066 36.509 ;
     RECT  40.215 36.275 40.554 36.545 ;
     RECT  40.215 36.545 40.497 36.895 ;
     RECT  18.252 36.379 18.897 37.085 ;
     RECT  41.832 36.509 41.994 37.291 ;
     RECT  42.876 37.243 42.894 37.291 ;
     RECT  7.815 33.845 8.097 37.387 ;
     RECT  42.804 37.291 42.894 37.391 ;
     RECT  85.5 33.511 85.518 37.421 ;
     RECT  41.652 37.291 41.994 37.561 ;
     RECT  42.876 37.391 42.894 37.613 ;
     RECT  7.815 37.387 8.154 37.625 ;
     RECT  39.672 36.895 40.497 37.625 ;
     RECT  19.836 37.561 19.854 37.661 ;
     RECT  18.615 37.085 18.897 37.741 ;
     RECT  10.008 37.741 10.026 37.859 ;
     RECT  18.615 37.741 19.782 37.895 ;
     RECT  40.215 37.625 40.497 37.975 ;
     RECT  41.652 37.561 42.138 37.975 ;
     RECT  40.215 37.975 42.138 38.141 ;
     RECT  39.276 38.011 39.294 38.165 ;
     RECT  10.116 38.281 10.134 38.399 ;
     RECT  86.292 37.819 86.31 38.399 ;
     RECT  19.692 37.895 19.782 38.407 ;
     RECT  0.108 37.819 0.126 38.435 ;
     RECT  19.692 38.407 19.89 38.435 ;
     RECT  40.215 38.141 41.31 38.551 ;
     RECT  19.872 38.435 19.89 38.579 ;
     RECT  42.552 38.632 42.57 38.669 ;
     RECT  39.348 38.551 41.31 38.705 ;
     RECT  49.248 38.779 49.266 38.849 ;
     RECT  39.348 38.705 39.366 38.939 ;
     RECT  42.696 38.821 42.714 38.939 ;
     RECT  20.376 38.911 20.394 39.091 ;
     RECT  20.376 39.091 20.502 39.209 ;
     RECT  40.215 38.705 41.31 39.217 ;
     RECT  7.815 37.625 8.097 39.259 ;
     RECT  18.615 37.895 18.897 39.289 ;
     RECT  40.215 39.217 41.742 39.289 ;
     RECT  18.615 39.289 19.422 39.479 ;
     RECT  40.215 39.289 41.886 39.479 ;
     RECT  40.215 39.479 41.31 39.515 ;
     RECT  40.215 39.515 40.878 39.631 ;
     RECT  20.268 39.631 20.286 39.749 ;
     RECT  7.416 39.259 8.097 40.055 ;
     RECT  40.104 39.631 40.878 40.135 ;
     RECT  2.415 36.419 2.697 40.261 ;
     RECT  2.415 40.261 2.79 40.301 ;
     RECT  7.815 40.055 8.097 40.651 ;
     RECT  39.6 40.135 40.878 40.675 ;
     RECT  39.456 40.675 40.878 40.711 ;
     RECT  19.836 40.261 19.854 40.801 ;
     RECT  39.456 40.711 40.914 40.829 ;
     RECT  7.815 40.651 8.154 40.865 ;
     RECT  39.636 40.829 40.734 40.865 ;
     RECT  19.728 40.801 19.854 40.901 ;
     RECT  40.14 40.865 40.734 41.021 ;
     RECT  20.196 41.071 20.214 41.171 ;
     RECT  41.904 41.035 41.922 41.251 ;
     RECT  41.904 41.251 42.066 41.369 ;
     RECT  40.14 41.021 40.497 41.405 ;
     RECT  2.415 40.301 2.697 41.611 ;
     RECT  7.815 40.865 8.097 41.707 ;
     RECT  6.84 41.611 6.858 41.741 ;
     RECT  41.904 41.369 41.994 41.749 ;
     RECT  41.832 41.749 41.994 41.789 ;
     RECT  40.215 41.405 40.497 41.791 ;
     RECT  19.728 41.755 19.746 41.909 ;
     RECT  41.976 41.789 41.994 41.909 ;
     RECT  7.815 41.707 8.154 41.945 ;
     RECT  42.912 41.899 42.93 41.945 ;
     RECT  7.815 41.945 8.097 42.043 ;
     RECT  18.615 39.479 18.897 42.061 ;
     RECT  40.215 41.791 40.806 42.061 ;
     RECT  2.304 41.611 2.697 42.125 ;
     RECT  14.832 42.061 14.85 42.179 ;
     RECT  43.056 42.061 43.074 42.179 ;
     RECT  7.416 42.043 8.097 42.215 ;
     RECT  18.615 42.061 19.422 42.215 ;
     RECT  40.215 42.061 41.058 42.215 ;
     RECT  40.215 42.215 40.914 42.565 ;
     RECT  39.78 42.565 40.914 42.719 ;
     RECT  39.96 42.719 40.497 42.755 ;
     RECT  19.908 42.691 19.926 42.863 ;
     RECT  42.804 42.811 42.822 43.141 ;
     RECT  10.26 43.141 10.278 43.259 ;
     RECT  40.104 42.755 40.497 43.259 ;
     RECT  42.804 43.141 42.966 43.259 ;
     RECT  41.616 43.141 41.634 43.295 ;
     RECT  85.5 39.181 85.518 43.565 ;
     RECT  40.215 43.259 40.497 43.675 ;
     RECT  20.052 43.141 20.07 43.799 ;
     RECT  40.215 43.675 41.202 43.799 ;
     RECT  42.804 43.259 42.822 43.799 ;
     RECT  40.215 43.799 40.77 43.835 ;
     RECT  83.415 30.941 83.697 43.951 ;
     RECT  83.415 43.951 83.79 43.997 ;
     RECT  42.732 43.843 42.75 44.069 ;
     RECT  0.108 43.963 0.126 44.105 ;
     RECT  40.215 43.835 40.698 44.105 ;
     RECT  19.836 44.041 20.034 44.141 ;
     RECT  41.724 44.299 41.85 44.383 ;
     RECT  7.815 42.215 8.097 44.443 ;
     RECT  49.248 44.443 49.266 44.519 ;
     RECT  41.724 44.383 41.994 44.539 ;
     RECT  10.26 44.491 10.278 44.609 ;
     RECT  38.772 43.807 38.79 44.609 ;
     RECT  41.724 44.539 42.21 44.609 ;
     RECT  7.815 44.443 8.154 44.645 ;
     RECT  20.016 44.141 20.034 44.645 ;
     RECT  40.215 44.105 40.554 44.645 ;
     RECT  41.724 44.609 41.994 44.789 ;
     RECT  41.724 44.789 41.886 44.851 ;
     RECT  7.815 44.645 8.097 44.923 ;
     RECT  18.615 42.215 18.897 44.995 ;
     RECT  18.615 44.995 19.422 45.149 ;
     RECT  2.415 42.125 2.697 45.391 ;
     RECT  40.215 44.645 40.497 45.391 ;
     RECT  42.912 45.403 42.93 45.455 ;
     RECT  39.816 45.391 40.497 45.491 ;
     RECT  40.215 45.491 40.497 45.571 ;
     RECT  41.4 44.851 41.886 45.571 ;
     RECT  18.615 45.149 18.954 45.689 ;
     RECT  7.416 44.923 8.097 45.725 ;
     RECT  41.4 45.571 42.282 45.797 ;
     RECT  40.215 45.571 40.554 45.805 ;
     RECT  41.4 45.797 42.102 45.805 ;
     RECT  13.215 30.848 13.497 45.832 ;
     RECT  18.615 45.689 18.897 45.835 ;
     RECT  13.104 45.832 13.497 45.869 ;
     RECT  40.215 45.805 42.102 45.959 ;
     RECT  18.504 45.835 18.897 45.995 ;
     RECT  41.364 45.959 41.958 45.995 ;
     RECT  41.616 45.995 41.958 46.157 ;
     RECT  40.215 45.959 40.497 46.345 ;
     RECT  2.304 45.391 2.697 46.409 ;
     RECT  39.672 46.345 40.497 46.499 ;
     RECT  39.852 46.499 40.497 46.535 ;
     RECT  19.836 46.471 19.854 46.777 ;
     RECT  85.5 44.851 85.518 46.829 ;
     RECT  41.616 46.157 41.886 46.921 ;
     RECT  19.836 46.777 20.214 46.949 ;
     RECT  19.836 46.949 20.034 47.039 ;
     RECT  2.415 46.409 2.697 47.179 ;
     RECT  7.704 45.725 8.097 47.179 ;
     RECT  18.615 45.995 18.897 47.191 ;
     RECT  2.415 47.179 2.79 47.219 ;
     RECT  40.176 46.535 40.497 47.281 ;
     RECT  14.832 47.191 14.85 47.309 ;
     RECT  86.292 47.272 86.31 47.309 ;
     RECT  42.876 47.275 42.894 47.315 ;
     RECT  7.416 47.179 8.097 47.345 ;
     RECT  18.615 47.191 19.422 47.345 ;
     RECT  39.924 47.281 40.497 47.453 ;
     RECT  41.616 46.921 41.994 47.461 ;
     RECT  40.215 47.453 40.497 47.695 ;
     RECT  41.616 47.461 42.246 47.695 ;
     RECT  10.476 47.731 10.494 47.849 ;
     RECT  40.215 47.695 42.246 47.849 ;
     RECT  0.108 47.755 0.126 47.885 ;
     RECT  20.556 47.731 20.574 47.885 ;
     RECT  41.22 47.849 41.238 47.885 ;
     RECT  41.976 47.849 42.174 48.155 ;
     RECT  18.615 47.345 18.897 48.235 ;
     RECT  40.215 47.849 40.497 48.235 ;
     RECT  42.156 48.155 42.174 48.389 ;
     RECT  18.615 48.235 18.954 48.425 ;
     RECT  40.104 48.235 40.497 48.619 ;
     RECT  7.815 47.345 8.097 48.715 ;
     RECT  19.98 48.667 19.998 48.775 ;
     RECT  40.104 48.619 40.77 48.811 ;
     RECT  19.8 48.775 19.998 48.929 ;
     RECT  39.744 48.811 40.914 48.929 ;
     RECT  7.815 48.715 8.154 48.965 ;
     RECT  39.744 48.929 40.497 48.965 ;
     RECT  20.304 49.081 20.322 49.199 ;
     RECT  41.976 49.195 41.994 49.207 ;
     RECT  85.5 47.551 85.518 49.229 ;
     RECT  38.772 49.081 38.79 49.235 ;
     RECT  41.94 49.207 41.994 49.351 ;
     RECT  49.32 49.549 49.338 49.613 ;
     RECT  41.292 49.351 41.994 49.621 ;
     RECT  2.415 47.219 2.697 49.675 ;
     RECT  86.292 49.579 86.31 49.709 ;
     RECT  13.215 45.869 13.497 49.711 ;
     RECT  18.615 48.425 18.897 49.723 ;
     RECT  2.304 49.675 2.697 49.739 ;
     RECT  41.292 49.621 42.102 49.739 ;
     RECT  13.104 49.711 13.497 49.757 ;
     RECT  18.504 49.723 18.897 49.775 ;
     RECT  41.94 49.739 41.958 49.775 ;
     RECT  40.215 48.965 40.497 49.963 ;
     RECT  40.215 49.963 40.77 49.981 ;
     RECT  7.815 48.965 8.097 50.107 ;
     RECT  38.772 50.125 38.79 50.279 ;
     RECT  39.924 49.981 40.77 50.279 ;
     RECT  7.416 50.107 8.097 50.315 ;
     RECT  39.924 50.279 40.497 50.315 ;
     RECT  19.728 50.251 19.746 50.351 ;
     RECT  20.268 50.431 20.286 50.549 ;
     RECT  41.832 50.539 41.85 50.557 ;
     RECT  40.032 50.315 40.497 50.585 ;
     RECT  41.796 50.557 41.85 50.701 ;
     RECT  41.796 50.701 41.994 50.819 ;
     RECT  41.796 50.819 41.886 50.971 ;
     RECT  20.844 50.971 20.862 51.089 ;
     RECT  43.74 50.971 43.758 51.089 ;
     RECT  48.564 50.971 48.582 51.089 ;
     RECT  41.22 50.971 41.886 51.125 ;
     RECT  41.652 51.125 41.886 51.359 ;
     RECT  41.652 51.359 41.67 51.395 ;
     RECT  40.215 50.585 40.497 51.475 ;
     RECT  2.415 49.739 2.697 51.499 ;
     RECT  39.888 51.475 40.497 51.511 ;
     RECT  2.415 51.499 2.79 51.539 ;
     RECT  10.224 51.511 10.242 51.629 ;
     RECT  39.888 51.511 40.77 51.629 ;
     RECT  19.944 51.511 19.962 51.665 ;
     RECT  40.068 51.629 40.59 51.665 ;
     RECT  7.815 50.315 8.097 52.027 ;
     RECT  42.48 52.015 42.498 52.051 ;
     RECT  42.48 52.051 42.642 52.061 ;
     RECT  85.5 49.981 85.518 52.061 ;
     RECT  42.624 52.061 42.642 52.169 ;
     RECT  40.215 51.665 40.59 52.549 ;
     RECT  40.215 52.549 40.662 52.591 ;
     RECT  49.248 52.507 49.266 52.619 ;
     RECT  40.215 52.591 40.806 52.709 ;
     RECT  7.815 52.027 8.154 52.745 ;
     RECT  40.215 52.709 40.554 52.745 ;
     RECT  20.844 52.861 20.862 52.979 ;
     RECT  41.292 52.861 41.31 52.981 ;
     RECT  7.815 52.745 8.097 52.987 ;
     RECT  18.615 49.775 18.897 52.987 ;
     RECT  41.292 52.981 41.634 53.015 ;
     RECT  85.5 52.951 85.518 53.021 ;
     RECT  41.616 53.015 41.634 53.131 ;
     RECT  18.615 52.987 19.422 53.249 ;
     RECT  7.416 52.987 8.097 53.285 ;
     RECT  10.26 53.401 10.278 53.519 ;
     RECT  86.292 53.419 86.31 53.519 ;
     RECT  0.108 53.419 0.126 53.555 ;
     RECT  20.052 53.401 20.07 53.555 ;
     RECT  42.912 53.515 42.93 53.555 ;
     RECT  45.615 2.831 45.897 53.671 ;
     RECT  41.616 53.131 41.778 53.755 ;
     RECT  44.892 53.671 45.897 53.789 ;
     RECT  48.564 53.671 48.582 53.789 ;
     RECT  41.616 53.755 41.814 53.941 ;
     RECT  42.732 53.671 42.75 54.059 ;
     RECT  85.5 53.761 85.518 54.413 ;
     RECT  41.436 53.941 41.814 54.599 ;
     RECT  40.215 52.745 40.497 54.751 ;
     RECT  41.796 54.599 41.814 54.751 ;
     RECT  38.772 53.905 38.79 54.869 ;
     RECT  41.796 54.751 42.174 54.869 ;
     RECT  49.32 54.679 49.338 54.893 ;
     RECT  40.215 54.751 40.554 54.905 ;
     RECT  2.415 51.539 2.697 55.381 ;
     RECT  86.292 55.339 86.31 55.409 ;
     RECT  2.415 55.381 2.79 55.421 ;
     RECT  39.24 55.381 39.258 55.553 ;
     RECT  41.796 54.869 41.958 55.679 ;
     RECT  18.615 53.249 18.897 55.819 ;
     RECT  45.615 53.789 45.897 55.921 ;
     RECT  18.252 55.819 18.897 55.985 ;
     RECT  39.276 55.561 39.438 56.021 ;
     RECT  45.036 55.921 45.897 56.021 ;
     RECT  43.848 55.831 43.866 56.093 ;
     RECT  39.348 56.021 39.438 56.101 ;
     RECT  40.215 54.905 40.497 56.101 ;
     RECT  42.948 55.867 42.966 56.101 ;
     RECT  10.26 56.101 10.278 56.219 ;
     RECT  39.348 56.101 40.95 56.219 ;
     RECT  20.052 56.101 20.07 56.255 ;
     RECT  39.492 56.219 40.497 56.255 ;
     RECT  41.796 55.679 41.814 56.641 ;
     RECT  2.415 55.421 2.697 56.731 ;
     RECT  7.815 53.285 8.097 56.731 ;
     RECT  20.844 56.641 20.862 56.759 ;
     RECT  41.22 56.641 41.814 56.795 ;
     RECT  18.615 55.985 18.897 56.875 ;
     RECT  42.948 56.101 43.146 56.909 ;
     RECT  41.58 56.795 41.814 56.911 ;
     RECT  18.615 56.875 19.422 57.029 ;
     RECT  7.416 56.731 8.097 57.065 ;
     RECT  40.215 56.255 40.497 57.145 ;
     RECT  13.215 49.757 13.497 57.163 ;
     RECT  18.615 57.029 18.897 57.163 ;
     RECT  13.104 57.163 13.497 57.209 ;
     RECT  2.304 56.731 2.697 57.245 ;
     RECT  85.5 55.651 85.518 57.245 ;
     RECT  43.128 56.909 43.146 57.299 ;
     RECT  18.504 57.163 18.897 57.335 ;
     RECT  41.58 56.911 42.066 57.335 ;
     RECT  45.615 56.021 45.897 57.451 ;
     RECT  40.14 57.145 40.497 57.541 ;
     RECT  41.58 57.335 41.814 57.569 ;
     RECT  45.288 57.451 45.897 57.569 ;
     RECT  40.14 57.541 40.554 57.577 ;
     RECT  40.14 57.577 40.662 57.685 ;
     RECT  39.924 57.685 40.662 57.721 ;
     RECT  10.224 57.721 10.242 57.839 ;
     RECT  39.924 57.721 40.698 57.839 ;
     RECT  20.016 57.721 20.034 57.875 ;
     RECT  40.215 57.839 40.554 57.875 ;
     RECT  41.796 57.569 41.814 58.261 ;
     RECT  49.248 57.691 49.266 58.289 ;
     RECT  38.772 58.117 38.79 58.379 ;
     RECT  40.215 57.875 40.497 58.621 ;
     RECT  39.816 58.621 40.497 58.721 ;
     RECT  41.796 58.261 41.994 58.801 ;
     RECT  41.796 58.801 42.102 59.035 ;
     RECT  41.796 59.035 42.498 59.071 ;
     RECT  40.212 58.721 40.497 59.189 ;
     RECT  41.508 59.071 42.642 59.189 ;
     RECT  0.108 59.131 0.126 59.225 ;
     RECT  18.615 57.335 18.897 59.563 ;
     RECT  41.508 59.189 41.994 59.575 ;
     RECT  18.615 59.563 18.954 59.765 ;
     RECT  40.215 59.189 40.497 59.881 ;
     RECT  41.4 59.575 41.994 59.881 ;
     RECT  20.808 59.881 20.826 59.999 ;
     RECT  43.632 59.881 43.65 59.999 ;
     RECT  48.564 59.881 48.582 59.999 ;
     RECT  40.215 59.881 41.994 60.035 ;
     RECT  41.328 60.035 41.994 60.151 ;
     RECT  41.328 60.151 42.102 60.269 ;
     RECT  41.328 60.269 41.814 60.305 ;
     RECT  41.796 60.305 41.814 60.413 ;
     RECT  2.415 57.245 2.697 60.511 ;
     RECT  85.5 58.621 85.518 60.557 ;
     RECT  7.815 57.065 8.097 60.619 ;
     RECT  6.84 60.523 6.858 60.653 ;
     RECT  20.196 60.547 20.214 60.655 ;
     RECT  40.215 60.035 40.497 60.691 ;
     RECT  42.804 60.427 42.822 60.691 ;
     RECT  20.016 60.655 20.214 60.809 ;
     RECT  7.815 60.619 8.154 60.845 ;
     RECT  40.176 60.691 40.497 60.845 ;
     RECT  7.815 60.845 8.097 61.051 ;
     RECT  86.292 61.003 86.31 61.079 ;
     RECT  7.704 61.051 8.097 61.115 ;
     RECT  20.376 61.051 20.394 61.151 ;
     RECT  42.804 60.691 42.966 61.229 ;
     RECT  40.215 60.845 40.497 61.231 ;
     RECT  42.948 61.229 42.966 61.349 ;
     RECT  13.215 57.209 13.497 61.483 ;
     RECT  18.615 59.765 18.897 61.483 ;
     RECT  56.415 30.848 56.697 61.483 ;
     RECT  67.215 30.848 67.497 61.483 ;
     RECT  78.015 30.848 78.297 61.483 ;
     RECT  2.304 60.511 2.697 61.529 ;
     RECT  13.104 61.483 13.497 61.529 ;
     RECT  56.304 61.483 56.697 61.529 ;
     RECT  67.104 61.483 67.497 61.529 ;
     RECT  77.904 61.483 78.297 61.529 ;
     RECT  50.076 61.387 50.094 61.619 ;
     RECT  20.196 61.591 20.214 61.691 ;
     RECT  40.215 61.231 40.914 61.771 ;
     RECT  41.832 61.579 41.85 61.771 ;
     RECT  40.215 61.771 41.85 61.925 ;
     RECT  41.328 61.925 41.85 62.041 ;
     RECT  40.215 61.925 40.554 62.159 ;
     RECT  18.252 61.483 18.897 62.195 ;
     RECT  41.328 62.041 41.994 62.195 ;
     RECT  41.508 62.195 41.994 62.395 ;
     RECT  41.508 62.395 42.21 62.435 ;
     RECT  85.5 61.861 85.518 62.477 ;
     RECT  41.508 62.435 41.886 62.621 ;
     RECT  44.352 62.581 44.37 62.699 ;
     RECT  10.116 62.851 10.134 62.969 ;
     RECT  86.292 62.875 86.31 62.969 ;
     RECT  42.768 62.941 42.786 62.971 ;
     RECT  19.8 62.851 19.818 62.977 ;
     RECT  0.108 62.875 0.126 63.005 ;
     RECT  19.8 62.977 19.998 63.005 ;
     RECT  42.768 62.971 42.93 63.011 ;
     RECT  42.768 63.011 42.786 63.113 ;
     RECT  41.508 62.621 41.814 63.121 ;
     RECT  19.98 63.005 19.998 63.149 ;
     RECT  41.4 63.121 41.814 63.247 ;
     RECT  18.615 62.195 18.897 63.355 ;
     RECT  40.215 62.159 40.497 63.355 ;
     RECT  49.32 63.247 49.338 63.389 ;
     RECT  41.328 63.247 41.814 63.391 ;
     RECT  41.328 63.391 42.066 63.509 ;
     RECT  18.615 63.355 18.954 63.545 ;
     RECT  20.484 63.661 20.502 63.779 ;
     RECT  50.076 63.823 50.094 63.869 ;
     RECT  41.328 63.509 41.958 64.085 ;
     RECT  40.215 63.355 40.554 64.291 ;
     RECT  7.815 61.115 8.097 64.315 ;
     RECT  39.708 64.291 40.554 64.315 ;
     RECT  18.615 63.545 18.897 64.327 ;
     RECT  18.615 64.327 18.954 64.589 ;
     RECT  7.416 64.315 8.097 64.625 ;
     RECT  39.708 64.315 40.914 64.705 ;
     RECT  41.904 64.085 41.958 64.741 ;
     RECT  2.415 61.529 2.697 64.795 ;
     RECT  13.215 61.529 13.497 64.831 ;
     RECT  18.615 64.589 18.897 64.843 ;
     RECT  39.168 64.705 40.914 64.859 ;
     RECT  41.904 64.741 42.066 64.859 ;
     RECT  18.504 64.843 18.897 64.895 ;
     RECT  39.384 64.859 40.914 64.895 ;
     RECT  41.904 64.859 41.994 65.131 ;
     RECT  40.032 64.895 40.914 65.281 ;
     RECT  41.832 65.131 41.994 65.281 ;
     RECT  2.304 64.795 2.697 65.309 ;
     RECT  40.032 65.281 41.994 65.399 ;
     RECT  10.224 65.371 10.242 65.407 ;
     RECT  10.08 65.407 10.242 65.408 ;
     RECT  13.104 64.831 13.497 65.408 ;
     RECT  20.052 65.371 20.07 65.435 ;
     RECT  6.84 65.275 6.858 65.453 ;
     RECT  10.08 65.408 10.098 65.453 ;
     RECT  20.808 65.551 20.826 65.669 ;
     RECT  42.804 65.659 42.822 65.821 ;
     RECT  40.215 65.399 41.382 65.975 ;
     RECT  42.804 65.821 42.966 66.181 ;
     RECT  42.804 66.181 43.002 66.209 ;
     RECT  85.5 64.291 85.518 66.221 ;
     RECT  42.984 66.209 43.002 66.361 ;
     RECT  42.984 66.361 43.146 66.479 ;
     RECT  51.015 10.925 51.297 66.523 ;
     RECT  83.415 43.997 83.697 66.631 ;
     RECT  51.015 66.523 51.39 66.653 ;
     RECT  83.415 66.631 83.79 66.701 ;
     RECT  50.112 66.523 50.13 66.749 ;
     RECT  10.116 66.757 10.35 66.797 ;
     RECT  20.16 66.757 20.178 66.797 ;
     RECT  40.215 65.975 40.95 66.901 ;
     RECT  18.615 64.895 18.897 67.147 ;
     RECT  42.984 66.479 43.002 67.171 ;
     RECT  44.424 67.171 44.442 67.289 ;
     RECT  41.976 67.261 41.994 67.361 ;
     RECT  42.84 67.171 43.002 67.405 ;
     RECT  42.768 67.405 43.002 67.433 ;
     RECT  40.215 66.901 41.022 67.675 ;
     RECT  40.14 67.675 41.022 67.711 ;
     RECT  42.768 67.433 42.786 67.711 ;
     RECT  40.14 67.711 41.634 67.829 ;
     RECT  18.252 67.147 18.897 67.865 ;
     RECT  44.784 67.981 44.802 68.099 ;
     RECT  48.564 67.981 48.582 68.099 ;
     RECT  40.215 67.829 41.634 68.135 ;
     RECT  85.5 66.991 85.518 68.141 ;
     RECT  42.624 67.711 42.786 68.251 ;
     RECT  40.215 68.135 41.562 68.405 ;
     RECT  40.215 68.405 41.058 68.611 ;
     RECT  86.292 68.587 86.31 68.639 ;
     RECT  10.224 68.611 10.242 68.669 ;
     RECT  0.108 68.587 0.126 68.675 ;
     RECT  20.052 68.635 20.07 68.675 ;
     RECT  40.032 68.611 41.058 68.711 ;
     RECT  42.408 68.251 42.786 68.957 ;
     RECT  50.112 69.019 50.13 69.089 ;
     RECT  39.348 68.953 39.366 69.179 ;
     RECT  42.228 69.061 42.246 69.179 ;
     RECT  40.215 68.711 41.058 69.215 ;
     RECT  38.772 69.421 38.79 69.521 ;
     RECT  41.292 69.421 41.31 69.565 ;
     RECT  41.292 69.565 41.994 70.295 ;
     RECT  40.215 69.215 40.497 70.375 ;
     RECT  2.415 65.309 2.697 70.501 ;
     RECT  2.415 70.501 2.79 70.541 ;
     RECT  40.104 70.375 40.497 70.915 ;
     RECT  41.724 70.295 41.994 70.951 ;
     RECT  41.724 70.951 42.066 71.069 ;
     RECT  43.092 71.275 43.11 71.339 ;
     RECT  7.815 64.625 8.097 71.419 ;
     RECT  39.888 70.915 40.497 71.455 ;
     RECT  10.116 71.491 10.134 71.609 ;
     RECT  39.492 71.455 40.497 71.609 ;
     RECT  43.236 71.491 43.254 71.609 ;
     RECT  7.815 71.419 8.154 71.645 ;
     RECT  19.8 71.491 19.818 71.645 ;
     RECT  39.708 71.609 40.497 71.645 ;
     RECT  2.415 70.541 2.697 71.851 ;
     RECT  13.215 65.408 13.497 71.851 ;
     RECT  18.615 67.865 18.897 71.851 ;
     RECT  41.724 71.069 41.742 72.031 ;
     RECT  18.504 71.851 18.897 72.283 ;
     RECT  41.616 72.031 41.886 72.301 ;
     RECT  13.104 71.851 13.497 72.329 ;
     RECT  2.304 71.851 2.697 72.365 ;
     RECT  38.772 72.265 38.79 72.419 ;
     RECT  18.252 72.283 18.897 72.455 ;
     RECT  41.616 72.301 41.994 72.599 ;
     RECT  40.215 71.645 40.497 72.805 ;
     RECT  41.616 72.599 41.67 72.805 ;
     RECT  7.815 71.645 8.097 72.811 ;
     RECT  18.615 72.455 18.897 72.841 ;
     RECT  40.215 72.805 40.77 72.841 ;
     RECT  41.508 72.805 41.67 72.841 ;
     RECT  14.832 72.841 14.85 72.959 ;
     RECT  40.215 72.841 41.67 72.959 ;
     RECT  7.416 72.811 8.097 72.995 ;
     RECT  18.615 72.841 19.422 72.995 ;
     RECT  40.215 72.959 41.31 72.995 ;
     RECT  40.215 72.995 40.986 73.345 ;
     RECT  10.224 73.381 10.242 73.499 ;
     RECT  39.888 73.345 40.986 73.499 ;
     RECT  19.944 73.381 19.962 73.535 ;
     RECT  40.068 73.499 40.95 73.535 ;
     RECT  85.5 69.421 85.518 73.805 ;
     RECT  41.832 73.885 41.85 73.921 ;
     RECT  41.832 73.921 41.994 73.949 ;
     RECT  86.292 74.251 86.31 74.309 ;
     RECT  20.376 74.281 20.394 74.381 ;
     RECT  41.976 73.949 41.994 74.461 ;
     RECT  83.415 66.701 83.697 74.659 ;
     RECT  42.984 74.251 43.002 74.669 ;
     RECT  49.32 74.623 49.338 74.687 ;
     RECT  40.215 73.535 40.95 74.731 ;
     RECT  41.976 74.461 42.21 74.731 ;
     RECT  83.415 74.659 83.79 74.765 ;
     RECT  41.976 74.731 42.75 74.849 ;
     RECT  0.108 74.251 0.126 74.885 ;
     RECT  10.368 74.857 10.386 75.029 ;
     RECT  41.976 74.849 42.066 75.157 ;
     RECT  40.215 74.731 41.058 75.259 ;
     RECT  41.868 75.157 42.066 75.259 ;
     RECT  40.215 75.259 42.066 75.505 ;
     RECT  2.415 72.365 2.697 75.631 ;
     RECT  7.815 72.995 8.097 75.643 ;
     RECT  39.6 75.505 42.066 75.659 ;
     RECT  41.544 75.659 41.85 75.695 ;
     RECT  19.836 75.631 19.854 75.731 ;
     RECT  42.804 75.931 42.822 75.971 ;
     RECT  10.224 76.081 10.242 76.199 ;
     RECT  39.816 75.659 40.497 76.199 ;
     RECT  42.948 76.081 42.966 76.199 ;
     RECT  7.704 75.643 8.097 76.235 ;
     RECT  19.944 76.081 19.962 76.235 ;
     RECT  40.032 76.199 40.497 76.235 ;
     RECT  40.215 76.235 40.497 76.585 ;
     RECT  13.215 72.329 13.497 76.603 ;
     RECT  18.615 72.995 18.897 76.603 ;
     RECT  40.215 76.585 40.806 76.621 ;
     RECT  41.832 75.695 41.85 76.621 ;
     RECT  2.304 75.631 2.697 76.649 ;
     RECT  13.104 76.603 13.497 76.649 ;
     RECT  41.832 76.621 41.994 76.739 ;
     RECT  18.504 76.603 18.897 76.775 ;
     RECT  40.215 76.621 41.022 76.775 ;
     RECT  40.215 76.775 40.497 77.125 ;
     RECT  39.672 77.125 40.497 77.279 ;
     RECT  39.852 77.279 40.497 77.315 ;
     RECT  85.5 75.091 85.518 77.597 ;
     RECT  41.832 76.739 41.886 77.701 ;
     RECT  41.328 77.701 41.994 77.819 ;
     RECT  41.328 77.819 41.346 77.855 ;
     RECT  7.815 76.235 8.097 77.947 ;
     RECT  18.615 76.775 18.897 77.971 ;
     RECT  40.215 77.315 40.497 78.061 ;
     RECT  0.108 77.947 0.126 78.077 ;
     RECT  14.832 77.971 14.85 78.089 ;
     RECT  86.292 78.043 86.31 78.089 ;
     RECT  7.416 77.947 8.097 78.125 ;
     RECT  18.615 77.971 19.422 78.125 ;
     RECT  42.984 78.043 43.002 78.241 ;
     RECT  42.768 78.241 43.002 78.359 ;
     RECT  40.215 78.061 41.058 78.395 ;
     RECT  7.815 78.125 8.097 78.475 ;
     RECT  40.215 78.395 40.806 78.475 ;
     RECT  42.876 78.359 43.002 78.511 ;
     RECT  39.672 78.475 40.806 78.629 ;
     RECT  42.876 78.511 43.074 78.629 ;
     RECT  39.852 78.629 40.806 78.665 ;
     RECT  19.836 78.601 19.854 78.701 ;
     RECT  42.876 78.629 43.038 79.085 ;
     RECT  20.34 78.907 20.538 79.169 ;
     RECT  43.02 79.085 43.038 79.169 ;
     RECT  7.815 78.475 8.154 79.205 ;
     RECT  40.215 78.665 40.806 79.321 ;
     RECT  20.808 79.321 20.826 79.439 ;
     RECT  85.5 78.331 85.518 79.469 ;
     RECT  40.215 79.321 41.13 79.591 ;
     RECT  41.94 79.435 41.958 79.591 ;
     RECT  44.388 79.447 44.406 79.619 ;
     RECT  2.415 76.649 2.697 79.915 ;
     RECT  86.292 79.819 86.31 79.949 ;
     RECT  7.815 79.205 8.097 79.963 ;
     RECT  40.215 79.591 42.102 79.979 ;
     RECT  40.215 79.979 41.742 80.015 ;
     RECT  42.948 80.329 42.966 80.381 ;
     RECT  56.415 61.529 56.697 80.392 ;
     RECT  67.215 61.529 67.497 80.392 ;
     RECT  78.015 61.529 78.297 80.392 ;
     RECT  2.304 79.915 2.697 80.429 ;
     RECT  56.304 80.392 56.697 80.429 ;
     RECT  67.104 80.392 67.497 80.429 ;
     RECT  77.904 80.392 78.297 80.429 ;
     RECT  39.348 79.753 39.366 80.519 ;
     RECT  43.128 80.401 43.146 80.519 ;
     RECT  7.704 79.963 8.097 80.555 ;
     RECT  49.248 79.819 49.266 80.573 ;
     RECT  20.448 79.951 20.466 80.663 ;
     RECT  18.615 78.125 18.897 80.875 ;
     RECT  40.215 80.015 41.058 80.905 ;
     RECT  41.796 80.731 41.814 80.905 ;
     RECT  40.215 80.905 41.814 80.941 ;
     RECT  40.215 80.941 41.958 81.059 ;
     RECT  18.252 80.875 18.897 81.095 ;
     RECT  40.215 81.059 41.346 81.095 ;
     RECT  42.48 81.175 42.642 81.245 ;
     RECT  38.772 81.175 38.79 81.329 ;
     RECT  42.624 81.245 42.642 81.329 ;
     RECT  85.5 80.761 85.518 81.341 ;
     RECT  40.215 81.095 40.698 81.365 ;
     RECT  10.368 81.337 10.386 81.509 ;
     RECT  2.415 80.429 2.697 81.739 ;
     RECT  40.215 81.365 40.497 81.751 ;
     RECT  2.415 81.739 2.79 81.779 ;
     RECT  20.268 81.751 20.286 81.869 ;
     RECT  86.292 81.787 86.31 81.869 ;
     RECT  40.032 81.751 40.497 81.905 ;
     RECT  41.724 81.835 41.742 81.905 ;
     RECT  7.815 80.555 8.097 82.267 ;
     RECT  42.876 82.291 43.038 82.349 ;
     RECT  40.215 81.905 40.497 82.381 ;
     RECT  41.868 82.021 41.886 82.381 ;
     RECT  43.02 82.349 43.038 82.409 ;
     RECT  7.815 82.267 8.154 82.445 ;
     RECT  20.484 82.381 20.502 82.481 ;
     RECT  41.868 82.381 42.102 82.651 ;
     RECT  18.615 81.095 18.897 82.747 ;
     RECT  41.76 82.651 42.102 82.831 ;
     RECT  41.76 82.831 42.174 82.949 ;
     RECT  18.615 82.747 18.954 82.985 ;
     RECT  40.215 82.381 40.986 83.191 ;
     RECT  41.76 82.949 42.066 83.191 ;
     RECT  7.815 82.445 8.097 83.227 ;
     RECT  50.076 83.191 50.094 83.261 ;
     RECT  42.804 83.335 42.822 83.371 ;
     RECT  20.664 83.335 20.682 83.489 ;
     RECT  7.815 83.227 8.154 83.525 ;
     RECT  40.215 83.191 42.066 83.759 ;
     RECT  42.804 83.371 42.966 83.759 ;
     RECT  42.804 83.759 42.822 83.789 ;
     RECT  41.364 83.759 42.066 83.795 ;
     RECT  40.215 83.759 40.497 84.145 ;
     RECT  39.816 84.145 40.497 84.299 ;
     RECT  41.76 83.795 41.994 84.299 ;
     RECT  0.108 83.707 0.126 84.335 ;
     RECT  40.032 84.299 40.497 84.335 ;
     RECT  38.772 84.541 38.79 84.713 ;
     RECT  42.876 84.721 42.894 84.797 ;
     RECT  20.232 84.685 20.25 84.991 ;
     RECT  20.232 84.991 20.322 85.109 ;
     RECT  85.5 82.111 85.518 85.133 ;
     RECT  41.76 84.299 41.85 85.261 ;
     RECT  40.212 84.335 40.497 85.531 ;
     RECT  2.415 81.779 2.697 85.621 ;
     RECT  20.196 85.531 20.214 85.649 ;
     RECT  86.292 85.579 86.31 85.649 ;
     RECT  2.415 85.621 2.79 85.661 ;
     RECT  39.996 85.531 40.497 85.685 ;
     RECT  40.215 85.685 40.497 85.801 ;
     RECT  41.76 85.261 41.958 85.801 ;
     RECT  40.215 85.801 41.958 85.853 ;
     RECT  49.248 86.059 49.266 86.099 ;
     RECT  10.224 86.071 10.242 86.189 ;
     RECT  38.772 86.035 38.79 86.189 ;
     RECT  20.016 86.071 20.034 86.225 ;
     RECT  40.215 85.853 40.986 86.225 ;
     RECT  41.724 85.853 41.958 86.395 ;
     RECT  41.724 86.395 42.246 86.459 ;
     RECT  7.815 83.525 8.097 86.539 ;
     RECT  39.348 86.575 39.366 86.729 ;
     RECT  42.768 86.683 42.786 86.729 ;
     RECT  44.424 86.611 44.442 86.729 ;
     RECT  7.416 86.539 8.097 86.765 ;
     RECT  20.484 86.701 20.502 86.801 ;
     RECT  20.52 86.881 20.538 86.999 ;
     RECT  41.724 86.459 41.994 87.151 ;
     RECT  40.215 86.225 40.662 87.385 ;
     RECT  40.032 87.385 40.662 87.421 ;
     RECT  41.4 87.151 41.994 87.421 ;
     RECT  40.032 87.421 41.994 87.539 ;
     RECT  0.108 87.499 0.126 87.575 ;
     RECT  40.14 87.539 41.742 87.575 ;
     RECT  42.804 87.787 42.822 87.817 ;
     RECT  42.768 87.817 42.822 87.961 ;
     RECT  85.5 86.431 85.518 87.965 ;
     RECT  10.26 87.961 10.278 88.079 ;
     RECT  40.14 87.575 40.497 88.079 ;
     RECT  42.768 87.961 42.966 88.079 ;
     RECT  20.124 87.961 20.142 88.115 ;
     RECT  42.768 88.079 42.93 88.349 ;
     RECT  40.215 88.079 40.497 88.465 ;
     RECT  40.215 88.465 40.878 88.501 ;
     RECT  41.724 87.575 41.742 88.501 ;
     RECT  49.248 88.411 49.266 88.529 ;
     RECT  42.912 88.349 42.93 88.619 ;
     RECT  40.215 88.501 41.742 88.655 ;
     RECT  20.448 88.591 20.466 88.763 ;
     RECT  85.5 88.861 85.518 88.925 ;
     RECT  41.616 88.655 41.742 89.041 ;
     RECT  41.616 89.041 42.102 89.159 ;
     RECT  41.616 89.159 41.958 89.195 ;
     RECT  86.292 89.371 86.31 89.429 ;
     RECT  38.772 89.401 38.79 89.501 ;
     RECT  41.616 89.195 41.742 89.501 ;
     RECT  41.616 89.501 41.706 89.581 ;
     RECT  41.508 89.581 41.706 89.735 ;
     RECT  43.128 89.659 43.146 89.851 ;
     RECT  10.584 89.851 10.602 89.969 ;
     RECT  43.128 89.851 43.29 89.969 ;
     RECT  0.108 89.371 0.126 90.005 ;
     RECT  20.7 89.851 20.718 90.005 ;
     RECT  7.815 86.765 8.097 90.331 ;
     RECT  85.5 89.671 85.518 90.365 ;
     RECT  42.768 90.391 42.93 90.461 ;
     RECT  42.912 90.461 42.93 90.509 ;
     RECT  40.215 88.655 40.497 90.517 ;
     RECT  7.815 90.331 8.154 90.545 ;
     RECT  41.976 90.391 41.994 90.545 ;
     RECT  40.215 90.517 40.662 90.557 ;
     RECT  20.484 90.481 20.502 90.581 ;
     RECT  48.78 90.589 48.798 90.653 ;
     RECT  40.215 90.557 40.59 90.661 ;
     RECT  2.415 85.661 2.697 90.751 ;
     RECT  56.415 80.429 56.697 90.751 ;
     RECT  67.215 80.429 67.497 90.751 ;
     RECT  78.015 80.429 78.297 90.751 ;
     RECT  7.815 90.545 8.097 90.763 ;
     RECT  38.772 90.355 38.79 90.779 ;
     RECT  39.96 90.661 40.59 90.779 ;
     RECT  7.704 90.763 8.097 90.815 ;
     RECT  39.96 90.779 40.497 90.815 ;
     RECT  19.908 90.751 19.926 90.923 ;
     RECT  13.215 76.649 13.497 91.192 ;
     RECT  18.615 82.985 18.897 91.195 ;
     RECT  83.415 74.765 83.697 91.195 ;
     RECT  56.304 90.751 56.697 91.229 ;
     RECT  67.104 90.751 67.497 91.229 ;
     RECT  77.904 90.751 78.297 91.229 ;
     RECT  83.304 91.195 83.697 91.235 ;
     RECT  39.348 91.165 39.366 91.319 ;
     RECT  49.248 91.201 49.266 91.373 ;
     RECT  41.4 91.021 41.886 91.705 ;
     RECT  18.504 91.195 18.897 91.723 ;
     RECT  41.292 91.705 41.886 91.741 ;
     RECT  2.304 90.751 2.697 91.769 ;
     RECT  13.104 91.192 13.497 91.769 ;
     RECT  41.292 91.741 41.994 91.859 ;
     RECT  18.252 91.723 18.897 91.895 ;
     RECT  41.292 91.859 41.778 91.895 ;
     RECT  40.215 90.815 40.497 92.107 ;
     RECT  7.815 90.815 8.097 92.203 ;
     RECT  40.215 92.107 41.202 92.281 ;
     RECT  38.196 92.245 38.214 92.399 ;
     RECT  10.044 92.371 10.062 92.471 ;
     RECT  20.808 92.551 20.826 92.669 ;
     RECT  40.104 92.281 41.202 92.705 ;
     RECT  18.615 91.895 18.897 92.785 ;
     RECT  42.804 92.635 42.822 92.821 ;
     RECT  42.156 92.821 42.966 92.909 ;
     RECT  18.615 92.785 19.422 92.939 ;
     RECT  42.948 92.909 42.966 92.939 ;
     RECT  7.416 92.203 8.097 92.975 ;
     RECT  42.156 92.909 42.174 92.975 ;
     RECT  40.104 92.705 40.878 93.055 ;
     RECT  85.5 91.561 85.518 93.197 ;
     RECT  10.224 93.091 10.242 93.209 ;
     RECT  39.924 93.055 40.878 93.209 ;
     RECT  19.62 93.091 20.034 93.245 ;
     RECT  40.14 93.209 40.698 93.245 ;
     RECT  10.044 93.631 10.062 93.749 ;
     RECT  86.292 93.643 86.31 93.749 ;
     RECT  0.108 93.163 0.126 93.785 ;
     RECT  19.62 93.245 19.638 93.785 ;
     RECT  39.168 93.721 39.186 93.901 ;
     RECT  39.168 93.901 39.402 93.991 ;
     RECT  18.615 92.939 18.897 94.027 ;
     RECT  7.815 92.975 8.097 94.075 ;
     RECT  50.076 94.027 50.094 94.109 ;
     RECT  40.215 93.245 40.698 94.171 ;
     RECT  40.215 94.171 40.986 94.289 ;
     RECT  7.815 94.075 8.154 94.325 ;
     RECT  39.168 93.991 39.438 94.325 ;
     RECT  7.815 94.325 8.097 94.555 ;
     RECT  20.844 94.441 20.862 94.559 ;
     RECT  42.984 94.075 43.002 94.559 ;
     RECT  18.615 94.027 18.954 94.567 ;
     RECT  85.5 94.531 85.518 94.589 ;
     RECT  44.172 94.567 44.19 94.739 ;
     RECT  18.615 94.567 19.422 94.829 ;
     RECT  43.128 94.711 43.146 94.829 ;
     RECT  7.416 94.555 8.097 94.865 ;
     RECT  2.415 91.769 2.697 95.035 ;
     RECT  13.215 91.769 13.497 95.071 ;
     RECT  41.616 94.531 41.634 95.071 ;
     RECT  18.615 94.829 18.897 95.083 ;
     RECT  41.292 95.071 41.634 95.107 ;
     RECT  13.104 95.071 13.497 95.117 ;
     RECT  18.504 95.083 18.897 95.135 ;
     RECT  41.292 95.107 41.85 95.143 ;
     RECT  38.772 94.441 38.79 95.171 ;
     RECT  41.292 95.143 41.994 95.369 ;
     RECT  41.292 95.369 41.958 95.405 ;
     RECT  2.304 95.035 2.697 95.549 ;
     RECT  10.224 95.521 10.242 95.639 ;
     RECT  44.244 95.521 44.262 95.639 ;
     RECT  48.564 95.521 48.582 95.639 ;
     RECT  86.292 95.035 86.31 95.639 ;
     RECT  20.016 95.521 20.034 95.647 ;
     RECT  40.215 94.289 40.497 95.647 ;
     RECT  7.704 94.865 8.097 95.675 ;
     RECT  20.016 95.647 20.214 95.675 ;
     RECT  20.196 95.675 20.214 95.819 ;
     RECT  20.484 96.061 20.502 96.179 ;
     RECT  40.215 95.647 41.022 96.421 ;
     RECT  41.796 95.405 41.958 96.421 ;
     RECT  85.5 95.881 85.518 96.509 ;
     RECT  40.215 96.421 41.958 96.601 ;
     RECT  20.556 96.565 20.574 96.719 ;
     RECT  40.215 96.601 41.994 96.755 ;
     RECT  86.292 96.907 86.31 96.989 ;
     RECT  0.108 96.907 0.126 97.037 ;
     RECT  40.215 96.755 40.878 97.259 ;
     RECT  40.215 97.259 40.59 97.295 ;
     RECT  7.815 95.675 8.097 97.387 ;
     RECT  20.448 97.501 20.466 97.537 ;
     RECT  20.448 97.537 20.646 97.709 ;
     RECT  44.82 97.681 44.838 97.799 ;
     RECT  48.564 97.681 48.582 97.799 ;
     RECT  41.832 96.755 41.994 97.951 ;
     RECT  39.348 97.915 39.366 98.069 ;
     RECT  41.508 97.951 41.994 98.069 ;
     RECT  41.508 98.069 41.922 98.105 ;
     RECT  20.448 97.709 20.466 98.213 ;
     RECT  85.5 97.231 85.518 98.381 ;
     RECT  42.768 98.311 42.786 98.485 ;
     RECT  40.215 97.295 40.497 98.491 ;
     RECT  42.768 98.485 43.002 98.525 ;
     RECT  41.904 98.105 41.922 98.609 ;
     RECT  42.768 98.525 42.858 98.609 ;
     RECT  7.416 97.387 8.097 98.645 ;
     RECT  40.215 98.491 41.13 98.725 ;
     RECT  49.248 98.731 49.266 98.789 ;
     RECT  20.376 98.455 20.394 98.851 ;
     RECT  86.292 98.731 86.31 98.861 ;
     RECT  40.032 98.725 41.13 98.915 ;
     RECT  20.052 98.851 20.394 98.951 ;
     RECT  40.215 98.915 41.13 99.121 ;
     RECT  40.215 99.121 41.85 99.197 ;
     RECT  10.548 99.301 10.566 99.419 ;
     RECT  40.215 99.197 41.814 99.419 ;
     RECT  0.108 98.827 0.126 99.455 ;
     RECT  20.556 99.301 20.574 99.455 ;
     RECT  40.215 99.419 41.634 99.455 ;
     RECT  40.215 99.455 41.598 99.841 ;
     RECT  49.248 99.787 49.266 99.869 ;
     RECT  38.772 99.697 38.79 99.959 ;
     RECT  39.96 99.841 41.598 99.995 ;
     RECT  7.815 98.645 8.097 100.219 ;
     RECT  40.215 99.995 41.598 100.237 ;
     RECT  18.615 95.135 18.897 100.273 ;
     RECT  40.215 100.237 41.742 100.301 ;
     RECT  18.615 100.273 19.422 100.499 ;
     RECT  7.416 100.219 8.097 100.535 ;
     RECT  2.415 95.549 2.697 100.741 ;
     RECT  40.215 100.301 41.238 100.769 ;
     RECT  2.415 100.741 2.79 100.781 ;
     RECT  40.215 100.769 40.914 100.805 ;
     RECT  20.376 100.111 20.394 100.841 ;
     RECT  42.912 101.035 42.93 101.075 ;
     RECT  43.056 101.191 43.074 101.309 ;
     RECT  40.215 100.805 40.59 101.345 ;
     RECT  18.615 100.499 18.897 101.659 ;
     RECT  39.276 101.695 39.294 101.731 ;
     RECT  40.215 101.345 40.497 101.731 ;
     RECT  41.904 101.515 41.922 101.731 ;
     RECT  39.276 101.731 40.497 101.849 ;
     RECT  41.904 101.731 42.066 101.849 ;
     RECT  18.615 101.659 18.954 101.885 ;
     RECT  39.492 101.849 40.497 101.885 ;
     RECT  7.815 100.535 8.097 102.139 ;
     RECT  85.5 100.201 85.518 102.173 ;
     RECT  20.088 102.127 20.106 102.235 ;
     RECT  41.724 102.229 41.886 102.269 ;
     RECT  19.908 102.235 20.106 102.389 ;
     RECT  7.815 102.139 8.154 102.425 ;
     RECT  39.888 101.885 40.497 102.425 ;
     RECT  45.615 57.569 45.897 102.631 ;
     RECT  86.292 102.619 86.31 102.659 ;
     RECT  45.576 102.631 45.897 102.731 ;
     RECT  41.868 102.269 41.886 102.805 ;
     RECT  40.215 102.425 40.497 102.811 ;
     RECT  41.868 102.805 41.922 102.811 ;
     RECT  20.088 102.389 20.106 102.839 ;
     RECT  41.868 102.811 42.066 102.929 ;
     RECT  41.868 102.929 41.922 103.037 ;
     RECT  18.615 101.885 18.897 103.081 ;
     RECT  0.108 102.619 0.126 103.133 ;
     RECT  18.252 103.081 18.897 103.235 ;
     RECT  7.815 102.425 8.097 103.531 ;
     RECT  40.215 102.811 41.022 103.621 ;
     RECT  42.876 103.621 43.038 103.661 ;
     RECT  18.615 103.235 18.897 103.711 ;
     RECT  38.772 103.045 38.79 103.739 ;
     RECT  43.02 103.661 43.038 103.739 ;
     RECT  7.416 103.531 8.097 103.775 ;
     RECT  40.215 103.621 41.058 103.775 ;
     RECT  18.615 103.711 19.458 103.811 ;
     RECT  85.5 102.901 85.518 104.045 ;
     RECT  41.832 103.081 41.85 104.161 ;
     RECT  20.592 104.125 20.61 104.431 ;
     RECT  10.26 104.431 10.278 104.549 ;
     RECT  86.292 104.491 86.31 104.549 ;
     RECT  0.108 104.491 0.126 104.585 ;
     RECT  20.052 104.431 20.61 104.585 ;
     RECT  40.215 103.775 40.497 104.701 ;
     RECT  41.328 104.161 41.994 104.701 ;
     RECT  40.215 104.701 41.994 104.855 ;
     RECT  83.415 91.235 83.697 104.965 ;
     RECT  83.415 104.965 83.79 105.005 ;
     RECT  10.548 104.971 10.566 105.089 ;
     RECT  20.664 104.971 20.682 105.097 ;
     RECT  0.144 104.971 0.162 105.125 ;
     RECT  20.664 105.097 20.862 105.269 ;
     RECT  7.815 103.775 8.097 105.451 ;
     RECT  49.32 105.403 49.338 105.485 ;
     RECT  41.4 104.855 41.994 105.511 ;
     RECT  40.215 104.855 40.59 105.539 ;
     RECT  20.52 105.511 20.538 105.601 ;
     RECT  20.34 105.601 20.538 105.629 ;
     RECT  7.815 105.451 8.154 105.665 ;
     RECT  41.4 105.511 42.066 105.665 ;
     RECT  20.34 105.629 20.358 105.773 ;
     RECT  39.24 105.745 39.258 105.781 ;
     RECT  41.904 105.665 42.066 105.809 ;
     RECT  10.044 105.781 10.062 105.899 ;
     RECT  39.24 105.781 39.438 105.899 ;
     RECT  19.62 105.781 20.07 105.935 ;
     RECT  39.42 105.899 39.438 105.935 ;
     RECT  7.815 105.665 8.097 106.315 ;
     RECT  2.415 100.781 2.697 106.321 ;
     RECT  40.215 105.539 40.497 106.411 ;
     RECT  10.224 106.321 10.242 106.439 ;
     RECT  86.292 106.363 86.31 106.439 ;
     RECT  7.704 106.315 8.097 106.475 ;
     RECT  20.052 105.935 20.07 106.475 ;
     RECT  41.904 105.809 42.03 106.591 ;
     RECT  40.215 106.411 40.554 106.745 ;
     RECT  41.904 106.591 42.066 106.789 ;
     RECT  13.215 95.117 13.497 106.843 ;
     RECT  18.615 103.811 18.897 106.843 ;
     RECT  39.06 106.825 39.078 106.861 ;
     RECT  2.304 106.321 2.697 106.889 ;
     RECT  13.104 106.843 13.497 106.889 ;
     RECT  39.06 106.861 39.294 106.979 ;
     RECT  41.904 106.789 42.102 106.979 ;
     RECT  18.504 106.843 18.897 107.015 ;
     RECT  39.276 106.979 39.294 107.015 ;
     RECT  41.904 106.979 41.994 107.227 ;
     RECT  41.832 107.227 41.994 107.285 ;
     RECT  40.215 106.745 40.497 107.365 ;
     RECT  10.224 107.401 10.242 107.519 ;
     RECT  39.924 107.365 40.497 107.519 ;
     RECT  20.016 107.401 20.034 107.555 ;
     RECT  40.14 107.519 40.497 107.555 ;
     RECT  40.215 107.555 40.497 107.761 ;
     RECT  85.5 105.601 85.518 107.837 ;
     RECT  44.28 107.761 44.298 107.861 ;
     RECT  40.215 107.761 40.878 107.941 ;
     RECT  41.904 107.285 41.994 107.941 ;
     RECT  41.904 107.941 42.066 108.059 ;
     RECT  40.215 107.941 41.058 108.301 ;
     RECT  41.904 108.059 41.994 108.301 ;
     RECT  86.292 108.283 86.31 108.329 ;
     RECT  10.584 108.301 10.602 108.401 ;
     RECT  40.215 108.301 41.994 108.635 ;
     RECT  42.804 108.283 42.822 108.751 ;
     RECT  18.615 107.015 18.897 108.841 ;
     RECT  0.108 108.283 0.126 108.869 ;
     RECT  42.804 108.751 43.038 108.869 ;
     RECT  18.252 108.841 18.897 108.905 ;
     RECT  18.615 108.905 18.897 109.243 ;
     RECT  85.5 108.571 85.518 109.277 ;
     RECT  42.804 108.869 42.966 109.291 ;
     RECT  40.215 108.635 41.454 109.319 ;
     RECT  20.952 109.291 20.97 109.409 ;
     RECT  42.3 109.291 42.966 109.409 ;
     RECT  40.215 109.319 40.806 109.417 ;
     RECT  18.615 109.243 18.954 109.445 ;
     RECT  42.3 109.409 42.822 109.481 ;
     RECT  10.044 109.561 10.062 109.679 ;
     RECT  38.196 109.417 38.214 109.679 ;
     RECT  42.624 109.481 42.822 109.679 ;
     RECT  48.888 109.561 48.906 109.709 ;
     RECT  19.692 109.561 19.71 109.715 ;
     RECT  40.14 109.417 40.806 109.715 ;
     RECT  42.804 109.679 42.822 109.997 ;
     RECT  2.415 106.889 2.697 110.155 ;
     RECT  13.215 106.889 13.497 110.191 ;
     RECT  20.052 110.203 20.07 110.255 ;
     RECT  10.08 110.191 10.242 110.363 ;
     RECT  40.215 109.715 40.806 110.371 ;
     RECT  41.796 110.155 41.814 110.371 ;
     RECT  40.215 110.371 41.958 110.525 ;
     RECT  2.304 110.155 2.697 110.669 ;
     RECT  10.188 110.363 10.242 110.731 ;
     RECT  44.352 110.641 44.37 110.759 ;
     RECT  86.292 110.155 86.31 110.759 ;
     RECT  10.188 110.731 10.386 110.768 ;
     RECT  13.104 110.191 13.497 110.768 ;
     RECT  20.232 110.731 20.25 110.795 ;
     RECT  6.84 110.203 6.858 110.813 ;
     RECT  10.188 110.768 10.206 110.813 ;
     RECT  41.292 110.525 41.958 110.911 ;
     RECT  41.292 110.911 41.994 111.029 ;
     RECT  42.984 110.971 43.002 111.029 ;
     RECT  18.615 109.445 18.897 111.115 ;
     RECT  43.128 111.181 43.146 111.299 ;
     RECT  18.252 111.115 18.897 111.335 ;
     RECT  39.348 111.109 39.366 111.451 ;
     RECT  19.764 111.451 19.782 111.569 ;
     RECT  44.784 111.451 44.802 111.569 ;
     RECT  48.564 110.641 48.582 111.569 ;
     RECT  39.06 111.451 39.366 111.605 ;
     RECT  85.5 111.001 85.518 111.629 ;
     RECT  40.215 110.525 40.497 111.685 ;
     RECT  41.292 111.029 41.634 111.685 ;
     RECT  39.348 111.605 39.366 111.875 ;
     RECT  40.215 111.685 41.634 111.991 ;
     RECT  20.304 111.991 20.322 112.109 ;
     RECT  40.212 111.991 41.634 112.145 ;
     RECT  40.215 112.145 41.634 112.225 ;
     RECT  20.808 112.531 20.826 112.649 ;
     RECT  86.292 112.072 86.31 112.649 ;
     RECT  0.108 112.075 0.126 112.685 ;
     RECT  40.215 112.225 41.814 112.685 ;
     RECT  41.652 112.685 41.814 112.801 ;
     RECT  40.215 112.685 40.914 113.035 ;
     RECT  10.116 112.987 10.134 113.179 ;
     RECT  40.14 113.035 40.914 113.189 ;
     RECT  10.116 113.179 10.35 113.225 ;
     RECT  20.124 113.179 20.142 113.225 ;
     RECT  41.652 112.801 41.886 113.225 ;
     RECT  40.215 113.189 40.914 113.431 ;
     RECT  45.615 102.731 45.897 113.431 ;
     RECT  7.815 106.475 8.097 113.467 ;
     RECT  85.5 112.891 85.518 113.501 ;
     RECT  45.036 113.431 45.897 113.531 ;
     RECT  42.012 113.605 42.03 113.611 ;
     RECT  42.012 113.611 42.174 113.645 ;
     RECT  20.556 113.575 20.574 113.729 ;
     RECT  42.156 113.645 42.174 113.729 ;
     RECT  7.815 113.467 8.154 113.765 ;
     RECT  40.215 113.431 41.238 113.765 ;
     RECT  7.815 113.765 8.097 113.851 ;
     RECT  18.615 111.335 18.897 113.881 ;
     RECT  34.815 6.269 35.097 113.881 ;
     RECT  14.832 113.881 14.85 113.999 ;
     RECT  34.776 113.881 35.097 113.999 ;
     RECT  86.292 113.947 86.31 113.999 ;
     RECT  7.416 113.851 8.097 114.035 ;
     RECT  18.615 113.881 19.422 114.035 ;
     RECT  39.348 113.881 39.366 114.035 ;
     RECT  42.912 113.995 42.93 114.151 ;
     RECT  42.732 114.151 42.93 114.241 ;
     RECT  42.732 114.241 42.966 114.269 ;
     RECT  40.215 113.765 41.094 114.305 ;
     RECT  40.215 114.305 40.806 114.539 ;
     RECT  42.912 114.269 42.966 114.539 ;
     RECT  42.912 114.539 42.93 114.557 ;
     RECT  0.108 113.851 0.126 114.575 ;
     RECT  41.976 114.421 41.994 114.575 ;
     RECT  20.448 114.511 20.466 114.683 ;
     RECT  41.76 114.925 41.958 114.989 ;
     RECT  10.188 114.907 10.206 115.051 ;
     RECT  13.215 110.768 13.497 115.051 ;
     RECT  41.94 114.989 41.958 115.079 ;
     RECT  10.188 115.051 10.386 115.088 ;
     RECT  13.104 115.051 13.497 115.088 ;
     RECT  10.188 115.088 10.206 115.115 ;
     RECT  20.232 115.051 20.25 115.115 ;
     RECT  85.5 114.241 85.518 115.421 ;
     RECT  39.24 115.321 39.258 115.501 ;
     RECT  40.215 114.539 40.626 115.501 ;
     RECT  39.24 115.501 39.438 115.655 ;
     RECT  2.415 110.669 2.697 115.861 ;
     RECT  40.215 115.501 40.986 115.861 ;
     RECT  10.044 115.771 10.062 115.889 ;
     RECT  86.292 115.819 86.31 115.889 ;
     RECT  2.415 115.861 2.79 115.901 ;
     RECT  19.62 115.465 19.638 115.925 ;
     RECT  39.24 115.655 39.258 116.033 ;
     RECT  42.84 115.723 42.858 116.131 ;
     RECT  42.732 116.131 42.858 116.237 ;
     RECT  49.248 116.299 49.266 116.339 ;
     RECT  42.732 116.237 42.75 116.429 ;
     RECT  40.215 115.861 41.454 116.465 ;
     RECT  44.172 116.581 44.19 116.699 ;
     RECT  48.564 116.581 48.582 116.699 ;
     RECT  7.815 114.035 8.097 116.779 ;
     RECT  41.544 116.671 41.562 116.875 ;
     RECT  42.3 116.815 42.498 116.875 ;
     RECT  38.772 116.815 38.79 116.969 ;
     RECT  41.544 116.875 42.498 116.969 ;
     RECT  40.215 116.465 40.497 117.211 ;
     RECT  41.544 116.969 41.958 117.211 ;
     RECT  18.615 114.035 18.897 117.355 ;
     RECT  18.615 117.355 19.422 117.509 ;
     RECT  7.416 116.779 8.097 117.545 ;
     RECT  40.215 117.211 41.958 117.545 ;
     RECT  41.724 117.545 41.958 117.779 ;
     RECT  0.144 117.739 0.162 117.815 ;
     RECT  40.215 117.545 40.734 117.815 ;
     RECT  10.368 116.437 10.386 117.959 ;
     RECT  40.215 117.815 40.497 118.165 ;
     RECT  41.724 117.779 41.886 118.205 ;
     RECT  10.224 118.201 10.242 118.319 ;
     RECT  39.888 118.165 40.497 118.319 ;
     RECT  41.868 118.205 41.886 118.319 ;
     RECT  0.108 118.219 0.126 118.355 ;
     RECT  19.944 118.201 19.962 118.355 ;
     RECT  40.068 118.319 40.497 118.355 ;
     RECT  40.215 118.355 40.497 118.705 ;
     RECT  85.5 116.671 85.518 118.733 ;
     RECT  40.215 118.705 40.698 118.741 ;
     RECT  42.768 118.555 42.786 118.741 ;
     RECT  20.376 118.831 20.394 118.931 ;
     RECT  40.215 118.741 40.914 119.101 ;
     RECT  50.076 119.101 50.094 119.165 ;
     RECT  42.768 118.741 43.038 119.281 ;
     RECT  20.34 119.245 20.358 119.399 ;
     RECT  42.732 119.281 43.038 119.399 ;
     RECT  40.215 119.101 41.058 119.435 ;
     RECT  43.2 119.551 43.218 119.669 ;
     RECT  48.564 119.551 48.582 119.669 ;
     RECT  40.215 119.435 40.95 120.181 ;
     RECT  20.484 120.091 20.502 120.209 ;
     RECT  86.292 119.611 86.31 120.209 ;
     RECT  42.876 120.181 42.894 120.221 ;
     RECT  0.108 119.611 0.126 120.245 ;
     RECT  10.368 120.217 10.386 120.389 ;
     RECT  42.732 120.361 42.75 120.479 ;
     RECT  40.215 120.181 41.058 120.515 ;
     RECT  7.815 117.545 8.097 120.571 ;
     RECT  85.5 120.451 85.518 120.605 ;
     RECT  7.815 120.571 8.154 120.785 ;
     RECT  83.415 105.005 83.697 120.991 ;
     RECT  83.415 120.991 84.402 121.085 ;
     RECT  20.268 121.135 20.286 121.289 ;
     RECT  40.215 120.515 40.986 121.289 ;
     RECT  9.144 121.051 9.162 121.325 ;
     RECT  2.415 115.901 2.697 121.531 ;
     RECT  85.5 121.525 85.518 121.565 ;
     RECT  7.815 120.785 8.097 121.627 ;
     RECT  38.772 121.531 38.79 121.703 ;
     RECT  20.16 121.675 20.178 121.829 ;
     RECT  7.815 121.627 8.154 121.865 ;
     RECT  42.228 121.801 42.246 121.963 ;
     RECT  56.415 91.229 56.697 121.963 ;
     RECT  67.215 91.229 67.497 121.963 ;
     RECT  78.015 91.229 78.297 121.963 ;
     RECT  43.02 121.945 43.038 121.997 ;
     RECT  2.304 121.531 2.697 122.009 ;
     RECT  56.304 121.963 56.697 122.009 ;
     RECT  67.104 121.963 67.497 122.009 ;
     RECT  77.904 121.963 78.297 122.009 ;
     RECT  40.215 121.289 40.878 122.071 ;
     RECT  41.76 121.963 42.246 122.099 ;
     RECT  6.84 121.531 6.858 122.141 ;
     RECT  49.248 121.981 49.266 122.141 ;
     RECT  20.376 122.071 20.394 122.171 ;
     RECT  85.5 122.341 85.518 122.477 ;
     RECT  40.215 122.071 40.95 122.521 ;
     RECT  41.76 122.099 41.778 122.521 ;
     RECT  40.215 122.521 41.778 122.639 ;
     RECT  10.224 122.107 10.242 122.675 ;
     RECT  20.448 122.611 20.466 122.783 ;
     RECT  20.844 122.791 20.862 122.909 ;
     RECT  41.292 122.639 41.778 122.945 ;
     RECT  84.924 122.881 84.942 122.957 ;
     RECT  41.616 122.945 41.778 123.061 ;
     RECT  10.404 122.923 10.422 123.215 ;
     RECT  41.616 123.061 41.994 123.215 ;
     RECT  84.888 123.403 84.906 123.449 ;
     RECT  19.908 123.421 20.106 123.593 ;
     RECT  41.76 123.215 41.994 123.593 ;
     RECT  40.215 122.639 40.497 123.601 ;
     RECT  19.944 123.593 20.106 123.629 ;
     RECT  40.068 123.601 40.497 123.835 ;
     RECT  85.5 123.691 85.518 123.917 ;
     RECT  0.108 123.403 0.126 124.025 ;
     RECT  19.944 123.629 19.962 124.025 ;
     RECT  39.888 123.835 40.497 124.231 ;
     RECT  10.224 123.871 10.242 124.363 ;
     RECT  10.08 124.363 10.242 124.411 ;
     RECT  50.112 124.363 50.13 124.439 ;
     RECT  41.796 123.593 41.994 124.529 ;
     RECT  10.08 124.411 10.278 124.565 ;
     RECT  39.888 124.231 40.554 124.565 ;
     RECT  39.888 124.565 40.497 124.681 ;
     RECT  42.156 124.681 42.174 124.747 ;
     RECT  43.02 124.681 43.038 124.747 ;
     RECT  19.98 124.411 20.142 124.799 ;
     RECT  39.564 124.681 40.497 124.835 ;
     RECT  50.076 124.807 50.094 124.877 ;
     RECT  19.8 124.915 19.818 125.069 ;
     RECT  42.156 124.747 43.038 125.069 ;
     RECT  41.4 124.771 41.418 125.105 ;
     RECT  2.415 122.009 2.697 125.275 ;
     RECT  10.584 125.221 10.602 125.339 ;
     RECT  86.292 125.275 86.31 125.339 ;
     RECT  6.84 124.843 6.858 125.375 ;
     RECT  20.7 125.221 20.718 125.375 ;
     RECT  42.876 125.069 43.038 125.375 ;
     RECT  43.02 125.375 43.038 125.491 ;
     RECT  41.616 125.491 41.634 125.645 ;
     RECT  43.02 125.491 43.254 125.753 ;
     RECT  40.215 124.835 40.497 125.761 ;
     RECT  2.304 125.275 2.697 125.789 ;
     RECT  43.02 125.753 43.182 125.879 ;
     RECT  3.996 125.755 4.014 125.915 ;
     RECT  10.368 125.887 10.386 126.059 ;
     RECT  41.94 126.139 41.958 126.185 ;
     RECT  40.215 125.761 40.626 126.265 ;
     RECT  39.6 126.265 40.626 126.301 ;
     RECT  39.6 126.301 40.986 126.419 ;
     RECT  42.084 126.301 42.102 126.419 ;
     RECT  9.144 126.235 9.162 126.455 ;
     RECT  19.836 126.391 19.854 126.491 ;
     RECT  39.924 126.419 40.986 126.571 ;
     RECT  43.02 125.879 43.038 126.689 ;
     RECT  51.015 66.653 51.297 126.697 ;
     RECT  83.415 121.085 83.697 126.697 ;
     RECT  83.415 126.697 84.402 126.749 ;
     RECT  51.015 126.697 51.786 126.797 ;
     RECT  39.924 126.571 41.058 126.841 ;
     RECT  20.16 126.805 20.178 126.959 ;
     RECT  50.148 126.841 50.166 126.959 ;
     RECT  2.415 125.789 2.697 127.187 ;
     RECT  7.815 121.865 8.097 127.187 ;
     RECT  13.215 115.088 13.497 127.187 ;
     RECT  18.615 117.509 18.897 127.187 ;
     RECT  24.015 2.413 24.297 127.187 ;
     RECT  29.415 2.413 29.697 127.187 ;
     RECT  34.815 113.999 35.097 127.187 ;
     RECT  45.615 113.531 45.897 127.187 ;
     RECT  51.015 126.797 51.297 127.187 ;
     RECT  56.415 122.009 56.697 127.187 ;
     RECT  61.815 2.413 62.097 127.187 ;
     RECT  67.215 122.009 67.497 127.187 ;
     RECT  72.615 2.413 72.897 127.187 ;
     RECT  78.015 122.009 78.297 127.187 ;
     RECT  83.415 126.749 83.697 127.187 ;
     RECT  39.924 126.841 41.202 127.229 ;
     RECT  42.732 126.841 42.75 127.229 ;
     RECT  85.5 125.581 85.518 127.229 ;
     RECT  0.108 127.195 0.126 127.265 ;
     RECT  40.215 127.229 41.202 127.265 ;
     RECT  10.368 127.237 10.386 127.409 ;
     RECT  2.415 127.187 2.505 127.457 ;
     RECT  7.815 127.187 7.905 127.457 ;
     RECT  13.215 127.187 13.305 127.457 ;
     RECT  18.615 127.187 18.705 127.457 ;
     RECT  24.015 127.187 24.105 127.457 ;
     RECT  29.415 127.187 29.505 127.457 ;
     RECT  34.815 127.187 34.905 127.457 ;
     RECT  40.215 127.265 40.305 127.457 ;
     RECT  45.615 127.187 45.705 127.457 ;
     RECT  51.015 127.187 51.105 127.457 ;
     RECT  56.415 127.187 56.505 127.457 ;
     RECT  61.815 127.187 61.905 127.457 ;
     RECT  67.215 127.187 67.305 127.457 ;
     RECT  72.615 127.187 72.705 127.457 ;
     RECT  78.015 127.187 78.105 127.457 ;
     RECT  83.415 127.187 83.505 127.457 ;
    LAYER M4 ;
     RECT  0.06 2.4 0.137 127.224 ;
     RECT  0.137 10.416 0.173 22.248 ;
     RECT  0.137 103.536 0.173 107.832 ;
     RECT  0.137 114.912 0.173 119.16 ;
     RECT  0.137 2.88 2.408 3.336 ;
     RECT  0.137 4.752 2.408 7.128 ;
     RECT  0.137 8.544 2.408 9.048 ;
     RECT  0.173 10.416 2.408 12.792 ;
     RECT  0.173 14.208 2.408 22.248 ;
     RECT  0.137 23.664 2.408 27.96 ;
     RECT  0.137 29.328 2.408 31.704 ;
     RECT  0.137 33.12 2.408 37.416 ;
     RECT  0.137 38.784 2.408 73.8 ;
     RECT  0.137 75.168 2.408 83.256 ;
     RECT  0.137 84.624 2.408 88.92 ;
     RECT  0.137 90.336 2.408 92.712 ;
     RECT  0.137 94.08 2.408 98.376 ;
     RECT  0.137 99.792 2.408 102.168 ;
     RECT  0.173 103.536 2.408 104.04 ;
     RECT  0.173 105.456 2.408 107.832 ;
     RECT  0.137 109.248 2.408 111.624 ;
     RECT  0.137 112.992 2.408 113.88 ;
     RECT  0.173 114.912 2.408 117.288 ;
     RECT  0.173 118.704 2.408 119.16 ;
     RECT  0.137 120.576 2.408 122.952 ;
     RECT  0.137 124.368 2.408 126.744 ;
     RECT  2.408 2.148 2.512 127.452 ;
     RECT  2.512 2.418 2.704 127.182 ;
     RECT  2.704 2.88 7.808 3.336 ;
     RECT  2.704 4.752 7.808 7.128 ;
     RECT  2.704 8.544 7.808 9.048 ;
     RECT  2.704 10.416 7.808 12.792 ;
     RECT  2.704 14.208 7.808 16.968 ;
     RECT  2.704 18 7.808 18.504 ;
     RECT  2.704 19.488 7.808 22.248 ;
     RECT  2.704 23.664 7.808 27.96 ;
     RECT  2.704 29.328 7.808 31.704 ;
     RECT  2.704 33.12 7.808 37.416 ;
     RECT  2.704 38.784 7.808 47.208 ;
     RECT  2.704 48.24 7.808 73.8 ;
     RECT  2.704 75.168 7.808 83.256 ;
     RECT  2.704 84.624 7.808 88.92 ;
     RECT  2.704 90.336 7.808 92.712 ;
     RECT  2.704 94.08 7.808 98.376 ;
     RECT  2.704 99.792 7.808 102.168 ;
     RECT  2.704 103.536 7.808 104.04 ;
     RECT  2.704 105.456 7.808 107.832 ;
     RECT  2.704 109.248 7.808 111.624 ;
     RECT  2.704 112.992 7.808 113.88 ;
     RECT  2.704 114.912 7.808 117.288 ;
     RECT  2.704 118.704 7.808 119.16 ;
     RECT  2.704 120.576 7.808 122.952 ;
     RECT  2.704 124.368 7.808 126.744 ;
     RECT  7.808 2.148 7.912 127.452 ;
     RECT  7.912 2.418 8.104 127.182 ;
     RECT  8.104 10.416 8.165 10.92 ;
     RECT  8.104 29.328 8.165 31.224 ;
     RECT  8.104 33.12 8.165 37.416 ;
     RECT  8.104 40.656 8.165 41.736 ;
     RECT  8.104 44.448 8.165 44.472 ;
     RECT  8.104 48.24 8.165 52.536 ;
     RECT  8.104 58.176 8.165 63.864 ;
     RECT  8.104 76.608 8.165 79.464 ;
     RECT  8.104 80.88 8.165 83.256 ;
     RECT  8.104 90.336 8.165 91.752 ;
     RECT  8.104 94.08 8.165 94.104 ;
     RECT  8.104 101.664 8.165 102.168 ;
     RECT  8.104 105.456 8.165 105.48 ;
     RECT  8.104 112.992 8.165 113.496 ;
     RECT  8.104 120.576 8.165 122.952 ;
     RECT  8.165 121.056 9.173 121.08 ;
     RECT  8.104 126.24 9.173 126.264 ;
     RECT  8.104 124.368 10.109 124.392 ;
     RECT  8.165 112.992 10.145 113.016 ;
     RECT  8.104 2.88 10.177 3.336 ;
     RECT  8.104 109.248 10.213 109.272 ;
     RECT  8.104 110.304 10.213 111.624 ;
     RECT  8.104 114.912 10.217 114.936 ;
     RECT  8.165 122.112 10.253 122.952 ;
     RECT  10.177 2.736 10.289 3.336 ;
     RECT  8.104 4.752 10.433 7.128 ;
     RECT  10.253 122.928 10.433 122.952 ;
     RECT  10.289 3.312 13.208 3.336 ;
     RECT  10.433 4.752 13.208 6.168 ;
     RECT  8.165 10.896 13.208 10.92 ;
     RECT  8.104 12.336 13.208 12.36 ;
     RECT  8.104 14.688 13.208 16.968 ;
     RECT  8.104 18 13.208 18.504 ;
     RECT  8.104 19.488 13.208 22.248 ;
     RECT  8.104 23.664 13.208 24.168 ;
     RECT  8.104 26.016 13.208 26.952 ;
     RECT  8.104 27.936 13.208 27.96 ;
     RECT  8.165 29.808 13.208 31.224 ;
     RECT  8.165 33.12 13.208 36.936 ;
     RECT  8.165 41.136 13.208 41.16 ;
     RECT  8.104 45.84 13.208 45.864 ;
     RECT  8.165 48.24 13.208 51.096 ;
     RECT  8.104 53.904 13.208 55.848 ;
     RECT  8.104 57.168 13.208 57.192 ;
     RECT  8.165 58.176 13.208 60.072 ;
     RECT  8.165 61.488 13.208 63.864 ;
     RECT  8.104 64.848 13.208 72.312 ;
     RECT  8.104 73.776 13.208 73.8 ;
     RECT  8.104 75.168 13.208 75.192 ;
     RECT  8.165 76.608 13.208 77.592 ;
     RECT  8.165 79.44 13.208 79.464 ;
     RECT  8.165 80.88 13.208 81.768 ;
     RECT  8.165 82.752 13.208 82.776 ;
     RECT  8.104 85.104 13.208 85.656 ;
     RECT  8.104 87.024 13.208 87.048 ;
     RECT  8.104 88.896 13.208 88.92 ;
     RECT  8.165 91.2 13.208 91.752 ;
     RECT  8.104 95.088 13.208 96.024 ;
     RECT  8.104 99.792 13.208 99.816 ;
     RECT  8.165 101.664 13.208 101.688 ;
     RECT  8.104 106.848 13.208 107.832 ;
     RECT  10.213 109.248 13.208 111.624 ;
     RECT  10.321 113.184 13.208 113.208 ;
     RECT  10.357 115.056 13.208 115.08 ;
     RECT  13.208 2.148 13.312 127.452 ;
     RECT  13.312 2.418 13.504 127.182 ;
     RECT  13.504 4.752 17.129 6.168 ;
     RECT  13.504 3.312 18.608 3.336 ;
     RECT  17.129 6.144 18.608 6.168 ;
     RECT  13.504 10.896 18.608 10.92 ;
     RECT  13.504 12.336 18.608 12.36 ;
     RECT  13.504 14.688 18.608 16.968 ;
     RECT  13.504 18 18.608 18.504 ;
     RECT  13.504 19.488 18.608 22.248 ;
     RECT  13.504 23.664 18.608 24.168 ;
     RECT  13.504 26.016 18.608 26.952 ;
     RECT  13.504 27.936 18.608 27.96 ;
     RECT  13.504 29.808 18.608 31.224 ;
     RECT  13.504 33.12 18.608 36.936 ;
     RECT  13.504 41.136 18.608 41.16 ;
     RECT  13.504 45.84 18.608 45.864 ;
     RECT  13.504 48.24 18.608 51.096 ;
     RECT  13.504 53.904 18.608 55.848 ;
     RECT  13.504 57.168 18.608 57.192 ;
     RECT  13.504 58.176 18.608 60.072 ;
     RECT  13.504 61.488 18.608 63.864 ;
     RECT  13.504 64.848 18.608 72.312 ;
     RECT  13.504 73.776 18.608 73.8 ;
     RECT  13.504 75.168 18.608 75.192 ;
     RECT  13.504 76.608 18.608 77.592 ;
     RECT  13.504 79.44 18.608 79.464 ;
     RECT  13.504 80.88 18.608 81.768 ;
     RECT  13.504 82.752 18.608 82.776 ;
     RECT  13.504 85.104 18.608 85.656 ;
     RECT  13.504 87.024 18.608 87.048 ;
     RECT  13.504 88.896 18.608 88.92 ;
     RECT  13.504 91.2 18.608 91.752 ;
     RECT  13.504 95.088 18.608 96.024 ;
     RECT  13.504 99.792 18.608 99.816 ;
     RECT  13.504 101.664 18.608 101.688 ;
     RECT  13.504 106.848 18.608 107.832 ;
     RECT  13.504 109.248 18.608 111.624 ;
     RECT  13.504 113.184 18.608 113.208 ;
     RECT  13.504 115.056 18.608 115.08 ;
     RECT  18.608 2.148 18.712 127.452 ;
     RECT  18.712 2.418 18.904 127.182 ;
     RECT  18.904 18 18.965 18.024 ;
     RECT  18.904 21.744 18.965 21.768 ;
     RECT  18.904 33.12 18.965 33.144 ;
     RECT  18.904 48.24 18.965 48.264 ;
     RECT  18.904 59.568 18.965 59.592 ;
     RECT  18.904 63.36 18.965 63.384 ;
     RECT  18.904 82.752 18.965 82.776 ;
     RECT  18.904 101.664 18.965 101.688 ;
     RECT  18.904 109.248 18.965 110.76 ;
     RECT  18.904 3.312 19.433 3.336 ;
     RECT  18.904 65.376 20.081 65.4 ;
     RECT  18.904 68.64 20.081 68.664 ;
     RECT  18.965 110.208 20.081 110.76 ;
     RECT  18.904 113.184 20.153 113.208 ;
     RECT  18.904 66.768 20.189 66.792 ;
     RECT  20.081 110.736 20.261 110.76 ;
     RECT  18.904 115.056 20.261 115.08 ;
     RECT  18.904 6.144 20.513 6.168 ;
     RECT  24.008 2.148 24.112 127.452 ;
     RECT  24.112 2.418 24.304 127.182 ;
     RECT  29.408 2.148 29.512 127.452 ;
     RECT  29.512 2.418 29.704 127.182 ;
     RECT  34.808 2.148 34.912 127.452 ;
     RECT  34.912 2.418 35.104 127.182 ;
     RECT  40.208 2.148 40.312 127.452 ;
     RECT  40.312 2.418 40.504 127.182 ;
     RECT  40.504 4.656 40.691 4.68 ;
     RECT  40.504 10.272 40.691 10.728 ;
     RECT  40.504 52.56 40.691 53.016 ;
     RECT  40.504 57.6 40.691 57.624 ;
     RECT  40.504 90.048 40.691 90.552 ;
     RECT  40.504 92.112 40.732 92.952 ;
     RECT  40.691 10.272 40.787 10.296 ;
     RECT  40.504 15.648 40.787 15.672 ;
     RECT  40.504 25.92 40.787 25.944 ;
     RECT  40.504 42.432 40.787 42.456 ;
     RECT  40.504 48.624 40.787 48.648 ;
     RECT  40.504 49.968 40.787 49.992 ;
     RECT  40.504 51.552 40.787 51.576 ;
     RECT  40.691 90.048 40.787 90.072 ;
     RECT  40.504 40.992 40.789 41.016 ;
     RECT  40.504 72.816 40.853 72.984 ;
     RECT  40.504 119.616 40.883 120.456 ;
     RECT  40.504 94.032 40.931 94.056 ;
     RECT  40.504 39.696 41.027 39.72 ;
     RECT  40.504 97.152 41.027 97.176 ;
     RECT  40.504 98.736 41.027 98.76 ;
     RECT  40.504 68.832 41.033 68.856 ;
     RECT  40.504 12 41.069 12.936 ;
     RECT  40.504 43.68 41.069 43.704 ;
     RECT  40.504 100.32 41.105 100.344 ;
     RECT  40.504 38.016 41.321 38.568 ;
     RECT  40.504 5.712 41.393 5.736 ;
     RECT  40.504 111.696 41.497 111.72 ;
     RECT  40.504 112.848 41.497 112.872 ;
     RECT  41.509 75.264 41.557 75.288 ;
     RECT  40.504 85.92 41.564 85.944 ;
     RECT  40.853 72.816 41.601 72.84 ;
     RECT  40.504 79.728 41.603 79.752 ;
     RECT  41.564 85.824 41.605 85.944 ;
     RECT  40.504 115.536 41.605 115.56 ;
     RECT  41.557 75.264 41.644 75.576 ;
     RECT  40.691 52.992 41.645 53.016 ;
     RECT  41.605 114.96 41.651 115.56 ;
     RECT  40.504 95.664 41.701 95.688 ;
     RECT  41.669 28.464 41.708 28.488 ;
     RECT  40.504 64.32 41.708 64.344 ;
     RECT  41.069 12 41.713 12.552 ;
     RECT  41.708 27.888 41.713 28.488 ;
     RECT  41.713 19.392 41.749 19.416 ;
     RECT  41.653 36.912 41.749 36.936 ;
     RECT  41.321 38.016 41.749 38.136 ;
     RECT  41.669 44.976 41.749 45 ;
     RECT  41.708 63.792 41.749 64.344 ;
     RECT  41.708 81.84 41.749 81.864 ;
     RECT  41.749 44.304 41.753 45 ;
     RECT  41.605 85.296 41.753 86.664 ;
     RECT  41.605 116.88 41.753 116.904 ;
     RECT  40.504 118.176 41.753 118.2 ;
     RECT  41.701 95.136 41.785 95.688 ;
     RECT  40.504 109.392 41.785 109.416 ;
     RECT  41.701 29.76 41.788 29.784 ;
     RECT  41.605 46.224 41.788 46.248 ;
     RECT  41.701 89.472 41.788 89.496 ;
     RECT  40.504 3.408 41.789 3.432 ;
     RECT  40.504 121.968 41.789 121.992 ;
     RECT  41.649 39.264 41.795 39.288 ;
     RECT  41.749 63.792 41.795 65.16 ;
     RECT  41.749 81.84 41.795 82.68 ;
     RECT  41.569 99.168 41.795 100.296 ;
     RECT  41.708 102.24 41.795 102.264 ;
     RECT  41.756 32.976 41.797 33 ;
     RECT  41.785 109.392 41.797 110.184 ;
     RECT  41.497 111.696 41.797 112.872 ;
     RECT  41.713 11.952 41.804 12.552 ;
     RECT  41.713 15.312 41.804 15.336 ;
     RECT  41.753 85.296 41.804 86.424 ;
     RECT  41.797 6.528 41.821 6.552 ;
     RECT  41.741 51.264 41.821 51.288 ;
     RECT  41.821 50.544 41.825 51.288 ;
     RECT  41.741 60.384 41.825 60.408 ;
     RECT  41.804 84.768 41.825 86.424 ;
     RECT  41.795 82.656 41.833 82.68 ;
     RECT  41.749 53.76 41.836 53.784 ;
     RECT  41.797 109.392 41.836 112.872 ;
     RECT  41.804 11.424 41.843 12.552 ;
     RECT  41.713 20.976 41.843 21 ;
     RECT  41.756 22.992 41.843 23.016 ;
     RECT  41.797 32.976 41.843 33.96 ;
     RECT  41.836 109.392 41.843 112.344 ;
     RECT  40.504 126.576 41.843 126.6 ;
     RECT  41.749 61.584 41.845 61.608 ;
     RECT  41.804 15.312 41.852 16.152 ;
     RECT  41.749 19.392 41.852 19.944 ;
     RECT  41.713 27.792 41.852 28.488 ;
     RECT  41.749 103.728 41.852 103.752 ;
     RECT  41.651 114.96 41.853 114.984 ;
     RECT  41.777 35.328 41.855 35.352 ;
     RECT  41.845 61.584 41.857 62.184 ;
     RECT  41.855 35.088 41.861 35.352 ;
     RECT  41.749 41.76 41.861 41.784 ;
     RECT  41.753 44.304 41.861 44.568 ;
     RECT  41.795 64.56 41.861 65.16 ;
     RECT  41.777 76.368 41.861 76.392 ;
     RECT  41.852 102.816 41.861 103.752 ;
     RECT  41.785 4.512 41.869 4.536 ;
     RECT  41.821 6.528 41.884 6.84 ;
     RECT  41.797 13.536 41.884 13.56 ;
     RECT  41.843 33.936 41.884 33.96 ;
     RECT  41.797 72.288 41.884 72.312 ;
     RECT  41.797 73.92 41.884 73.944 ;
     RECT  41.843 109.392 41.884 110.904 ;
     RECT  41.797 124.416 41.884 124.44 ;
     RECT  41.804 107.232 41.885 107.256 ;
     RECT  41.804 108.336 41.89 108.36 ;
     RECT  41.749 8.496 41.891 8.52 ;
     RECT  41.843 11.424 41.891 11.448 ;
     RECT  41.852 15.312 41.891 16.536 ;
     RECT  41.804 97.92 41.891 97.944 ;
     RECT  41.804 104.832 41.891 104.856 ;
     RECT  41.885 106.608 41.891 107.256 ;
     RECT  41.89 108.288 41.891 108.36 ;
     RECT  41.884 109.392 41.891 110.184 ;
     RECT  41.891 16.512 41.893 16.536 ;
     RECT  41.749 36.912 41.893 38.136 ;
     RECT  41.797 75.168 41.897 75.192 ;
     RECT  41.701 91.728 41.897 91.752 ;
     RECT  41.884 6.816 41.905 6.84 ;
     RECT  41.795 99.168 41.925 99.672 ;
     RECT  41.893 16.512 41.939 17.496 ;
     RECT  41.852 19.152 41.939 19.944 ;
     RECT  41.852 27.792 41.939 28.872 ;
     RECT  41.785 95.136 41.939 96.12 ;
     RECT  41.925 99.648 41.939 99.672 ;
     RECT  41.852 101.52 41.939 101.544 ;
     RECT  41.861 102.816 41.939 102.84 ;
     RECT  41.891 106.608 41.969 106.632 ;
     RECT  41.893 21.12 41.977 21.672 ;
     RECT  41.939 27.792 41.977 27.96 ;
     RECT  41.939 17.472 41.98 17.496 ;
     RECT  41.861 44.448 41.987 44.568 ;
     RECT  41.825 50.544 41.987 50.568 ;
     RECT  41.857 61.584 41.987 62.616 ;
     RECT  41.929 45.696 42.013 46.152 ;
     RECT  41.825 86.064 42.013 86.424 ;
     RECT  41.941 48.096 42.028 48.12 ;
     RECT  41.941 49.2 42.028 49.224 ;
     RECT  41.843 12.528 42.035 12.552 ;
     RECT  41.861 35.088 42.035 35.112 ;
     RECT  41.893 36.432 42.035 38.136 ;
     RECT  41.893 41.04 42.035 41.064 ;
     RECT  42.013 45.696 42.035 45.72 ;
     RECT  41.977 21.648 42.083 21.672 ;
     RECT  41.929 24.096 42.083 24.12 ;
     RECT  41.855 26.736 42.083 26.76 ;
     RECT  41.821 77.712 42.083 77.736 ;
     RECT  41.929 79.44 42.083 79.464 ;
     RECT  41.977 27.792 42.113 27.816 ;
     RECT  42.035 37.248 42.149 38.136 ;
     RECT  41.987 44.544 42.221 44.568 ;
     RECT  41.987 62.4 42.221 62.616 ;
     RECT  41.721 80.736 42.469 80.76 ;
     RECT  42.013 86.4 42.659 86.424 ;
     RECT  41.891 109.632 42.659 109.992 ;
     RECT  41.843 112.32 42.659 112.344 ;
     RECT  40.504 67.248 42.685 67.8 ;
     RECT  42.289 116.832 42.757 116.856 ;
     RECT  42.757 88.32 42.764 88.344 ;
     RECT  42.757 92.64 42.793 92.664 ;
     RECT  42.685 67.248 42.797 67.848 ;
     RECT  42.757 116.208 42.803 116.856 ;
     RECT  42.803 116.208 42.829 116.232 ;
     RECT  41.939 19.488 42.833 19.944 ;
     RECT  41.891 108.288 42.833 108.312 ;
     RECT  42.764 87.792 42.841 88.344 ;
     RECT  42.757 90.432 42.841 90.456 ;
     RECT  42.757 118.56 42.841 119.112 ;
     RECT  42.793 92.64 42.844 92.904 ;
     RECT  42.764 27.312 42.851 27.336 ;
     RECT  42.764 29.376 42.851 29.4 ;
     RECT  42.469 59.04 42.851 59.064 ;
     RECT  42.757 86.688 42.851 86.712 ;
     RECT  42.841 87.792 42.851 87.816 ;
     RECT  41.857 2.832 42.853 2.856 ;
     RECT  42.793 42.816 42.853 42.84 ;
     RECT  42.805 33.6 42.86 33.624 ;
     RECT  42.221 62.592 42.86 62.616 ;
     RECT  42.289 7.056 42.869 7.08 ;
     RECT  42.797 67.248 42.869 67.272 ;
     RECT  42.829 115.728 42.869 116.232 ;
     RECT  42.793 60.432 42.877 61.224 ;
     RECT  42.793 83.76 42.877 83.784 ;
     RECT  42.844 92.88 42.877 92.904 ;
     RECT  42.86 33.6 42.892 34.536 ;
     RECT  42.648 5.184 42.899 5.208 ;
     RECT  42.853 41.904 42.899 42.84 ;
     RECT  41.893 105.312 42.899 105.336 ;
     RECT  42.469 80.736 42.901 81.24 ;
     RECT  42.001 113.616 42.901 113.64 ;
     RECT  41.893 9.072 42.905 9.096 ;
     RECT  42.833 19.92 42.905 19.944 ;
     RECT  42.805 31.824 42.905 31.848 ;
     RECT  42.149 37.248 42.905 37.608 ;
     RECT  42.853 22.128 42.94 22.152 ;
     RECT  42.853 2.832 42.941 3.72 ;
     RECT  42.899 41.904 42.941 41.928 ;
     RECT  42.86 10.512 42.947 10.536 ;
     RECT  42.86 12.72 42.947 12.744 ;
     RECT  42.892 34.512 42.947 34.536 ;
     RECT  42.541 38.64 42.947 38.664 ;
     RECT  42.86 45.408 42.947 45.432 ;
     RECT  42.86 47.28 42.947 47.304 ;
     RECT  42.469 52.032 42.947 52.056 ;
     RECT  42.86 53.52 42.947 53.544 ;
     RECT  42.877 61.2 42.947 61.224 ;
     RECT  42.86 62.592 42.947 63 ;
     RECT  41.861 64.56 42.947 64.584 ;
     RECT  42.793 65.664 42.947 65.688 ;
     RECT  42.86 79.056 42.947 79.08 ;
     RECT  42.901 80.352 42.947 81.24 ;
     RECT  42.86 82.32 42.947 82.344 ;
     RECT  41.825 84.768 42.947 84.792 ;
     RECT  42.869 115.728 42.947 115.752 ;
     RECT  42.841 119.088 42.947 119.112 ;
     RECT  42.86 120.192 42.947 120.216 ;
     RECT  41.893 123.072 42.947 123.096 ;
     RECT  42.86 124.752 42.947 124.776 ;
     RECT  42.941 2.832 42.977 3.432 ;
     RECT  42.805 25.584 42.977 25.608 ;
     RECT  42.893 55.872 42.977 55.896 ;
     RECT  42.805 56.88 42.977 56.904 ;
     RECT  42.977 3.408 42.985 3.432 ;
     RECT  42.901 113.616 42.985 114.552 ;
     RECT  42.947 80.352 42.988 80.376 ;
     RECT  42.793 75.936 43.043 75.96 ;
     RECT  42.956 78.048 43.043 78.072 ;
     RECT  42.805 98.496 43.043 98.52 ;
     RECT  42.901 101.04 43.043 101.064 ;
     RECT  42.853 103.632 43.043 103.656 ;
     RECT  42.659 109.968 43.043 109.992 ;
     RECT  42.956 110.976 43.043 111 ;
     RECT  42.985 113.616 43.043 114.024 ;
     RECT  42.901 121.968 43.049 121.992 ;
     RECT  41.929 126.144 43.049 126.168 ;
     RECT  42.973 74.256 43.057 74.664 ;
     RECT  42.901 17.04 43.091 17.064 ;
     RECT  42.901 14.352 43.113 14.376 ;
     RECT  42.757 68.928 43.139 68.952 ;
     RECT  43.052 71.28 43.139 71.304 ;
     RECT  43.057 74.256 43.139 74.28 ;
     RECT  42.973 94.08 43.139 94.104 ;
     RECT  42.901 89.664 43.157 89.688 ;
     RECT  42.947 62.592 43.235 62.616 ;
     RECT  45.608 2.148 45.712 127.452 ;
     RECT  45.712 2.418 45.904 127.182 ;
     RECT  48.769 90.624 49.237 90.648 ;
     RECT  49.309 63.36 50.065 63.384 ;
     RECT  49.237 26.832 50.101 27.48 ;
     RECT  50.065 124.848 50.101 124.872 ;
     RECT  47.833 2.88 51.008 2.904 ;
     RECT  49.237 7.632 51.008 8.568 ;
     RECT  50.425 10.896 51.008 10.92 ;
     RECT  49.309 13.152 51.008 13.176 ;
     RECT  50.065 16.56 51.008 16.584 ;
     RECT  50.065 21.744 51.008 22.248 ;
     RECT  50.101 26.832 51.008 27.96 ;
     RECT  49.237 30.912 51.008 30.936 ;
     RECT  49.237 33.12 51.008 33.144 ;
     RECT  49.237 38.784 51.008 38.808 ;
     RECT  49.237 44.448 51.008 44.472 ;
     RECT  49.309 49.584 51.008 49.608 ;
     RECT  49.237 52.512 51.008 52.536 ;
     RECT  49.309 54.864 51.008 54.888 ;
     RECT  49.237 57.696 51.008 58.2 ;
     RECT  50.065 61.392 51.008 61.416 ;
     RECT  50.065 63.36 51.008 63.864 ;
     RECT  50.101 66.528 51.008 66.552 ;
     RECT  50.101 69.024 51.008 69.048 ;
     RECT  49.237 79.824 51.008 80.568 ;
     RECT  50.065 83.232 51.008 83.256 ;
     RECT  49.237 86.064 51.008 86.088 ;
     RECT  49.237 88.416 51.008 88.44 ;
     RECT  49.237 90.624 51.008 91.368 ;
     RECT  50.065 94.08 51.008 94.104 ;
     RECT  49.237 98.736 51.008 98.76 ;
     RECT  49.237 99.792 51.008 99.816 ;
     RECT  49.309 105.456 51.008 105.48 ;
     RECT  48.877 109.68 51.008 109.704 ;
     RECT  49.237 116.304 51.008 116.328 ;
     RECT  50.065 119.136 51.008 119.16 ;
     RECT  49.237 122.112 51.008 122.136 ;
     RECT  50.101 124.368 51.008 124.872 ;
     RECT  51.008 2.148 51.112 127.452 ;
     RECT  51.112 2.418 51.304 127.182 ;
     RECT  51.304 66.528 51.401 66.648 ;
     RECT  51.304 2.88 56.408 2.904 ;
     RECT  51.304 7.488 56.408 7.512 ;
     RECT  51.304 8.544 56.408 8.568 ;
     RECT  51.304 10.896 56.408 10.92 ;
     RECT  51.304 13.152 56.408 13.176 ;
     RECT  51.304 16.56 56.408 16.584 ;
     RECT  51.304 21.744 56.408 22.248 ;
     RECT  51.304 26.928 56.408 27.96 ;
     RECT  51.304 30.816 56.408 30.84 ;
     RECT  51.304 33.12 56.408 33.144 ;
     RECT  51.304 38.784 56.408 38.808 ;
     RECT  51.304 44.448 56.408 44.472 ;
     RECT  51.304 49.584 56.408 49.608 ;
     RECT  51.304 52.512 56.408 52.536 ;
     RECT  51.304 54.864 56.408 54.888 ;
     RECT  51.304 57.696 56.408 58.2 ;
     RECT  51.304 61.488 56.408 61.512 ;
     RECT  51.304 63.36 56.408 63.864 ;
     RECT  51.401 66.624 56.408 66.648 ;
     RECT  51.304 69.024 56.408 69.048 ;
     RECT  51.304 79.824 56.408 80.424 ;
     RECT  51.304 83.232 56.408 83.256 ;
     RECT  51.304 86.064 56.408 86.088 ;
     RECT  51.304 88.416 56.408 88.44 ;
     RECT  51.304 90.768 56.408 91.224 ;
     RECT  51.304 94.08 56.408 94.104 ;
     RECT  51.304 98.736 56.408 98.76 ;
     RECT  51.304 99.792 56.408 99.816 ;
     RECT  51.304 105.456 56.408 105.48 ;
     RECT  51.304 109.68 56.408 109.704 ;
     RECT  51.304 116.304 56.408 116.328 ;
     RECT  51.304 119.136 56.408 119.16 ;
     RECT  51.304 121.968 56.408 121.992 ;
     RECT  51.304 124.368 56.408 124.872 ;
     RECT  56.408 2.148 56.512 127.452 ;
     RECT  56.512 2.418 56.704 127.182 ;
     RECT  56.704 2.88 61.808 2.904 ;
     RECT  56.704 7.488 61.808 7.512 ;
     RECT  56.704 8.544 61.808 8.568 ;
     RECT  56.704 10.896 61.808 10.92 ;
     RECT  56.704 13.152 61.808 13.176 ;
     RECT  56.704 16.56 61.808 16.584 ;
     RECT  56.704 21.744 61.808 22.248 ;
     RECT  56.704 26.928 61.808 27.96 ;
     RECT  56.704 30.816 61.808 30.84 ;
     RECT  56.704 33.12 61.808 33.144 ;
     RECT  56.704 38.784 61.808 38.808 ;
     RECT  56.704 44.448 61.808 44.472 ;
     RECT  56.704 49.584 61.808 49.608 ;
     RECT  56.704 52.512 61.808 52.536 ;
     RECT  56.704 54.864 61.808 54.888 ;
     RECT  56.704 57.696 61.808 58.2 ;
     RECT  56.704 61.488 61.808 61.512 ;
     RECT  56.704 63.36 61.808 63.864 ;
     RECT  56.704 66.624 61.808 66.648 ;
     RECT  56.704 69.024 61.808 69.048 ;
     RECT  56.704 79.824 61.808 80.424 ;
     RECT  56.704 83.232 61.808 83.256 ;
     RECT  56.704 86.064 61.808 86.088 ;
     RECT  56.704 88.416 61.808 88.44 ;
     RECT  56.704 90.768 61.808 91.224 ;
     RECT  56.704 94.08 61.808 94.104 ;
     RECT  56.704 98.736 61.808 98.76 ;
     RECT  56.704 99.792 61.808 99.816 ;
     RECT  56.704 105.456 61.808 105.48 ;
     RECT  56.704 109.68 61.808 109.704 ;
     RECT  56.704 116.304 61.808 116.328 ;
     RECT  56.704 119.136 61.808 119.16 ;
     RECT  56.704 121.968 61.808 121.992 ;
     RECT  56.704 124.368 61.808 124.872 ;
     RECT  61.808 2.148 61.912 127.452 ;
     RECT  61.912 2.418 62.104 127.182 ;
     RECT  62.104 2.88 67.208 2.904 ;
     RECT  62.104 7.488 67.208 7.512 ;
     RECT  62.104 8.544 67.208 8.568 ;
     RECT  62.104 10.896 67.208 10.92 ;
     RECT  62.104 13.152 67.208 13.176 ;
     RECT  62.104 16.56 67.208 16.584 ;
     RECT  62.104 21.744 67.208 22.248 ;
     RECT  62.104 26.928 67.208 27.96 ;
     RECT  62.104 30.816 67.208 30.84 ;
     RECT  62.104 33.12 67.208 33.144 ;
     RECT  62.104 38.784 67.208 38.808 ;
     RECT  62.104 44.448 67.208 44.472 ;
     RECT  62.104 49.584 67.208 49.608 ;
     RECT  62.104 52.512 67.208 52.536 ;
     RECT  62.104 54.864 67.208 54.888 ;
     RECT  62.104 57.696 67.208 58.2 ;
     RECT  62.104 61.488 67.208 61.512 ;
     RECT  62.104 63.36 67.208 63.864 ;
     RECT  62.104 66.624 67.208 66.648 ;
     RECT  62.104 69.024 67.208 69.048 ;
     RECT  62.104 79.824 67.208 80.424 ;
     RECT  62.104 83.232 67.208 83.256 ;
     RECT  62.104 86.064 67.208 86.088 ;
     RECT  62.104 88.416 67.208 88.44 ;
     RECT  62.104 90.768 67.208 91.224 ;
     RECT  62.104 94.08 67.208 94.104 ;
     RECT  62.104 98.736 67.208 98.76 ;
     RECT  62.104 99.792 67.208 99.816 ;
     RECT  62.104 105.456 67.208 105.48 ;
     RECT  62.104 109.68 67.208 109.704 ;
     RECT  62.104 116.304 67.208 116.328 ;
     RECT  62.104 119.136 67.208 119.16 ;
     RECT  62.104 121.968 67.208 121.992 ;
     RECT  62.104 124.368 67.208 124.872 ;
     RECT  67.208 2.148 67.312 127.452 ;
     RECT  67.312 2.418 67.504 127.182 ;
     RECT  67.504 2.88 72.608 2.904 ;
     RECT  67.504 7.488 72.608 7.512 ;
     RECT  67.504 8.544 72.608 8.568 ;
     RECT  67.504 10.896 72.608 10.92 ;
     RECT  67.504 13.152 72.608 13.176 ;
     RECT  67.504 16.56 72.608 16.584 ;
     RECT  67.504 21.744 72.608 22.248 ;
     RECT  67.504 26.928 72.608 27.96 ;
     RECT  67.504 30.816 72.608 30.84 ;
     RECT  67.504 33.12 72.608 33.144 ;
     RECT  67.504 38.784 72.608 38.808 ;
     RECT  67.504 44.448 72.608 44.472 ;
     RECT  67.504 49.584 72.608 49.608 ;
     RECT  67.504 52.512 72.608 52.536 ;
     RECT  67.504 54.864 72.608 54.888 ;
     RECT  67.504 57.696 72.608 58.2 ;
     RECT  67.504 61.488 72.608 61.512 ;
     RECT  67.504 63.36 72.608 63.864 ;
     RECT  67.504 66.624 72.608 66.648 ;
     RECT  67.504 69.024 72.608 69.048 ;
     RECT  67.504 79.824 72.608 80.424 ;
     RECT  67.504 83.232 72.608 83.256 ;
     RECT  67.504 86.064 72.608 86.088 ;
     RECT  67.504 88.416 72.608 88.44 ;
     RECT  67.504 90.768 72.608 91.224 ;
     RECT  67.504 94.08 72.608 94.104 ;
     RECT  67.504 98.736 72.608 98.76 ;
     RECT  67.504 99.792 72.608 99.816 ;
     RECT  67.504 105.456 72.608 105.48 ;
     RECT  67.504 109.68 72.608 109.704 ;
     RECT  67.504 116.304 72.608 116.328 ;
     RECT  67.504 119.136 72.608 119.16 ;
     RECT  67.504 121.968 72.608 121.992 ;
     RECT  67.504 124.368 72.608 124.872 ;
     RECT  72.608 2.148 72.712 127.452 ;
     RECT  72.712 2.418 72.904 127.182 ;
     RECT  72.904 2.88 78.008 2.904 ;
     RECT  72.904 7.488 78.008 7.512 ;
     RECT  72.904 8.544 78.008 8.568 ;
     RECT  72.904 10.896 78.008 10.92 ;
     RECT  72.904 13.152 78.008 13.176 ;
     RECT  72.904 16.56 78.008 16.584 ;
     RECT  72.904 21.744 78.008 22.248 ;
     RECT  72.904 26.928 78.008 27.96 ;
     RECT  72.904 30.816 78.008 30.84 ;
     RECT  72.904 33.12 78.008 33.144 ;
     RECT  72.904 38.784 78.008 38.808 ;
     RECT  72.904 44.448 78.008 44.472 ;
     RECT  72.904 49.584 78.008 49.608 ;
     RECT  72.904 52.512 78.008 52.536 ;
     RECT  72.904 54.864 78.008 54.888 ;
     RECT  72.904 57.696 78.008 58.2 ;
     RECT  72.904 61.488 78.008 61.512 ;
     RECT  72.904 63.36 78.008 63.864 ;
     RECT  72.904 66.624 78.008 66.648 ;
     RECT  72.904 69.024 78.008 69.048 ;
     RECT  72.904 79.824 78.008 80.424 ;
     RECT  72.904 83.232 78.008 83.256 ;
     RECT  72.904 86.064 78.008 86.088 ;
     RECT  72.904 88.416 78.008 88.44 ;
     RECT  72.904 90.768 78.008 91.224 ;
     RECT  72.904 94.08 78.008 94.104 ;
     RECT  72.904 98.736 78.008 98.76 ;
     RECT  72.904 99.792 78.008 99.816 ;
     RECT  72.904 105.456 78.008 105.48 ;
     RECT  72.904 109.68 78.008 109.704 ;
     RECT  72.904 116.304 78.008 116.328 ;
     RECT  72.904 119.136 78.008 119.16 ;
     RECT  72.904 121.968 78.008 121.992 ;
     RECT  72.904 124.368 78.008 124.872 ;
     RECT  78.008 2.148 78.112 127.452 ;
     RECT  78.112 2.418 78.304 127.182 ;
     RECT  78.304 30.816 83.293 30.84 ;
     RECT  78.304 2.88 83.408 2.904 ;
     RECT  78.304 7.488 83.408 7.512 ;
     RECT  78.304 8.544 83.408 8.568 ;
     RECT  78.304 10.896 83.408 10.92 ;
     RECT  78.304 13.152 83.408 13.176 ;
     RECT  78.304 16.56 83.408 16.584 ;
     RECT  78.304 21.744 83.408 22.248 ;
     RECT  78.304 26.928 83.408 27.96 ;
     RECT  83.293 30.816 83.408 30.936 ;
     RECT  78.304 33.12 83.408 33.144 ;
     RECT  78.304 38.784 83.408 38.808 ;
     RECT  78.304 44.448 83.408 44.472 ;
     RECT  78.304 49.584 83.408 49.608 ;
     RECT  78.304 52.512 83.408 52.536 ;
     RECT  78.304 54.864 83.408 54.888 ;
     RECT  78.304 57.696 83.408 58.2 ;
     RECT  78.304 61.488 83.408 61.512 ;
     RECT  78.304 63.36 83.408 63.864 ;
     RECT  78.304 66.624 83.408 66.648 ;
     RECT  78.304 69.024 83.408 69.048 ;
     RECT  78.304 79.824 83.408 80.424 ;
     RECT  78.304 83.232 83.408 83.256 ;
     RECT  78.304 86.064 83.408 86.088 ;
     RECT  78.304 88.416 83.408 88.44 ;
     RECT  78.304 90.768 83.408 91.224 ;
     RECT  78.304 94.08 83.408 94.104 ;
     RECT  78.304 98.736 83.408 98.76 ;
     RECT  78.304 99.792 83.408 99.816 ;
     RECT  78.304 105.456 83.408 105.48 ;
     RECT  78.304 109.68 83.408 109.704 ;
     RECT  78.304 116.304 83.408 116.328 ;
     RECT  78.304 119.136 83.408 119.16 ;
     RECT  78.304 121.968 83.408 121.992 ;
     RECT  78.304 124.368 83.408 124.872 ;
     RECT  83.408 2.148 83.512 127.452 ;
     RECT  83.512 2.418 83.704 127.182 ;
     RECT  83.704 124.368 84.877 124.872 ;
     RECT  83.704 121.056 84.913 121.992 ;
     RECT  84.877 123.408 84.913 124.872 ;
     RECT  83.704 2.88 85.453 2.904 ;
     RECT  85.453 2.4 85.489 2.904 ;
     RECT  83.704 7.104 85.489 8.568 ;
     RECT  83.704 10.896 85.489 10.92 ;
     RECT  83.704 13.152 85.489 13.752 ;
     RECT  83.704 16.56 85.489 16.584 ;
     RECT  83.704 21.744 85.489 22.248 ;
     RECT  83.704 26.976 85.489 27.96 ;
     RECT  83.704 30.912 85.489 30.936 ;
     RECT  83.704 33.12 85.489 33.144 ;
     RECT  83.704 38.784 85.489 38.808 ;
     RECT  83.704 43.968 85.489 44.472 ;
     RECT  83.704 49.584 85.489 49.608 ;
     RECT  83.704 52.512 85.489 52.536 ;
     RECT  83.704 54.864 85.489 54.888 ;
     RECT  83.704 57.696 85.489 58.2 ;
     RECT  83.704 61.488 85.489 61.512 ;
     RECT  83.704 63.36 85.489 63.864 ;
     RECT  83.704 66.672 85.489 66.696 ;
     RECT  83.704 69.024 85.489 69.048 ;
     RECT  83.704 74.736 85.489 74.76 ;
     RECT  83.704 79.824 85.489 80.424 ;
     RECT  83.704 83.232 85.489 83.256 ;
     RECT  83.704 86.064 85.489 86.088 ;
     RECT  83.704 88.416 85.489 88.44 ;
     RECT  83.704 90.768 85.489 91.272 ;
     RECT  83.704 94.08 85.489 94.104 ;
     RECT  83.704 98.736 85.489 99.816 ;
     RECT  83.704 104.976 85.489 105.48 ;
     RECT  83.704 109.68 85.489 109.704 ;
     RECT  83.704 116.304 85.489 116.328 ;
     RECT  83.704 119.136 85.489 119.16 ;
     RECT  84.913 121.056 85.489 124.872 ;
     RECT  83.704 126.72 85.489 126.744 ;
     RECT  85.489 2.4 86.281 18.504 ;
     RECT  85.489 19.872 86.281 31.704 ;
     RECT  85.489 33.12 86.281 37.416 ;
     RECT  85.489 38.784 86.281 94.584 ;
     RECT  85.489 96 86.281 109.704 ;
     RECT  85.489 111.12 86.281 111.624 ;
     RECT  85.489 112.992 86.281 119.16 ;
     RECT  85.489 120.576 86.281 127.224 ;
     RECT  86.281 2.4 86.364 127.224 ;
    LAYER M5 ;
     RECT  2.4 2.137 2.52 2.151 ;
     RECT  7.8 2.137 7.92 2.151 ;
     RECT  13.2 2.137 13.32 2.151 ;
     RECT  18.6 2.137 18.72 2.151 ;
     RECT  24 2.137 24.12 2.151 ;
     RECT  29.4 2.137 29.52 2.151 ;
     RECT  34.8 2.137 34.92 2.151 ;
     RECT  40.2 2.137 40.32 2.151 ;
     RECT  45.6 2.137 45.72 2.151 ;
     RECT  51 2.137 51.12 2.151 ;
     RECT  56.4 2.137 56.52 2.151 ;
     RECT  61.8 2.137 61.92 2.151 ;
     RECT  67.2 2.137 67.32 2.151 ;
     RECT  72.6 2.137 72.72 2.151 ;
     RECT  78 2.137 78.12 2.151 ;
     RECT  83.4 2.137 83.52 2.151 ;
     RECT  40.2 2.151 40.512 3.397 ;
     RECT  42.912 2.821 42.936 3.443 ;
     RECT  41.808 4.501 41.832 5.173 ;
     RECT  42.864 3.685 42.888 5.173 ;
     RECT  41.808 5.173 42.888 5.219 ;
     RECT  40.2 3.397 40.68 5.701 ;
     RECT  41.808 5.219 42.744 6.563 ;
     RECT  41.856 6.563 42.744 7.091 ;
     RECT  40.2 5.701 40.776 10.307 ;
     RECT  41.856 7.091 41.88 11.459 ;
     RECT  41.808 11.941 41.832 12.517 ;
     RECT  42.912 10.501 42.936 12.517 ;
     RECT  40.2 10.307 40.68 12.901 ;
     RECT  41.808 12.517 42.936 13.571 ;
     RECT  42 13.571 42.936 14.341 ;
     RECT  42 14.341 43.08 14.387 ;
     RECT  42 14.387 42.024 15.301 ;
     RECT  43.056 14.387 43.08 17.075 ;
     RECT  41.856 15.301 42.024 19.909 ;
     RECT  41.76 19.909 42.888 22.163 ;
     RECT  41.76 22.163 42.072 25.573 ;
     RECT  40.2 12.901 40.776 25.955 ;
     RECT  41.76 25.573 42.84 28.453 ;
     RECT  41.712 28.453 42.84 29.795 ;
     RECT  41.76 29.795 42.84 34.501 ;
     RECT  41.76 34.501 42.936 36.901 ;
     RECT  40.2 25.955 40.512 38.005 ;
     RECT  41.664 36.901 42.936 38.005 ;
     RECT  40.2 38.005 42.936 39.731 ;
     RECT  40.2 39.731 40.512 40.981 ;
     RECT  40.2 40.981 40.776 44.965 ;
     RECT  41.76 39.731 42.936 44.965 ;
     RECT  40.2 44.965 42.936 46.259 ;
     RECT  41.856 46.259 42.936 50.579 ;
     RECT  41.856 50.579 41.88 51.253 ;
     RECT  40.2 46.259 40.776 51.587 ;
     RECT  41.76 51.253 41.88 53.795 ;
     RECT  42.912 50.579 42.936 55.907 ;
     RECT  41.856 53.795 41.88 56.869 ;
     RECT  41.856 56.869 42.84 60.373 ;
     RECT  41.76 60.373 42.84 60.467 ;
     RECT  41.76 60.467 41.88 61.619 ;
     RECT  41.856 61.619 41.88 62.149 ;
     RECT  42.912 61.189 42.936 62.149 ;
     RECT  41.856 62.149 42.936 62.195 ;
     RECT  41.952 62.195 42.936 62.581 ;
     RECT  41.952 62.581 43.224 63.781 ;
     RECT  40.2 51.587 40.68 64.355 ;
     RECT  41.76 63.781 43.224 65.699 ;
     RECT  0.144 66.661 0.168 66.803 ;
     RECT  41.76 65.699 41.976 67.283 ;
     RECT  40.2 64.355 40.512 68.821 ;
     RECT  43.2 65.699 43.224 68.917 ;
     RECT  41.856 67.283 41.976 72.277 ;
     RECT  40.2 68.821 40.776 72.805 ;
     RECT  41.808 72.277 41.976 72.805 ;
     RECT  40.2 72.805 41.976 72.995 ;
     RECT  43.104 68.917 43.224 74.629 ;
     RECT  41.52 72.995 41.976 75.299 ;
     RECT  41.568 75.299 41.976 77.701 ;
     RECT  43.008 74.629 43.224 77.701 ;
     RECT  41.568 77.701 43.224 78.083 ;
     RECT  41.568 78.083 42.072 79.045 ;
     RECT  43.2 78.083 43.224 79.045 ;
     RECT  40.2 72.995 40.512 79.717 ;
     RECT  41.568 79.045 43.224 79.717 ;
     RECT  40.2 79.717 43.224 79.763 ;
     RECT  41.856 79.763 43.224 80.725 ;
     RECT  41.76 80.725 43.224 82.691 ;
     RECT  40.2 79.763 40.776 85.285 ;
     RECT  41.856 82.691 43.224 85.285 ;
     RECT  40.2 85.285 43.224 86.435 ;
     RECT  40.2 86.435 41.64 86.675 ;
     RECT  40.2 86.675 40.776 89.461 ;
     RECT  42.624 86.435 43.224 89.461 ;
     RECT  40.2 89.461 43.224 90.083 ;
     RECT  40.2 90.083 40.68 92.963 ;
     RECT  40.2 92.963 40.512 94.021 ;
     RECT  41.712 90.083 43.224 94.021 ;
     RECT  40.2 94.021 43.224 100.355 ;
     RECT  41.76 100.355 43.224 103.763 ;
     RECT  41.904 103.763 43.224 104.821 ;
     RECT  41.856 104.821 43.224 110.869 ;
     RECT  41.808 110.869 43.224 111.731 ;
     RECT  42.624 111.731 43.224 112.355 ;
     RECT  43.008 112.355 43.224 114.517 ;
     RECT  41.76 112.837 41.784 114.949 ;
     RECT  41.616 114.949 41.784 114.995 ;
     RECT  42.912 114.517 43.224 116.197 ;
     RECT  41.616 114.995 41.64 116.915 ;
     RECT  40.2 100.355 40.512 118.165 ;
     RECT  42.768 116.197 43.224 118.595 ;
     RECT  40.2 118.165 40.872 120.467 ;
     RECT  42.912 118.595 43.224 124.787 ;
     RECT  41.808 124.405 41.832 126.611 ;
     RECT  2.4 2.151 2.712 127.449 ;
     RECT  7.8 2.151 8.112 127.449 ;
     RECT  13.2 2.151 13.512 127.449 ;
     RECT  18.6 2.151 18.912 127.449 ;
     RECT  24 2.151 24.312 127.449 ;
     RECT  29.4 2.151 29.712 127.449 ;
     RECT  34.8 2.151 35.112 127.449 ;
     RECT  40.2 120.467 40.512 127.449 ;
     RECT  45.6 2.151 45.912 127.449 ;
     RECT  51 2.151 51.312 127.449 ;
     RECT  56.4 2.151 56.712 127.449 ;
     RECT  61.8 2.151 62.112 127.449 ;
     RECT  67.2 2.151 67.512 127.449 ;
     RECT  72.6 2.151 72.912 127.449 ;
     RECT  78 2.151 78.312 127.449 ;
     RECT  83.4 2.151 83.712 127.449 ;
     RECT  2.4 127.449 2.52 127.463 ;
     RECT  7.8 127.449 7.92 127.463 ;
     RECT  13.2 127.449 13.32 127.463 ;
     RECT  18.6 127.449 18.72 127.463 ;
     RECT  24 127.449 24.12 127.463 ;
     RECT  29.4 127.449 29.52 127.463 ;
     RECT  34.8 127.449 34.92 127.463 ;
     RECT  40.2 127.449 40.32 127.463 ;
     RECT  45.6 127.449 45.72 127.463 ;
     RECT  51 127.449 51.12 127.463 ;
     RECT  56.4 127.449 56.52 127.463 ;
     RECT  61.8 127.449 61.92 127.463 ;
     RECT  67.2 127.449 67.32 127.463 ;
     RECT  72.6 127.449 72.72 127.463 ;
     RECT  78 127.449 78.12 127.463 ;
     RECT  83.4 127.449 83.52 127.463 ;
     RECT  43.2 124.787 43.224 129.552 ;
  END
END ot_s81hd_lsc_r1m
END LIBRARY
